VERSION 5.7 ;
  NOWIREEXTENSIONATPIN ON ;
  DIVIDERCHAR "/" ;
  BUSBITCHARS "[]" ;
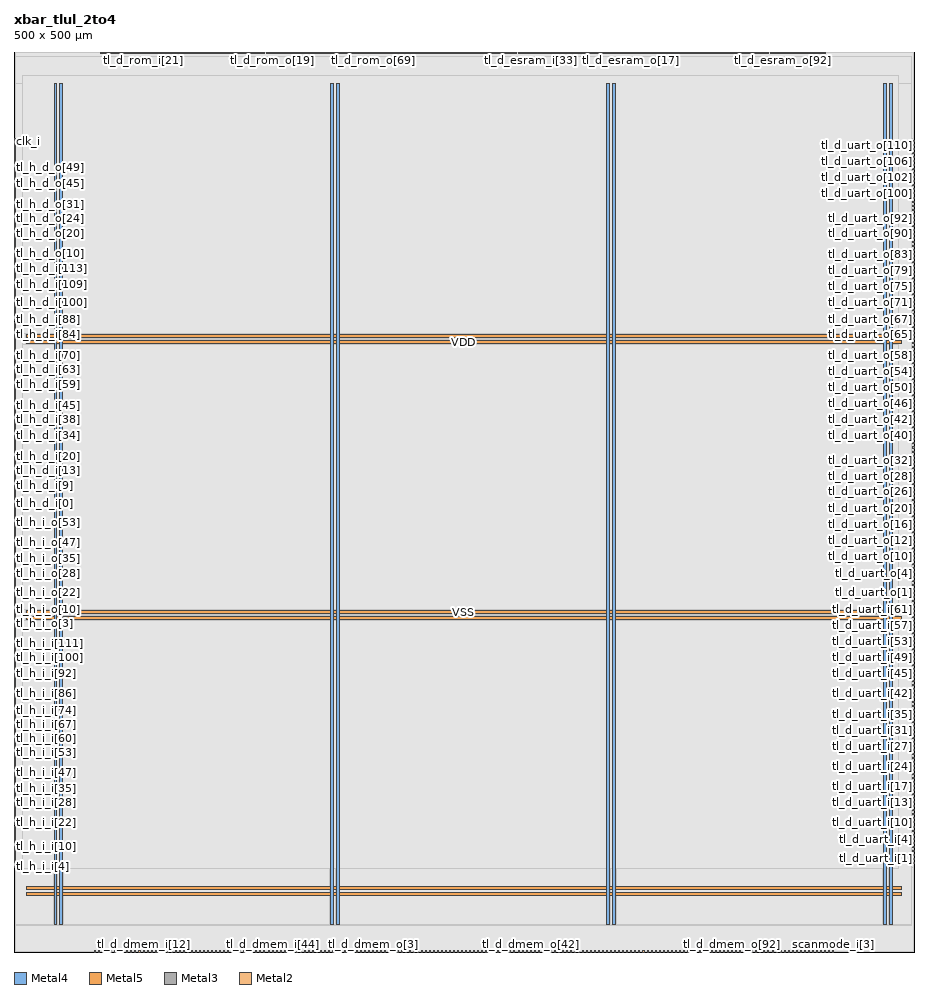
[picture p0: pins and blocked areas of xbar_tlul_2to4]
MACRO xbar_tlul_2to4
  CLASS BLOCK ;
  FOREIGN xbar_tlul_2to4 ;
  ORIGIN 0.000 0.000 ;
  SIZE 500.000 BY 500.000 ;
  PIN VDD
    DIRECTION INOUT ;
    USE POWER ;
    PORT
      LAYER Metal4 ;
        RECT 22.240 15.380 23.840 482.460 ;
    END
    PORT
      LAYER Metal4 ;
        RECT 175.840 15.380 177.440 482.460 ;
    END
    PORT
      LAYER Metal4 ;
        RECT 329.440 15.380 331.040 482.460 ;
    END
    PORT
      LAYER Metal4 ;
        RECT 483.040 15.380 484.640 482.460 ;
    END
    PORT
      LAYER Metal5 ;
        RECT 6.720 31.530 492.800 33.130 ;
    END
    PORT
      LAYER Metal5 ;
        RECT 6.720 184.710 492.800 186.310 ;
    END
    PORT
      LAYER Metal5 ;
        RECT 6.720 337.890 492.800 339.490 ;
    END
  END VDD
  PIN VSS
    DIRECTION INOUT ;
    USE GROUND ;
    PORT
      LAYER Metal4 ;
        RECT 25.540 15.380 27.140 482.460 ;
    END
    PORT
      LAYER Metal4 ;
        RECT 179.140 15.380 180.740 482.460 ;
    END
    PORT
      LAYER Metal4 ;
        RECT 332.740 15.380 334.340 482.460 ;
    END
    PORT
      LAYER Metal4 ;
        RECT 486.340 15.380 487.940 482.460 ;
    END
    PORT
      LAYER Metal5 ;
        RECT 6.720 34.830 492.800 36.430 ;
    END
    PORT
      LAYER Metal5 ;
        RECT 6.720 188.010 492.800 189.610 ;
    END
    PORT
      LAYER Metal5 ;
        RECT 6.720 341.190 492.800 342.790 ;
    END
  END VSS
  PIN clk_i
    DIRECTION INPUT ;
    USE SIGNAL ;
    ANTENNAGATEAREA 4.738000 ;
    PORT
      LAYER Metal3 ;
        RECT 0.000 450.240 0.560 450.800 ;
    END
  END clk_i
  PIN rst_ni
    DIRECTION INPUT ;
    USE SIGNAL ;
    ANTENNAGATEAREA 0.726000 ;
    PORT
      LAYER Metal3 ;
        RECT 0.000 451.360 0.560 451.920 ;
    END
  END rst_ni
  PIN scanmode_i[0]
    DIRECTION INPUT ;
    USE SIGNAL ;
    PORT
      LAYER Metal2 ;
        RECT 448.000 0.000 448.560 0.560 ;
    END
  END scanmode_i[0]
  PIN scanmode_i[1]
    DIRECTION INPUT ;
    USE SIGNAL ;
    PORT
      LAYER Metal2 ;
        RECT 450.240 0.000 450.800 0.560 ;
    END
  END scanmode_i[1]
  PIN scanmode_i[2]
    DIRECTION INPUT ;
    USE SIGNAL ;
    PORT
      LAYER Metal2 ;
        RECT 452.480 0.000 453.040 0.560 ;
    END
  END scanmode_i[2]
  PIN scanmode_i[3]
    DIRECTION INPUT ;
    USE SIGNAL ;
    PORT
      LAYER Metal2 ;
        RECT 454.720 0.000 455.280 0.560 ;
    END
  END scanmode_i[3]
  PIN tl_d_dmem_i[0]
    DIRECTION INPUT ;
    USE SIGNAL ;
    ANTENNAGATEAREA 0.396000 ;
    PORT
      LAYER Metal2 ;
        RECT 44.800 0.000 45.360 0.560 ;
    END
  END tl_d_dmem_i[0]
  PIN tl_d_dmem_i[10]
    DIRECTION INPUT ;
    USE SIGNAL ;
    ANTENNAGATEAREA 0.396000 ;
    PORT
      LAYER Metal2 ;
        RECT 67.200 0.000 67.760 0.560 ;
    END
  END tl_d_dmem_i[10]
  PIN tl_d_dmem_i[11]
    DIRECTION INPUT ;
    USE SIGNAL ;
    ANTENNAGATEAREA 0.396000 ;
    PORT
      LAYER Metal2 ;
        RECT 69.440 0.000 70.000 0.560 ;
    END
  END tl_d_dmem_i[11]
  PIN tl_d_dmem_i[12]
    DIRECTION INPUT ;
    USE SIGNAL ;
    ANTENNAGATEAREA 0.396000 ;
    PORT
      LAYER Metal2 ;
        RECT 71.680 0.000 72.240 0.560 ;
    END
  END tl_d_dmem_i[12]
  PIN tl_d_dmem_i[13]
    DIRECTION INPUT ;
    USE SIGNAL ;
    ANTENNAGATEAREA 0.396000 ;
    PORT
      LAYER Metal2 ;
        RECT 73.920 0.000 74.480 0.560 ;
    END
  END tl_d_dmem_i[13]
  PIN tl_d_dmem_i[14]
    DIRECTION INPUT ;
    USE SIGNAL ;
    ANTENNAGATEAREA 0.396000 ;
    PORT
      LAYER Metal2 ;
        RECT 76.160 0.000 76.720 0.560 ;
    END
  END tl_d_dmem_i[14]
  PIN tl_d_dmem_i[15]
    DIRECTION INPUT ;
    USE SIGNAL ;
    ANTENNAGATEAREA 0.396000 ;
    PORT
      LAYER Metal2 ;
        RECT 78.400 0.000 78.960 0.560 ;
    END
  END tl_d_dmem_i[15]
  PIN tl_d_dmem_i[16]
    DIRECTION INPUT ;
    USE SIGNAL ;
    ANTENNAGATEAREA 0.396000 ;
    PORT
      LAYER Metal2 ;
        RECT 80.640 0.000 81.200 0.560 ;
    END
  END tl_d_dmem_i[16]
  PIN tl_d_dmem_i[17]
    DIRECTION INPUT ;
    USE SIGNAL ;
    ANTENNAGATEAREA 0.396000 ;
    PORT
      LAYER Metal2 ;
        RECT 82.880 0.000 83.440 0.560 ;
    END
  END tl_d_dmem_i[17]
  PIN tl_d_dmem_i[18]
    DIRECTION INPUT ;
    USE SIGNAL ;
    ANTENNAGATEAREA 0.396000 ;
    PORT
      LAYER Metal2 ;
        RECT 85.120 0.000 85.680 0.560 ;
    END
  END tl_d_dmem_i[18]
  PIN tl_d_dmem_i[19]
    DIRECTION INPUT ;
    USE SIGNAL ;
    ANTENNAGATEAREA 0.396000 ;
    PORT
      LAYER Metal2 ;
        RECT 87.360 0.000 87.920 0.560 ;
    END
  END tl_d_dmem_i[19]
  PIN tl_d_dmem_i[1]
    DIRECTION INPUT ;
    USE SIGNAL ;
    ANTENNAGATEAREA 0.396000 ;
    PORT
      LAYER Metal2 ;
        RECT 47.040 0.000 47.600 0.560 ;
    END
  END tl_d_dmem_i[1]
  PIN tl_d_dmem_i[20]
    DIRECTION INPUT ;
    USE SIGNAL ;
    ANTENNAGATEAREA 0.396000 ;
    PORT
      LAYER Metal2 ;
        RECT 89.600 0.000 90.160 0.560 ;
    END
  END tl_d_dmem_i[20]
  PIN tl_d_dmem_i[21]
    DIRECTION INPUT ;
    USE SIGNAL ;
    ANTENNAGATEAREA 0.396000 ;
    PORT
      LAYER Metal2 ;
        RECT 91.840 0.000 92.400 0.560 ;
    END
  END tl_d_dmem_i[21]
  PIN tl_d_dmem_i[22]
    DIRECTION INPUT ;
    USE SIGNAL ;
    ANTENNAGATEAREA 0.396000 ;
    PORT
      LAYER Metal2 ;
        RECT 94.080 0.000 94.640 0.560 ;
    END
  END tl_d_dmem_i[22]
  PIN tl_d_dmem_i[23]
    DIRECTION INPUT ;
    USE SIGNAL ;
    ANTENNAGATEAREA 0.396000 ;
    PORT
      LAYER Metal2 ;
        RECT 96.320 0.000 96.880 0.560 ;
    END
  END tl_d_dmem_i[23]
  PIN tl_d_dmem_i[24]
    DIRECTION INPUT ;
    USE SIGNAL ;
    ANTENNAGATEAREA 0.396000 ;
    PORT
      LAYER Metal2 ;
        RECT 98.560 0.000 99.120 0.560 ;
    END
  END tl_d_dmem_i[24]
  PIN tl_d_dmem_i[25]
    DIRECTION INPUT ;
    USE SIGNAL ;
    ANTENNAGATEAREA 0.396000 ;
    PORT
      LAYER Metal2 ;
        RECT 100.800 0.000 101.360 0.560 ;
    END
  END tl_d_dmem_i[25]
  PIN tl_d_dmem_i[26]
    DIRECTION INPUT ;
    USE SIGNAL ;
    ANTENNAGATEAREA 0.396000 ;
    PORT
      LAYER Metal2 ;
        RECT 103.040 0.000 103.600 0.560 ;
    END
  END tl_d_dmem_i[26]
  PIN tl_d_dmem_i[27]
    DIRECTION INPUT ;
    USE SIGNAL ;
    ANTENNAGATEAREA 0.396000 ;
    PORT
      LAYER Metal2 ;
        RECT 105.280 0.000 105.840 0.560 ;
    END
  END tl_d_dmem_i[27]
  PIN tl_d_dmem_i[28]
    DIRECTION INPUT ;
    USE SIGNAL ;
    ANTENNAGATEAREA 0.396000 ;
    PORT
      LAYER Metal2 ;
        RECT 107.520 0.000 108.080 0.560 ;
    END
  END tl_d_dmem_i[28]
  PIN tl_d_dmem_i[29]
    DIRECTION INPUT ;
    USE SIGNAL ;
    ANTENNAGATEAREA 0.396000 ;
    PORT
      LAYER Metal2 ;
        RECT 109.760 0.000 110.320 0.560 ;
    END
  END tl_d_dmem_i[29]
  PIN tl_d_dmem_i[2]
    DIRECTION INPUT ;
    USE SIGNAL ;
    ANTENNAGATEAREA 0.396000 ;
    PORT
      LAYER Metal2 ;
        RECT 49.280 0.000 49.840 0.560 ;
    END
  END tl_d_dmem_i[2]
  PIN tl_d_dmem_i[30]
    DIRECTION INPUT ;
    USE SIGNAL ;
    ANTENNAGATEAREA 0.396000 ;
    PORT
      LAYER Metal2 ;
        RECT 112.000 0.000 112.560 0.560 ;
    END
  END tl_d_dmem_i[30]
  PIN tl_d_dmem_i[31]
    DIRECTION INPUT ;
    USE SIGNAL ;
    ANTENNAGATEAREA 0.396000 ;
    PORT
      LAYER Metal2 ;
        RECT 114.240 0.000 114.800 0.560 ;
    END
  END tl_d_dmem_i[31]
  PIN tl_d_dmem_i[32]
    DIRECTION INPUT ;
    USE SIGNAL ;
    ANTENNAGATEAREA 0.396000 ;
    PORT
      LAYER Metal2 ;
        RECT 116.480 0.000 117.040 0.560 ;
    END
  END tl_d_dmem_i[32]
  PIN tl_d_dmem_i[33]
    DIRECTION INPUT ;
    USE SIGNAL ;
    ANTENNAGATEAREA 0.396000 ;
    PORT
      LAYER Metal2 ;
        RECT 118.720 0.000 119.280 0.560 ;
    END
  END tl_d_dmem_i[33]
  PIN tl_d_dmem_i[34]
    DIRECTION INPUT ;
    USE SIGNAL ;
    ANTENNAGATEAREA 0.396000 ;
    PORT
      LAYER Metal2 ;
        RECT 120.960 0.000 121.520 0.560 ;
    END
  END tl_d_dmem_i[34]
  PIN tl_d_dmem_i[35]
    DIRECTION INPUT ;
    USE SIGNAL ;
    ANTENNAGATEAREA 0.396000 ;
    PORT
      LAYER Metal2 ;
        RECT 123.200 0.000 123.760 0.560 ;
    END
  END tl_d_dmem_i[35]
  PIN tl_d_dmem_i[36]
    DIRECTION INPUT ;
    USE SIGNAL ;
    ANTENNAGATEAREA 0.396000 ;
    PORT
      LAYER Metal2 ;
        RECT 125.440 0.000 126.000 0.560 ;
    END
  END tl_d_dmem_i[36]
  PIN tl_d_dmem_i[37]
    DIRECTION INPUT ;
    USE SIGNAL ;
    ANTENNAGATEAREA 0.396000 ;
    PORT
      LAYER Metal2 ;
        RECT 127.680 0.000 128.240 0.560 ;
    END
  END tl_d_dmem_i[37]
  PIN tl_d_dmem_i[38]
    DIRECTION INPUT ;
    USE SIGNAL ;
    ANTENNAGATEAREA 0.396000 ;
    PORT
      LAYER Metal2 ;
        RECT 129.920 0.000 130.480 0.560 ;
    END
  END tl_d_dmem_i[38]
  PIN tl_d_dmem_i[39]
    DIRECTION INPUT ;
    USE SIGNAL ;
    ANTENNAGATEAREA 0.396000 ;
    PORT
      LAYER Metal2 ;
        RECT 132.160 0.000 132.720 0.560 ;
    END
  END tl_d_dmem_i[39]
  PIN tl_d_dmem_i[3]
    DIRECTION INPUT ;
    USE SIGNAL ;
    ANTENNAGATEAREA 0.396000 ;
    PORT
      LAYER Metal2 ;
        RECT 51.520 0.000 52.080 0.560 ;
    END
  END tl_d_dmem_i[3]
  PIN tl_d_dmem_i[40]
    DIRECTION INPUT ;
    USE SIGNAL ;
    ANTENNAGATEAREA 0.396000 ;
    PORT
      LAYER Metal2 ;
        RECT 134.400 0.000 134.960 0.560 ;
    END
  END tl_d_dmem_i[40]
  PIN tl_d_dmem_i[41]
    DIRECTION INPUT ;
    USE SIGNAL ;
    ANTENNAGATEAREA 0.396000 ;
    PORT
      LAYER Metal2 ;
        RECT 136.640 0.000 137.200 0.560 ;
    END
  END tl_d_dmem_i[41]
  PIN tl_d_dmem_i[42]
    DIRECTION INPUT ;
    USE SIGNAL ;
    ANTENNAGATEAREA 0.396000 ;
    PORT
      LAYER Metal2 ;
        RECT 138.880 0.000 139.440 0.560 ;
    END
  END tl_d_dmem_i[42]
  PIN tl_d_dmem_i[43]
    DIRECTION INPUT ;
    USE SIGNAL ;
    ANTENNAGATEAREA 0.396000 ;
    PORT
      LAYER Metal2 ;
        RECT 141.120 0.000 141.680 0.560 ;
    END
  END tl_d_dmem_i[43]
  PIN tl_d_dmem_i[44]
    DIRECTION INPUT ;
    USE SIGNAL ;
    ANTENNAGATEAREA 0.396000 ;
    PORT
      LAYER Metal2 ;
        RECT 143.360 0.000 143.920 0.560 ;
    END
  END tl_d_dmem_i[44]
  PIN tl_d_dmem_i[45]
    DIRECTION INPUT ;
    USE SIGNAL ;
    ANTENNAGATEAREA 0.396000 ;
    PORT
      LAYER Metal2 ;
        RECT 145.600 0.000 146.160 0.560 ;
    END
  END tl_d_dmem_i[45]
  PIN tl_d_dmem_i[46]
    DIRECTION INPUT ;
    USE SIGNAL ;
    ANTENNAGATEAREA 0.396000 ;
    PORT
      LAYER Metal2 ;
        RECT 147.840 0.000 148.400 0.560 ;
    END
  END tl_d_dmem_i[46]
  PIN tl_d_dmem_i[47]
    DIRECTION INPUT ;
    USE SIGNAL ;
    ANTENNAGATEAREA 0.396000 ;
    PORT
      LAYER Metal2 ;
        RECT 150.080 0.000 150.640 0.560 ;
    END
  END tl_d_dmem_i[47]
  PIN tl_d_dmem_i[48]
    DIRECTION INPUT ;
    USE SIGNAL ;
    ANTENNAGATEAREA 0.396000 ;
    PORT
      LAYER Metal2 ;
        RECT 152.320 0.000 152.880 0.560 ;
    END
  END tl_d_dmem_i[48]
  PIN tl_d_dmem_i[49]
    DIRECTION INPUT ;
    USE SIGNAL ;
    ANTENNAGATEAREA 0.396000 ;
    PORT
      LAYER Metal2 ;
        RECT 154.560 0.000 155.120 0.560 ;
    END
  END tl_d_dmem_i[49]
  PIN tl_d_dmem_i[4]
    DIRECTION INPUT ;
    USE SIGNAL ;
    ANTENNAGATEAREA 0.396000 ;
    PORT
      LAYER Metal2 ;
        RECT 53.760 0.000 54.320 0.560 ;
    END
  END tl_d_dmem_i[4]
  PIN tl_d_dmem_i[50]
    DIRECTION INPUT ;
    USE SIGNAL ;
    ANTENNAGATEAREA 0.396000 ;
    PORT
      LAYER Metal2 ;
        RECT 156.800 0.000 157.360 0.560 ;
    END
  END tl_d_dmem_i[50]
  PIN tl_d_dmem_i[51]
    DIRECTION INPUT ;
    USE SIGNAL ;
    ANTENNAGATEAREA 0.396000 ;
    PORT
      LAYER Metal2 ;
        RECT 159.040 0.000 159.600 0.560 ;
    END
  END tl_d_dmem_i[51]
  PIN tl_d_dmem_i[52]
    DIRECTION INPUT ;
    USE SIGNAL ;
    ANTENNAGATEAREA 0.396000 ;
    PORT
      LAYER Metal2 ;
        RECT 161.280 0.000 161.840 0.560 ;
    END
  END tl_d_dmem_i[52]
  PIN tl_d_dmem_i[53]
    DIRECTION INPUT ;
    USE SIGNAL ;
    ANTENNAGATEAREA 0.396000 ;
    PORT
      LAYER Metal2 ;
        RECT 163.520 0.000 164.080 0.560 ;
    END
  END tl_d_dmem_i[53]
  PIN tl_d_dmem_i[54]
    DIRECTION INPUT ;
    USE SIGNAL ;
    ANTENNAGATEAREA 0.396000 ;
    PORT
      LAYER Metal2 ;
        RECT 165.760 0.000 166.320 0.560 ;
    END
  END tl_d_dmem_i[54]
  PIN tl_d_dmem_i[55]
    DIRECTION INPUT ;
    USE SIGNAL ;
    ANTENNAGATEAREA 0.396000 ;
    PORT
      LAYER Metal2 ;
        RECT 168.000 0.000 168.560 0.560 ;
    END
  END tl_d_dmem_i[55]
  PIN tl_d_dmem_i[56]
    DIRECTION INPUT ;
    USE SIGNAL ;
    ANTENNAGATEAREA 0.396000 ;
    PORT
      LAYER Metal2 ;
        RECT 170.240 0.000 170.800 0.560 ;
    END
  END tl_d_dmem_i[56]
  PIN tl_d_dmem_i[57]
    DIRECTION INPUT ;
    USE SIGNAL ;
    ANTENNAGATEAREA 0.396000 ;
    PORT
      LAYER Metal2 ;
        RECT 172.480 0.000 173.040 0.560 ;
    END
  END tl_d_dmem_i[57]
  PIN tl_d_dmem_i[58]
    DIRECTION INPUT ;
    USE SIGNAL ;
    ANTENNAGATEAREA 0.396000 ;
    PORT
      LAYER Metal2 ;
        RECT 174.720 0.000 175.280 0.560 ;
    END
  END tl_d_dmem_i[58]
  PIN tl_d_dmem_i[59]
    DIRECTION INPUT ;
    USE SIGNAL ;
    ANTENNAGATEAREA 0.396000 ;
    PORT
      LAYER Metal2 ;
        RECT 176.960 0.000 177.520 0.560 ;
    END
  END tl_d_dmem_i[59]
  PIN tl_d_dmem_i[5]
    DIRECTION INPUT ;
    USE SIGNAL ;
    ANTENNAGATEAREA 0.396000 ;
    PORT
      LAYER Metal2 ;
        RECT 56.000 0.000 56.560 0.560 ;
    END
  END tl_d_dmem_i[5]
  PIN tl_d_dmem_i[60]
    DIRECTION INPUT ;
    USE SIGNAL ;
    ANTENNAGATEAREA 0.396000 ;
    PORT
      LAYER Metal2 ;
        RECT 179.200 0.000 179.760 0.560 ;
    END
  END tl_d_dmem_i[60]
  PIN tl_d_dmem_i[61]
    DIRECTION INPUT ;
    USE SIGNAL ;
    ANTENNAGATEAREA 0.396000 ;
    PORT
      LAYER Metal2 ;
        RECT 181.440 0.000 182.000 0.560 ;
    END
  END tl_d_dmem_i[61]
  PIN tl_d_dmem_i[62]
    DIRECTION INPUT ;
    USE SIGNAL ;
    ANTENNAGATEAREA 0.396000 ;
    PORT
      LAYER Metal2 ;
        RECT 183.680 0.000 184.240 0.560 ;
    END
  END tl_d_dmem_i[62]
  PIN tl_d_dmem_i[63]
    DIRECTION INPUT ;
    USE SIGNAL ;
    ANTENNAGATEAREA 0.396000 ;
    PORT
      LAYER Metal2 ;
        RECT 185.920 0.000 186.480 0.560 ;
    END
  END tl_d_dmem_i[63]
  PIN tl_d_dmem_i[64]
    DIRECTION INPUT ;
    USE SIGNAL ;
    ANTENNAGATEAREA 0.396000 ;
    PORT
      LAYER Metal2 ;
        RECT 188.160 0.000 188.720 0.560 ;
    END
  END tl_d_dmem_i[64]
  PIN tl_d_dmem_i[65]
    DIRECTION INPUT ;
    USE SIGNAL ;
    ANTENNAGATEAREA 0.396000 ;
    PORT
      LAYER Metal2 ;
        RECT 190.400 0.000 190.960 0.560 ;
    END
  END tl_d_dmem_i[65]
  PIN tl_d_dmem_i[6]
    DIRECTION INPUT ;
    USE SIGNAL ;
    ANTENNAGATEAREA 0.396000 ;
    PORT
      LAYER Metal2 ;
        RECT 58.240 0.000 58.800 0.560 ;
    END
  END tl_d_dmem_i[6]
  PIN tl_d_dmem_i[7]
    DIRECTION INPUT ;
    USE SIGNAL ;
    ANTENNAGATEAREA 0.396000 ;
    PORT
      LAYER Metal2 ;
        RECT 60.480 0.000 61.040 0.560 ;
    END
  END tl_d_dmem_i[7]
  PIN tl_d_dmem_i[8]
    DIRECTION INPUT ;
    USE SIGNAL ;
    ANTENNAGATEAREA 0.396000 ;
    PORT
      LAYER Metal2 ;
        RECT 62.720 0.000 63.280 0.560 ;
    END
  END tl_d_dmem_i[8]
  PIN tl_d_dmem_i[9]
    DIRECTION INPUT ;
    USE SIGNAL ;
    ANTENNAGATEAREA 0.396000 ;
    PORT
      LAYER Metal2 ;
        RECT 64.960 0.000 65.520 0.560 ;
    END
  END tl_d_dmem_i[9]
  PIN tl_d_dmem_o[0]
    DIRECTION OUTPUT ;
    USE SIGNAL ;
    ANTENNADIFFAREA 0.897600 ;
    PORT
      LAYER Metal2 ;
        RECT 192.640 0.000 193.200 0.560 ;
    END
  END tl_d_dmem_o[0]
  PIN tl_d_dmem_o[100]
    DIRECTION OUTPUT ;
    USE SIGNAL ;
    ANTENNADIFFAREA 0.897600 ;
    PORT
      LAYER Metal2 ;
        RECT 416.640 0.000 417.200 0.560 ;
    END
  END tl_d_dmem_o[100]
  PIN tl_d_dmem_o[101]
    DIRECTION OUTPUT ;
    USE SIGNAL ;
    ANTENNADIFFAREA 0.897600 ;
    PORT
      LAYER Metal2 ;
        RECT 418.880 0.000 419.440 0.560 ;
    END
  END tl_d_dmem_o[101]
  PIN tl_d_dmem_o[102]
    DIRECTION OUTPUT ;
    USE SIGNAL ;
    ANTENNADIFFAREA 0.897600 ;
    PORT
      LAYER Metal2 ;
        RECT 421.120 0.000 421.680 0.560 ;
    END
  END tl_d_dmem_o[102]
  PIN tl_d_dmem_o[103]
    DIRECTION OUTPUT ;
    USE SIGNAL ;
    ANTENNADIFFAREA 0.897600 ;
    PORT
      LAYER Metal2 ;
        RECT 423.360 0.000 423.920 0.560 ;
    END
  END tl_d_dmem_o[103]
  PIN tl_d_dmem_o[104]
    DIRECTION OUTPUT ;
    USE SIGNAL ;
    ANTENNADIFFAREA 0.897600 ;
    PORT
      LAYER Metal2 ;
        RECT 425.600 0.000 426.160 0.560 ;
    END
  END tl_d_dmem_o[104]
  PIN tl_d_dmem_o[105]
    DIRECTION OUTPUT ;
    USE SIGNAL ;
    ANTENNADIFFAREA 0.897600 ;
    PORT
      LAYER Metal2 ;
        RECT 427.840 0.000 428.400 0.560 ;
    END
  END tl_d_dmem_o[105]
  PIN tl_d_dmem_o[106]
    DIRECTION OUTPUT ;
    USE SIGNAL ;
    ANTENNADIFFAREA 0.897600 ;
    PORT
      LAYER Metal2 ;
        RECT 430.080 0.000 430.640 0.560 ;
    END
  END tl_d_dmem_o[106]
  PIN tl_d_dmem_o[107]
    DIRECTION OUTPUT ;
    USE SIGNAL ;
    ANTENNADIFFAREA 0.897600 ;
    PORT
      LAYER Metal2 ;
        RECT 432.320 0.000 432.880 0.560 ;
    END
  END tl_d_dmem_o[107]
  PIN tl_d_dmem_o[108]
    DIRECTION OUTPUT ;
    USE SIGNAL ;
    ANTENNADIFFAREA 0.897600 ;
    PORT
      LAYER Metal2 ;
        RECT 434.560 0.000 435.120 0.560 ;
    END
  END tl_d_dmem_o[108]
  PIN tl_d_dmem_o[109]
    DIRECTION OUTPUT ;
    USE SIGNAL ;
    ANTENNADIFFAREA 0.897600 ;
    PORT
      LAYER Metal2 ;
        RECT 436.800 0.000 437.360 0.560 ;
    END
  END tl_d_dmem_o[109]
  PIN tl_d_dmem_o[10]
    DIRECTION OUTPUT ;
    USE SIGNAL ;
    ANTENNADIFFAREA 0.897600 ;
    PORT
      LAYER Metal2 ;
        RECT 215.040 0.000 215.600 0.560 ;
    END
  END tl_d_dmem_o[10]
  PIN tl_d_dmem_o[110]
    DIRECTION OUTPUT ;
    USE SIGNAL ;
    ANTENNADIFFAREA 0.897600 ;
    PORT
      LAYER Metal2 ;
        RECT 439.040 0.000 439.600 0.560 ;
    END
  END tl_d_dmem_o[110]
  PIN tl_d_dmem_o[111]
    DIRECTION OUTPUT ;
    USE SIGNAL ;
    ANTENNADIFFAREA 0.897600 ;
    PORT
      LAYER Metal2 ;
        RECT 441.280 0.000 441.840 0.560 ;
    END
  END tl_d_dmem_o[111]
  PIN tl_d_dmem_o[112]
    DIRECTION OUTPUT ;
    USE SIGNAL ;
    ANTENNADIFFAREA 0.897600 ;
    PORT
      LAYER Metal2 ;
        RECT 443.520 0.000 444.080 0.560 ;
    END
  END tl_d_dmem_o[112]
  PIN tl_d_dmem_o[113]
    DIRECTION OUTPUT ;
    USE SIGNAL ;
    ANTENNADIFFAREA 0.897600 ;
    PORT
      LAYER Metal2 ;
        RECT 445.760 0.000 446.320 0.560 ;
    END
  END tl_d_dmem_o[113]
  PIN tl_d_dmem_o[11]
    DIRECTION OUTPUT ;
    USE SIGNAL ;
    ANTENNADIFFAREA 0.897600 ;
    PORT
      LAYER Metal2 ;
        RECT 217.280 0.000 217.840 0.560 ;
    END
  END tl_d_dmem_o[11]
  PIN tl_d_dmem_o[12]
    DIRECTION OUTPUT ;
    USE SIGNAL ;
    ANTENNADIFFAREA 0.897600 ;
    PORT
      LAYER Metal2 ;
        RECT 219.520 0.000 220.080 0.560 ;
    END
  END tl_d_dmem_o[12]
  PIN tl_d_dmem_o[13]
    DIRECTION OUTPUT ;
    USE SIGNAL ;
    ANTENNADIFFAREA 0.897600 ;
    PORT
      LAYER Metal2 ;
        RECT 221.760 0.000 222.320 0.560 ;
    END
  END tl_d_dmem_o[13]
  PIN tl_d_dmem_o[14]
    DIRECTION OUTPUT ;
    USE SIGNAL ;
    ANTENNADIFFAREA 0.897600 ;
    PORT
      LAYER Metal2 ;
        RECT 224.000 0.000 224.560 0.560 ;
    END
  END tl_d_dmem_o[14]
  PIN tl_d_dmem_o[15]
    DIRECTION OUTPUT ;
    USE SIGNAL ;
    ANTENNADIFFAREA 0.897600 ;
    PORT
      LAYER Metal2 ;
        RECT 226.240 0.000 226.800 0.560 ;
    END
  END tl_d_dmem_o[15]
  PIN tl_d_dmem_o[16]
    DIRECTION OUTPUT ;
    USE SIGNAL ;
    ANTENNADIFFAREA 0.897600 ;
    PORT
      LAYER Metal2 ;
        RECT 228.480 0.000 229.040 0.560 ;
    END
  END tl_d_dmem_o[16]
  PIN tl_d_dmem_o[17]
    DIRECTION OUTPUT ;
    USE SIGNAL ;
    ANTENNADIFFAREA 0.897600 ;
    PORT
      LAYER Metal2 ;
        RECT 230.720 0.000 231.280 0.560 ;
    END
  END tl_d_dmem_o[17]
  PIN tl_d_dmem_o[18]
    DIRECTION OUTPUT ;
    USE SIGNAL ;
    ANTENNADIFFAREA 0.897600 ;
    PORT
      LAYER Metal2 ;
        RECT 232.960 0.000 233.520 0.560 ;
    END
  END tl_d_dmem_o[18]
  PIN tl_d_dmem_o[19]
    DIRECTION OUTPUT ;
    USE SIGNAL ;
    ANTENNADIFFAREA 0.897600 ;
    PORT
      LAYER Metal2 ;
        RECT 235.200 0.000 235.760 0.560 ;
    END
  END tl_d_dmem_o[19]
  PIN tl_d_dmem_o[1]
    DIRECTION OUTPUT ;
    USE SIGNAL ;
    ANTENNADIFFAREA 0.897600 ;
    PORT
      LAYER Metal2 ;
        RECT 194.880 0.000 195.440 0.560 ;
    END
  END tl_d_dmem_o[1]
  PIN tl_d_dmem_o[20]
    DIRECTION OUTPUT ;
    USE SIGNAL ;
    ANTENNADIFFAREA 0.897600 ;
    PORT
      LAYER Metal2 ;
        RECT 237.440 0.000 238.000 0.560 ;
    END
  END tl_d_dmem_o[20]
  PIN tl_d_dmem_o[21]
    DIRECTION OUTPUT ;
    USE SIGNAL ;
    ANTENNADIFFAREA 0.897600 ;
    PORT
      LAYER Metal2 ;
        RECT 239.680 0.000 240.240 0.560 ;
    END
  END tl_d_dmem_o[21]
  PIN tl_d_dmem_o[22]
    DIRECTION OUTPUT ;
    USE SIGNAL ;
    ANTENNADIFFAREA 0.897600 ;
    PORT
      LAYER Metal2 ;
        RECT 241.920 0.000 242.480 0.560 ;
    END
  END tl_d_dmem_o[22]
  PIN tl_d_dmem_o[23]
    DIRECTION OUTPUT ;
    USE SIGNAL ;
    ANTENNADIFFAREA 0.897600 ;
    PORT
      LAYER Metal2 ;
        RECT 244.160 0.000 244.720 0.560 ;
    END
  END tl_d_dmem_o[23]
  PIN tl_d_dmem_o[24]
    DIRECTION OUTPUT ;
    USE SIGNAL ;
    ANTENNADIFFAREA 0.897600 ;
    PORT
      LAYER Metal2 ;
        RECT 246.400 0.000 246.960 0.560 ;
    END
  END tl_d_dmem_o[24]
  PIN tl_d_dmem_o[25]
    DIRECTION OUTPUT ;
    USE SIGNAL ;
    ANTENNADIFFAREA 0.897600 ;
    PORT
      LAYER Metal2 ;
        RECT 248.640 0.000 249.200 0.560 ;
    END
  END tl_d_dmem_o[25]
  PIN tl_d_dmem_o[26]
    DIRECTION OUTPUT ;
    USE SIGNAL ;
    ANTENNADIFFAREA 0.897600 ;
    PORT
      LAYER Metal2 ;
        RECT 250.880 0.000 251.440 0.560 ;
    END
  END tl_d_dmem_o[26]
  PIN tl_d_dmem_o[27]
    DIRECTION OUTPUT ;
    USE SIGNAL ;
    ANTENNADIFFAREA 0.897600 ;
    PORT
      LAYER Metal2 ;
        RECT 253.120 0.000 253.680 0.560 ;
    END
  END tl_d_dmem_o[27]
  PIN tl_d_dmem_o[28]
    DIRECTION OUTPUT ;
    USE SIGNAL ;
    ANTENNADIFFAREA 0.897600 ;
    PORT
      LAYER Metal2 ;
        RECT 255.360 0.000 255.920 0.560 ;
    END
  END tl_d_dmem_o[28]
  PIN tl_d_dmem_o[29]
    DIRECTION OUTPUT ;
    USE SIGNAL ;
    ANTENNADIFFAREA 0.897600 ;
    PORT
      LAYER Metal2 ;
        RECT 257.600 0.000 258.160 0.560 ;
    END
  END tl_d_dmem_o[29]
  PIN tl_d_dmem_o[2]
    DIRECTION OUTPUT ;
    USE SIGNAL ;
    ANTENNADIFFAREA 0.897600 ;
    PORT
      LAYER Metal2 ;
        RECT 197.120 0.000 197.680 0.560 ;
    END
  END tl_d_dmem_o[2]
  PIN tl_d_dmem_o[30]
    DIRECTION OUTPUT ;
    USE SIGNAL ;
    ANTENNADIFFAREA 0.897600 ;
    PORT
      LAYER Metal2 ;
        RECT 259.840 0.000 260.400 0.560 ;
    END
  END tl_d_dmem_o[30]
  PIN tl_d_dmem_o[31]
    DIRECTION OUTPUT ;
    USE SIGNAL ;
    ANTENNADIFFAREA 0.897600 ;
    PORT
      LAYER Metal2 ;
        RECT 262.080 0.000 262.640 0.560 ;
    END
  END tl_d_dmem_o[31]
  PIN tl_d_dmem_o[32]
    DIRECTION OUTPUT ;
    USE SIGNAL ;
    ANTENNADIFFAREA 0.897600 ;
    PORT
      LAYER Metal2 ;
        RECT 264.320 0.000 264.880 0.560 ;
    END
  END tl_d_dmem_o[32]
  PIN tl_d_dmem_o[33]
    DIRECTION OUTPUT ;
    USE SIGNAL ;
    ANTENNADIFFAREA 0.897600 ;
    PORT
      LAYER Metal2 ;
        RECT 266.560 0.000 267.120 0.560 ;
    END
  END tl_d_dmem_o[33]
  PIN tl_d_dmem_o[34]
    DIRECTION OUTPUT ;
    USE SIGNAL ;
    ANTENNADIFFAREA 0.897600 ;
    PORT
      LAYER Metal2 ;
        RECT 268.800 0.000 269.360 0.560 ;
    END
  END tl_d_dmem_o[34]
  PIN tl_d_dmem_o[35]
    DIRECTION OUTPUT ;
    USE SIGNAL ;
    ANTENNADIFFAREA 0.897600 ;
    PORT
      LAYER Metal2 ;
        RECT 271.040 0.000 271.600 0.560 ;
    END
  END tl_d_dmem_o[35]
  PIN tl_d_dmem_o[36]
    DIRECTION OUTPUT ;
    USE SIGNAL ;
    ANTENNADIFFAREA 0.897600 ;
    PORT
      LAYER Metal2 ;
        RECT 273.280 0.000 273.840 0.560 ;
    END
  END tl_d_dmem_o[36]
  PIN tl_d_dmem_o[37]
    DIRECTION OUTPUT ;
    USE SIGNAL ;
    ANTENNADIFFAREA 0.897600 ;
    PORT
      LAYER Metal2 ;
        RECT 275.520 0.000 276.080 0.560 ;
    END
  END tl_d_dmem_o[37]
  PIN tl_d_dmem_o[38]
    DIRECTION OUTPUT ;
    USE SIGNAL ;
    ANTENNADIFFAREA 0.897600 ;
    PORT
      LAYER Metal2 ;
        RECT 277.760 0.000 278.320 0.560 ;
    END
  END tl_d_dmem_o[38]
  PIN tl_d_dmem_o[39]
    DIRECTION OUTPUT ;
    USE SIGNAL ;
    ANTENNADIFFAREA 0.897600 ;
    PORT
      LAYER Metal2 ;
        RECT 280.000 0.000 280.560 0.560 ;
    END
  END tl_d_dmem_o[39]
  PIN tl_d_dmem_o[3]
    DIRECTION OUTPUT ;
    USE SIGNAL ;
    ANTENNADIFFAREA 0.897600 ;
    PORT
      LAYER Metal2 ;
        RECT 199.360 0.000 199.920 0.560 ;
    END
  END tl_d_dmem_o[3]
  PIN tl_d_dmem_o[40]
    DIRECTION OUTPUT ;
    USE SIGNAL ;
    ANTENNADIFFAREA 0.897600 ;
    PORT
      LAYER Metal2 ;
        RECT 282.240 0.000 282.800 0.560 ;
    END
  END tl_d_dmem_o[40]
  PIN tl_d_dmem_o[41]
    DIRECTION OUTPUT ;
    USE SIGNAL ;
    ANTENNADIFFAREA 0.897600 ;
    PORT
      LAYER Metal2 ;
        RECT 284.480 0.000 285.040 0.560 ;
    END
  END tl_d_dmem_o[41]
  PIN tl_d_dmem_o[42]
    DIRECTION OUTPUT ;
    USE SIGNAL ;
    ANTENNADIFFAREA 0.897600 ;
    PORT
      LAYER Metal2 ;
        RECT 286.720 0.000 287.280 0.560 ;
    END
  END tl_d_dmem_o[42]
  PIN tl_d_dmem_o[43]
    DIRECTION OUTPUT ;
    USE SIGNAL ;
    ANTENNADIFFAREA 0.897600 ;
    PORT
      LAYER Metal2 ;
        RECT 288.960 0.000 289.520 0.560 ;
    END
  END tl_d_dmem_o[43]
  PIN tl_d_dmem_o[44]
    DIRECTION OUTPUT ;
    USE SIGNAL ;
    ANTENNADIFFAREA 0.897600 ;
    PORT
      LAYER Metal2 ;
        RECT 291.200 0.000 291.760 0.560 ;
    END
  END tl_d_dmem_o[44]
  PIN tl_d_dmem_o[45]
    DIRECTION OUTPUT ;
    USE SIGNAL ;
    ANTENNADIFFAREA 0.897600 ;
    PORT
      LAYER Metal2 ;
        RECT 293.440 0.000 294.000 0.560 ;
    END
  END tl_d_dmem_o[45]
  PIN tl_d_dmem_o[46]
    DIRECTION OUTPUT ;
    USE SIGNAL ;
    ANTENNADIFFAREA 0.897600 ;
    PORT
      LAYER Metal2 ;
        RECT 295.680 0.000 296.240 0.560 ;
    END
  END tl_d_dmem_o[46]
  PIN tl_d_dmem_o[47]
    DIRECTION OUTPUT ;
    USE SIGNAL ;
    ANTENNADIFFAREA 0.897600 ;
    PORT
      LAYER Metal2 ;
        RECT 297.920 0.000 298.480 0.560 ;
    END
  END tl_d_dmem_o[47]
  PIN tl_d_dmem_o[48]
    DIRECTION OUTPUT ;
    USE SIGNAL ;
    ANTENNADIFFAREA 0.897600 ;
    PORT
      LAYER Metal2 ;
        RECT 300.160 0.000 300.720 0.560 ;
    END
  END tl_d_dmem_o[48]
  PIN tl_d_dmem_o[49]
    DIRECTION OUTPUT ;
    USE SIGNAL ;
    ANTENNADIFFAREA 0.897600 ;
    PORT
      LAYER Metal2 ;
        RECT 302.400 0.000 302.960 0.560 ;
    END
  END tl_d_dmem_o[49]
  PIN tl_d_dmem_o[4]
    DIRECTION OUTPUT ;
    USE SIGNAL ;
    ANTENNADIFFAREA 0.897600 ;
    PORT
      LAYER Metal2 ;
        RECT 201.600 0.000 202.160 0.560 ;
    END
  END tl_d_dmem_o[4]
  PIN tl_d_dmem_o[50]
    DIRECTION OUTPUT ;
    USE SIGNAL ;
    ANTENNADIFFAREA 0.897600 ;
    PORT
      LAYER Metal2 ;
        RECT 304.640 0.000 305.200 0.560 ;
    END
  END tl_d_dmem_o[50]
  PIN tl_d_dmem_o[51]
    DIRECTION OUTPUT ;
    USE SIGNAL ;
    ANTENNADIFFAREA 0.897600 ;
    PORT
      LAYER Metal2 ;
        RECT 306.880 0.000 307.440 0.560 ;
    END
  END tl_d_dmem_o[51]
  PIN tl_d_dmem_o[52]
    DIRECTION OUTPUT ;
    USE SIGNAL ;
    ANTENNADIFFAREA 0.897600 ;
    PORT
      LAYER Metal2 ;
        RECT 309.120 0.000 309.680 0.560 ;
    END
  END tl_d_dmem_o[52]
  PIN tl_d_dmem_o[53]
    DIRECTION OUTPUT ;
    USE SIGNAL ;
    ANTENNADIFFAREA 0.897600 ;
    PORT
      LAYER Metal2 ;
        RECT 311.360 0.000 311.920 0.560 ;
    END
  END tl_d_dmem_o[53]
  PIN tl_d_dmem_o[54]
    DIRECTION OUTPUT ;
    USE SIGNAL ;
    ANTENNADIFFAREA 0.897600 ;
    PORT
      LAYER Metal2 ;
        RECT 313.600 0.000 314.160 0.560 ;
    END
  END tl_d_dmem_o[54]
  PIN tl_d_dmem_o[55]
    DIRECTION OUTPUT ;
    USE SIGNAL ;
    ANTENNADIFFAREA 0.897600 ;
    PORT
      LAYER Metal2 ;
        RECT 315.840 0.000 316.400 0.560 ;
    END
  END tl_d_dmem_o[55]
  PIN tl_d_dmem_o[56]
    DIRECTION OUTPUT ;
    USE SIGNAL ;
    ANTENNADIFFAREA 0.897600 ;
    PORT
      LAYER Metal2 ;
        RECT 318.080 0.000 318.640 0.560 ;
    END
  END tl_d_dmem_o[56]
  PIN tl_d_dmem_o[57]
    DIRECTION OUTPUT ;
    USE SIGNAL ;
    ANTENNADIFFAREA 0.897600 ;
    PORT
      LAYER Metal2 ;
        RECT 320.320 0.000 320.880 0.560 ;
    END
  END tl_d_dmem_o[57]
  PIN tl_d_dmem_o[58]
    DIRECTION OUTPUT ;
    USE SIGNAL ;
    ANTENNADIFFAREA 0.897600 ;
    PORT
      LAYER Metal2 ;
        RECT 322.560 0.000 323.120 0.560 ;
    END
  END tl_d_dmem_o[58]
  PIN tl_d_dmem_o[59]
    DIRECTION OUTPUT ;
    USE SIGNAL ;
    ANTENNADIFFAREA 0.897600 ;
    PORT
      LAYER Metal2 ;
        RECT 324.800 0.000 325.360 0.560 ;
    END
  END tl_d_dmem_o[59]
  PIN tl_d_dmem_o[5]
    DIRECTION OUTPUT ;
    USE SIGNAL ;
    ANTENNADIFFAREA 0.897600 ;
    PORT
      LAYER Metal2 ;
        RECT 203.840 0.000 204.400 0.560 ;
    END
  END tl_d_dmem_o[5]
  PIN tl_d_dmem_o[60]
    DIRECTION OUTPUT ;
    USE SIGNAL ;
    ANTENNADIFFAREA 0.897600 ;
    PORT
      LAYER Metal2 ;
        RECT 327.040 0.000 327.600 0.560 ;
    END
  END tl_d_dmem_o[60]
  PIN tl_d_dmem_o[61]
    DIRECTION OUTPUT ;
    USE SIGNAL ;
    ANTENNADIFFAREA 0.897600 ;
    PORT
      LAYER Metal2 ;
        RECT 329.280 0.000 329.840 0.560 ;
    END
  END tl_d_dmem_o[61]
  PIN tl_d_dmem_o[62]
    DIRECTION OUTPUT ;
    USE SIGNAL ;
    ANTENNADIFFAREA 0.897600 ;
    PORT
      LAYER Metal2 ;
        RECT 331.520 0.000 332.080 0.560 ;
    END
  END tl_d_dmem_o[62]
  PIN tl_d_dmem_o[63]
    DIRECTION OUTPUT ;
    USE SIGNAL ;
    ANTENNADIFFAREA 0.897600 ;
    PORT
      LAYER Metal2 ;
        RECT 333.760 0.000 334.320 0.560 ;
    END
  END tl_d_dmem_o[63]
  PIN tl_d_dmem_o[64]
    DIRECTION OUTPUT ;
    USE SIGNAL ;
    ANTENNADIFFAREA 0.897600 ;
    PORT
      LAYER Metal2 ;
        RECT 336.000 0.000 336.560 0.560 ;
    END
  END tl_d_dmem_o[64]
  PIN tl_d_dmem_o[65]
    DIRECTION OUTPUT ;
    USE SIGNAL ;
    ANTENNADIFFAREA 0.897600 ;
    PORT
      LAYER Metal2 ;
        RECT 338.240 0.000 338.800 0.560 ;
    END
  END tl_d_dmem_o[65]
  PIN tl_d_dmem_o[66]
    DIRECTION OUTPUT ;
    USE SIGNAL ;
    ANTENNADIFFAREA 0.897600 ;
    PORT
      LAYER Metal2 ;
        RECT 340.480 0.000 341.040 0.560 ;
    END
  END tl_d_dmem_o[66]
  PIN tl_d_dmem_o[67]
    DIRECTION OUTPUT ;
    USE SIGNAL ;
    ANTENNADIFFAREA 0.897600 ;
    PORT
      LAYER Metal2 ;
        RECT 342.720 0.000 343.280 0.560 ;
    END
  END tl_d_dmem_o[67]
  PIN tl_d_dmem_o[68]
    DIRECTION OUTPUT ;
    USE SIGNAL ;
    ANTENNADIFFAREA 0.897600 ;
    PORT
      LAYER Metal2 ;
        RECT 344.960 0.000 345.520 0.560 ;
    END
  END tl_d_dmem_o[68]
  PIN tl_d_dmem_o[69]
    DIRECTION OUTPUT ;
    USE SIGNAL ;
    ANTENNADIFFAREA 0.897600 ;
    PORT
      LAYER Metal2 ;
        RECT 347.200 0.000 347.760 0.560 ;
    END
  END tl_d_dmem_o[69]
  PIN tl_d_dmem_o[6]
    DIRECTION OUTPUT ;
    USE SIGNAL ;
    ANTENNADIFFAREA 0.897600 ;
    PORT
      LAYER Metal2 ;
        RECT 206.080 0.000 206.640 0.560 ;
    END
  END tl_d_dmem_o[6]
  PIN tl_d_dmem_o[70]
    DIRECTION OUTPUT ;
    USE SIGNAL ;
    ANTENNADIFFAREA 0.897600 ;
    PORT
      LAYER Metal2 ;
        RECT 349.440 0.000 350.000 0.560 ;
    END
  END tl_d_dmem_o[70]
  PIN tl_d_dmem_o[71]
    DIRECTION OUTPUT ;
    USE SIGNAL ;
    ANTENNADIFFAREA 0.897600 ;
    PORT
      LAYER Metal2 ;
        RECT 351.680 0.000 352.240 0.560 ;
    END
  END tl_d_dmem_o[71]
  PIN tl_d_dmem_o[72]
    DIRECTION OUTPUT ;
    USE SIGNAL ;
    ANTENNADIFFAREA 0.897600 ;
    PORT
      LAYER Metal2 ;
        RECT 353.920 0.000 354.480 0.560 ;
    END
  END tl_d_dmem_o[72]
  PIN tl_d_dmem_o[73]
    DIRECTION OUTPUT ;
    USE SIGNAL ;
    ANTENNADIFFAREA 0.897600 ;
    PORT
      LAYER Metal2 ;
        RECT 356.160 0.000 356.720 0.560 ;
    END
  END tl_d_dmem_o[73]
  PIN tl_d_dmem_o[74]
    DIRECTION OUTPUT ;
    USE SIGNAL ;
    ANTENNADIFFAREA 0.897600 ;
    PORT
      LAYER Metal2 ;
        RECT 358.400 0.000 358.960 0.560 ;
    END
  END tl_d_dmem_o[74]
  PIN tl_d_dmem_o[75]
    DIRECTION OUTPUT ;
    USE SIGNAL ;
    ANTENNADIFFAREA 0.897600 ;
    PORT
      LAYER Metal2 ;
        RECT 360.640 0.000 361.200 0.560 ;
    END
  END tl_d_dmem_o[75]
  PIN tl_d_dmem_o[76]
    DIRECTION OUTPUT ;
    USE SIGNAL ;
    ANTENNADIFFAREA 0.897600 ;
    PORT
      LAYER Metal2 ;
        RECT 362.880 0.000 363.440 0.560 ;
    END
  END tl_d_dmem_o[76]
  PIN tl_d_dmem_o[77]
    DIRECTION OUTPUT ;
    USE SIGNAL ;
    ANTENNADIFFAREA 0.897600 ;
    PORT
      LAYER Metal2 ;
        RECT 365.120 0.000 365.680 0.560 ;
    END
  END tl_d_dmem_o[77]
  PIN tl_d_dmem_o[78]
    DIRECTION OUTPUT ;
    USE SIGNAL ;
    ANTENNADIFFAREA 0.897600 ;
    PORT
      LAYER Metal2 ;
        RECT 367.360 0.000 367.920 0.560 ;
    END
  END tl_d_dmem_o[78]
  PIN tl_d_dmem_o[79]
    DIRECTION OUTPUT ;
    USE SIGNAL ;
    ANTENNADIFFAREA 0.897600 ;
    PORT
      LAYER Metal2 ;
        RECT 369.600 0.000 370.160 0.560 ;
    END
  END tl_d_dmem_o[79]
  PIN tl_d_dmem_o[7]
    DIRECTION OUTPUT ;
    USE SIGNAL ;
    ANTENNADIFFAREA 0.897600 ;
    PORT
      LAYER Metal2 ;
        RECT 208.320 0.000 208.880 0.560 ;
    END
  END tl_d_dmem_o[7]
  PIN tl_d_dmem_o[80]
    DIRECTION OUTPUT ;
    USE SIGNAL ;
    ANTENNADIFFAREA 0.897600 ;
    PORT
      LAYER Metal2 ;
        RECT 371.840 0.000 372.400 0.560 ;
    END
  END tl_d_dmem_o[80]
  PIN tl_d_dmem_o[81]
    DIRECTION OUTPUT ;
    USE SIGNAL ;
    ANTENNADIFFAREA 0.897600 ;
    PORT
      LAYER Metal2 ;
        RECT 374.080 0.000 374.640 0.560 ;
    END
  END tl_d_dmem_o[81]
  PIN tl_d_dmem_o[82]
    DIRECTION OUTPUT ;
    USE SIGNAL ;
    ANTENNADIFFAREA 0.897600 ;
    PORT
      LAYER Metal2 ;
        RECT 376.320 0.000 376.880 0.560 ;
    END
  END tl_d_dmem_o[82]
  PIN tl_d_dmem_o[83]
    DIRECTION OUTPUT ;
    USE SIGNAL ;
    ANTENNADIFFAREA 0.897600 ;
    PORT
      LAYER Metal2 ;
        RECT 378.560 0.000 379.120 0.560 ;
    END
  END tl_d_dmem_o[83]
  PIN tl_d_dmem_o[84]
    DIRECTION OUTPUT ;
    USE SIGNAL ;
    ANTENNADIFFAREA 0.897600 ;
    PORT
      LAYER Metal2 ;
        RECT 380.800 0.000 381.360 0.560 ;
    END
  END tl_d_dmem_o[84]
  PIN tl_d_dmem_o[85]
    DIRECTION OUTPUT ;
    USE SIGNAL ;
    ANTENNADIFFAREA 0.897600 ;
    PORT
      LAYER Metal2 ;
        RECT 383.040 0.000 383.600 0.560 ;
    END
  END tl_d_dmem_o[85]
  PIN tl_d_dmem_o[86]
    DIRECTION OUTPUT ;
    USE SIGNAL ;
    ANTENNADIFFAREA 0.897600 ;
    PORT
      LAYER Metal2 ;
        RECT 385.280 0.000 385.840 0.560 ;
    END
  END tl_d_dmem_o[86]
  PIN tl_d_dmem_o[87]
    DIRECTION OUTPUT ;
    USE SIGNAL ;
    ANTENNADIFFAREA 0.897600 ;
    PORT
      LAYER Metal2 ;
        RECT 387.520 0.000 388.080 0.560 ;
    END
  END tl_d_dmem_o[87]
  PIN tl_d_dmem_o[88]
    DIRECTION OUTPUT ;
    USE SIGNAL ;
    ANTENNADIFFAREA 0.897600 ;
    PORT
      LAYER Metal2 ;
        RECT 389.760 0.000 390.320 0.560 ;
    END
  END tl_d_dmem_o[88]
  PIN tl_d_dmem_o[89]
    DIRECTION OUTPUT ;
    USE SIGNAL ;
    ANTENNADIFFAREA 0.897600 ;
    PORT
      LAYER Metal2 ;
        RECT 392.000 0.000 392.560 0.560 ;
    END
  END tl_d_dmem_o[89]
  PIN tl_d_dmem_o[8]
    DIRECTION OUTPUT ;
    USE SIGNAL ;
    ANTENNADIFFAREA 0.897600 ;
    PORT
      LAYER Metal2 ;
        RECT 210.560 0.000 211.120 0.560 ;
    END
  END tl_d_dmem_o[8]
  PIN tl_d_dmem_o[90]
    DIRECTION OUTPUT ;
    USE SIGNAL ;
    ANTENNADIFFAREA 0.897600 ;
    PORT
      LAYER Metal2 ;
        RECT 394.240 0.000 394.800 0.560 ;
    END
  END tl_d_dmem_o[90]
  PIN tl_d_dmem_o[91]
    DIRECTION OUTPUT ;
    USE SIGNAL ;
    ANTENNADIFFAREA 0.897600 ;
    PORT
      LAYER Metal2 ;
        RECT 396.480 0.000 397.040 0.560 ;
    END
  END tl_d_dmem_o[91]
  PIN tl_d_dmem_o[92]
    DIRECTION OUTPUT ;
    USE SIGNAL ;
    ANTENNADIFFAREA 0.897600 ;
    PORT
      LAYER Metal2 ;
        RECT 398.720 0.000 399.280 0.560 ;
    END
  END tl_d_dmem_o[92]
  PIN tl_d_dmem_o[93]
    DIRECTION OUTPUT ;
    USE SIGNAL ;
    ANTENNADIFFAREA 0.897600 ;
    PORT
      LAYER Metal2 ;
        RECT 400.960 0.000 401.520 0.560 ;
    END
  END tl_d_dmem_o[93]
  PIN tl_d_dmem_o[94]
    DIRECTION OUTPUT ;
    USE SIGNAL ;
    ANTENNADIFFAREA 0.897600 ;
    PORT
      LAYER Metal2 ;
        RECT 403.200 0.000 403.760 0.560 ;
    END
  END tl_d_dmem_o[94]
  PIN tl_d_dmem_o[95]
    DIRECTION OUTPUT ;
    USE SIGNAL ;
    ANTENNADIFFAREA 0.897600 ;
    PORT
      LAYER Metal2 ;
        RECT 405.440 0.000 406.000 0.560 ;
    END
  END tl_d_dmem_o[95]
  PIN tl_d_dmem_o[96]
    DIRECTION OUTPUT ;
    USE SIGNAL ;
    ANTENNADIFFAREA 0.897600 ;
    PORT
      LAYER Metal2 ;
        RECT 407.680 0.000 408.240 0.560 ;
    END
  END tl_d_dmem_o[96]
  PIN tl_d_dmem_o[97]
    DIRECTION OUTPUT ;
    USE SIGNAL ;
    ANTENNADIFFAREA 0.897600 ;
    PORT
      LAYER Metal2 ;
        RECT 409.920 0.000 410.480 0.560 ;
    END
  END tl_d_dmem_o[97]
  PIN tl_d_dmem_o[98]
    DIRECTION OUTPUT ;
    USE SIGNAL ;
    ANTENNADIFFAREA 0.897600 ;
    PORT
      LAYER Metal2 ;
        RECT 412.160 0.000 412.720 0.560 ;
    END
  END tl_d_dmem_o[98]
  PIN tl_d_dmem_o[99]
    DIRECTION OUTPUT ;
    USE SIGNAL ;
    ANTENNADIFFAREA 0.897600 ;
    PORT
      LAYER Metal2 ;
        RECT 414.400 0.000 414.960 0.560 ;
    END
  END tl_d_dmem_o[99]
  PIN tl_d_dmem_o[9]
    DIRECTION OUTPUT ;
    USE SIGNAL ;
    ANTENNADIFFAREA 0.897600 ;
    PORT
      LAYER Metal2 ;
        RECT 212.800 0.000 213.360 0.560 ;
    END
  END tl_d_dmem_o[9]
  PIN tl_d_esram_i[0]
    DIRECTION INPUT ;
    USE SIGNAL ;
    ANTENNAGATEAREA 0.396000 ;
    PORT
      LAYER Metal2 ;
        RECT 249.760 499.440 250.320 500.000 ;
    END
  END tl_d_esram_i[0]
  PIN tl_d_esram_i[10]
    DIRECTION INPUT ;
    USE SIGNAL ;
    ANTENNAGATEAREA 0.396000 ;
    PORT
      LAYER Metal2 ;
        RECT 260.960 499.440 261.520 500.000 ;
    END
  END tl_d_esram_i[10]
  PIN tl_d_esram_i[11]
    DIRECTION INPUT ;
    USE SIGNAL ;
    ANTENNAGATEAREA 0.396000 ;
    PORT
      LAYER Metal2 ;
        RECT 262.080 499.440 262.640 500.000 ;
    END
  END tl_d_esram_i[11]
  PIN tl_d_esram_i[12]
    DIRECTION INPUT ;
    USE SIGNAL ;
    ANTENNAGATEAREA 0.396000 ;
    PORT
      LAYER Metal2 ;
        RECT 263.200 499.440 263.760 500.000 ;
    END
  END tl_d_esram_i[12]
  PIN tl_d_esram_i[13]
    DIRECTION INPUT ;
    USE SIGNAL ;
    ANTENNAGATEAREA 0.396000 ;
    PORT
      LAYER Metal2 ;
        RECT 264.320 499.440 264.880 500.000 ;
    END
  END tl_d_esram_i[13]
  PIN tl_d_esram_i[14]
    DIRECTION INPUT ;
    USE SIGNAL ;
    ANTENNAGATEAREA 0.396000 ;
    PORT
      LAYER Metal2 ;
        RECT 265.440 499.440 266.000 500.000 ;
    END
  END tl_d_esram_i[14]
  PIN tl_d_esram_i[15]
    DIRECTION INPUT ;
    USE SIGNAL ;
    ANTENNAGATEAREA 0.396000 ;
    PORT
      LAYER Metal2 ;
        RECT 266.560 499.440 267.120 500.000 ;
    END
  END tl_d_esram_i[15]
  PIN tl_d_esram_i[16]
    DIRECTION INPUT ;
    USE SIGNAL ;
    ANTENNAGATEAREA 0.396000 ;
    PORT
      LAYER Metal2 ;
        RECT 267.680 499.440 268.240 500.000 ;
    END
  END tl_d_esram_i[16]
  PIN tl_d_esram_i[17]
    DIRECTION INPUT ;
    USE SIGNAL ;
    ANTENNAGATEAREA 0.396000 ;
    PORT
      LAYER Metal2 ;
        RECT 268.800 499.440 269.360 500.000 ;
    END
  END tl_d_esram_i[17]
  PIN tl_d_esram_i[18]
    DIRECTION INPUT ;
    USE SIGNAL ;
    ANTENNAGATEAREA 0.396000 ;
    PORT
      LAYER Metal2 ;
        RECT 269.920 499.440 270.480 500.000 ;
    END
  END tl_d_esram_i[18]
  PIN tl_d_esram_i[19]
    DIRECTION INPUT ;
    USE SIGNAL ;
    ANTENNAGATEAREA 0.396000 ;
    PORT
      LAYER Metal2 ;
        RECT 271.040 499.440 271.600 500.000 ;
    END
  END tl_d_esram_i[19]
  PIN tl_d_esram_i[1]
    DIRECTION INPUT ;
    USE SIGNAL ;
    ANTENNAGATEAREA 0.396000 ;
    PORT
      LAYER Metal2 ;
        RECT 250.880 499.440 251.440 500.000 ;
    END
  END tl_d_esram_i[1]
  PIN tl_d_esram_i[20]
    DIRECTION INPUT ;
    USE SIGNAL ;
    ANTENNAGATEAREA 0.396000 ;
    PORT
      LAYER Metal2 ;
        RECT 272.160 499.440 272.720 500.000 ;
    END
  END tl_d_esram_i[20]
  PIN tl_d_esram_i[21]
    DIRECTION INPUT ;
    USE SIGNAL ;
    ANTENNAGATEAREA 0.396000 ;
    PORT
      LAYER Metal2 ;
        RECT 273.280 499.440 273.840 500.000 ;
    END
  END tl_d_esram_i[21]
  PIN tl_d_esram_i[22]
    DIRECTION INPUT ;
    USE SIGNAL ;
    ANTENNAGATEAREA 0.396000 ;
    PORT
      LAYER Metal2 ;
        RECT 274.400 499.440 274.960 500.000 ;
    END
  END tl_d_esram_i[22]
  PIN tl_d_esram_i[23]
    DIRECTION INPUT ;
    USE SIGNAL ;
    ANTENNAGATEAREA 0.396000 ;
    PORT
      LAYER Metal2 ;
        RECT 275.520 499.440 276.080 500.000 ;
    END
  END tl_d_esram_i[23]
  PIN tl_d_esram_i[24]
    DIRECTION INPUT ;
    USE SIGNAL ;
    ANTENNAGATEAREA 0.396000 ;
    PORT
      LAYER Metal2 ;
        RECT 276.640 499.440 277.200 500.000 ;
    END
  END tl_d_esram_i[24]
  PIN tl_d_esram_i[25]
    DIRECTION INPUT ;
    USE SIGNAL ;
    ANTENNAGATEAREA 0.396000 ;
    PORT
      LAYER Metal2 ;
        RECT 277.760 499.440 278.320 500.000 ;
    END
  END tl_d_esram_i[25]
  PIN tl_d_esram_i[26]
    DIRECTION INPUT ;
    USE SIGNAL ;
    ANTENNAGATEAREA 0.396000 ;
    PORT
      LAYER Metal2 ;
        RECT 278.880 499.440 279.440 500.000 ;
    END
  END tl_d_esram_i[26]
  PIN tl_d_esram_i[27]
    DIRECTION INPUT ;
    USE SIGNAL ;
    ANTENNAGATEAREA 0.396000 ;
    PORT
      LAYER Metal2 ;
        RECT 280.000 499.440 280.560 500.000 ;
    END
  END tl_d_esram_i[27]
  PIN tl_d_esram_i[28]
    DIRECTION INPUT ;
    USE SIGNAL ;
    ANTENNAGATEAREA 0.396000 ;
    PORT
      LAYER Metal2 ;
        RECT 281.120 499.440 281.680 500.000 ;
    END
  END tl_d_esram_i[28]
  PIN tl_d_esram_i[29]
    DIRECTION INPUT ;
    USE SIGNAL ;
    ANTENNAGATEAREA 0.396000 ;
    PORT
      LAYER Metal2 ;
        RECT 282.240 499.440 282.800 500.000 ;
    END
  END tl_d_esram_i[29]
  PIN tl_d_esram_i[2]
    DIRECTION INPUT ;
    USE SIGNAL ;
    ANTENNAGATEAREA 0.396000 ;
    PORT
      LAYER Metal2 ;
        RECT 252.000 499.440 252.560 500.000 ;
    END
  END tl_d_esram_i[2]
  PIN tl_d_esram_i[30]
    DIRECTION INPUT ;
    USE SIGNAL ;
    ANTENNAGATEAREA 0.396000 ;
    PORT
      LAYER Metal2 ;
        RECT 283.360 499.440 283.920 500.000 ;
    END
  END tl_d_esram_i[30]
  PIN tl_d_esram_i[31]
    DIRECTION INPUT ;
    USE SIGNAL ;
    ANTENNAGATEAREA 0.396000 ;
    PORT
      LAYER Metal2 ;
        RECT 284.480 499.440 285.040 500.000 ;
    END
  END tl_d_esram_i[31]
  PIN tl_d_esram_i[32]
    DIRECTION INPUT ;
    USE SIGNAL ;
    ANTENNAGATEAREA 0.396000 ;
    PORT
      LAYER Metal2 ;
        RECT 285.600 499.440 286.160 500.000 ;
    END
  END tl_d_esram_i[32]
  PIN tl_d_esram_i[33]
    DIRECTION INPUT ;
    USE SIGNAL ;
    ANTENNAGATEAREA 0.396000 ;
    PORT
      LAYER Metal2 ;
        RECT 286.720 499.440 287.280 500.000 ;
    END
  END tl_d_esram_i[33]
  PIN tl_d_esram_i[34]
    DIRECTION INPUT ;
    USE SIGNAL ;
    ANTENNAGATEAREA 0.396000 ;
    PORT
      LAYER Metal2 ;
        RECT 287.840 499.440 288.400 500.000 ;
    END
  END tl_d_esram_i[34]
  PIN tl_d_esram_i[35]
    DIRECTION INPUT ;
    USE SIGNAL ;
    ANTENNAGATEAREA 0.396000 ;
    PORT
      LAYER Metal2 ;
        RECT 288.960 499.440 289.520 500.000 ;
    END
  END tl_d_esram_i[35]
  PIN tl_d_esram_i[36]
    DIRECTION INPUT ;
    USE SIGNAL ;
    ANTENNAGATEAREA 0.396000 ;
    PORT
      LAYER Metal2 ;
        RECT 290.080 499.440 290.640 500.000 ;
    END
  END tl_d_esram_i[36]
  PIN tl_d_esram_i[37]
    DIRECTION INPUT ;
    USE SIGNAL ;
    ANTENNAGATEAREA 0.396000 ;
    PORT
      LAYER Metal2 ;
        RECT 291.200 499.440 291.760 500.000 ;
    END
  END tl_d_esram_i[37]
  PIN tl_d_esram_i[38]
    DIRECTION INPUT ;
    USE SIGNAL ;
    ANTENNAGATEAREA 0.396000 ;
    PORT
      LAYER Metal2 ;
        RECT 292.320 499.440 292.880 500.000 ;
    END
  END tl_d_esram_i[38]
  PIN tl_d_esram_i[39]
    DIRECTION INPUT ;
    USE SIGNAL ;
    ANTENNAGATEAREA 0.396000 ;
    PORT
      LAYER Metal2 ;
        RECT 293.440 499.440 294.000 500.000 ;
    END
  END tl_d_esram_i[39]
  PIN tl_d_esram_i[3]
    DIRECTION INPUT ;
    USE SIGNAL ;
    ANTENNAGATEAREA 0.396000 ;
    PORT
      LAYER Metal2 ;
        RECT 253.120 499.440 253.680 500.000 ;
    END
  END tl_d_esram_i[3]
  PIN tl_d_esram_i[40]
    DIRECTION INPUT ;
    USE SIGNAL ;
    ANTENNAGATEAREA 0.396000 ;
    PORT
      LAYER Metal2 ;
        RECT 294.560 499.440 295.120 500.000 ;
    END
  END tl_d_esram_i[40]
  PIN tl_d_esram_i[41]
    DIRECTION INPUT ;
    USE SIGNAL ;
    ANTENNAGATEAREA 0.396000 ;
    PORT
      LAYER Metal2 ;
        RECT 295.680 499.440 296.240 500.000 ;
    END
  END tl_d_esram_i[41]
  PIN tl_d_esram_i[42]
    DIRECTION INPUT ;
    USE SIGNAL ;
    ANTENNAGATEAREA 0.396000 ;
    PORT
      LAYER Metal2 ;
        RECT 296.800 499.440 297.360 500.000 ;
    END
  END tl_d_esram_i[42]
  PIN tl_d_esram_i[43]
    DIRECTION INPUT ;
    USE SIGNAL ;
    ANTENNAGATEAREA 0.396000 ;
    PORT
      LAYER Metal2 ;
        RECT 297.920 499.440 298.480 500.000 ;
    END
  END tl_d_esram_i[43]
  PIN tl_d_esram_i[44]
    DIRECTION INPUT ;
    USE SIGNAL ;
    ANTENNAGATEAREA 0.396000 ;
    PORT
      LAYER Metal2 ;
        RECT 299.040 499.440 299.600 500.000 ;
    END
  END tl_d_esram_i[44]
  PIN tl_d_esram_i[45]
    DIRECTION INPUT ;
    USE SIGNAL ;
    ANTENNAGATEAREA 0.396000 ;
    PORT
      LAYER Metal2 ;
        RECT 300.160 499.440 300.720 500.000 ;
    END
  END tl_d_esram_i[45]
  PIN tl_d_esram_i[46]
    DIRECTION INPUT ;
    USE SIGNAL ;
    ANTENNAGATEAREA 0.396000 ;
    PORT
      LAYER Metal2 ;
        RECT 301.280 499.440 301.840 500.000 ;
    END
  END tl_d_esram_i[46]
  PIN tl_d_esram_i[47]
    DIRECTION INPUT ;
    USE SIGNAL ;
    ANTENNAGATEAREA 0.396000 ;
    PORT
      LAYER Metal2 ;
        RECT 302.400 499.440 302.960 500.000 ;
    END
  END tl_d_esram_i[47]
  PIN tl_d_esram_i[48]
    DIRECTION INPUT ;
    USE SIGNAL ;
    ANTENNAGATEAREA 0.396000 ;
    PORT
      LAYER Metal2 ;
        RECT 303.520 499.440 304.080 500.000 ;
    END
  END tl_d_esram_i[48]
  PIN tl_d_esram_i[49]
    DIRECTION INPUT ;
    USE SIGNAL ;
    ANTENNAGATEAREA 0.396000 ;
    PORT
      LAYER Metal2 ;
        RECT 304.640 499.440 305.200 500.000 ;
    END
  END tl_d_esram_i[49]
  PIN tl_d_esram_i[4]
    DIRECTION INPUT ;
    USE SIGNAL ;
    ANTENNAGATEAREA 0.396000 ;
    PORT
      LAYER Metal2 ;
        RECT 254.240 499.440 254.800 500.000 ;
    END
  END tl_d_esram_i[4]
  PIN tl_d_esram_i[50]
    DIRECTION INPUT ;
    USE SIGNAL ;
    ANTENNAGATEAREA 0.396000 ;
    PORT
      LAYER Metal2 ;
        RECT 305.760 499.440 306.320 500.000 ;
    END
  END tl_d_esram_i[50]
  PIN tl_d_esram_i[51]
    DIRECTION INPUT ;
    USE SIGNAL ;
    ANTENNAGATEAREA 0.396000 ;
    PORT
      LAYER Metal2 ;
        RECT 306.880 499.440 307.440 500.000 ;
    END
  END tl_d_esram_i[51]
  PIN tl_d_esram_i[52]
    DIRECTION INPUT ;
    USE SIGNAL ;
    ANTENNAGATEAREA 0.396000 ;
    PORT
      LAYER Metal2 ;
        RECT 308.000 499.440 308.560 500.000 ;
    END
  END tl_d_esram_i[52]
  PIN tl_d_esram_i[53]
    DIRECTION INPUT ;
    USE SIGNAL ;
    ANTENNAGATEAREA 0.396000 ;
    PORT
      LAYER Metal2 ;
        RECT 309.120 499.440 309.680 500.000 ;
    END
  END tl_d_esram_i[53]
  PIN tl_d_esram_i[54]
    DIRECTION INPUT ;
    USE SIGNAL ;
    ANTENNAGATEAREA 0.396000 ;
    PORT
      LAYER Metal2 ;
        RECT 310.240 499.440 310.800 500.000 ;
    END
  END tl_d_esram_i[54]
  PIN tl_d_esram_i[55]
    DIRECTION INPUT ;
    USE SIGNAL ;
    ANTENNAGATEAREA 0.396000 ;
    PORT
      LAYER Metal2 ;
        RECT 311.360 499.440 311.920 500.000 ;
    END
  END tl_d_esram_i[55]
  PIN tl_d_esram_i[56]
    DIRECTION INPUT ;
    USE SIGNAL ;
    ANTENNAGATEAREA 0.396000 ;
    PORT
      LAYER Metal2 ;
        RECT 312.480 499.440 313.040 500.000 ;
    END
  END tl_d_esram_i[56]
  PIN tl_d_esram_i[57]
    DIRECTION INPUT ;
    USE SIGNAL ;
    ANTENNAGATEAREA 0.396000 ;
    PORT
      LAYER Metal2 ;
        RECT 313.600 499.440 314.160 500.000 ;
    END
  END tl_d_esram_i[57]
  PIN tl_d_esram_i[58]
    DIRECTION INPUT ;
    USE SIGNAL ;
    ANTENNAGATEAREA 0.396000 ;
    PORT
      LAYER Metal2 ;
        RECT 314.720 499.440 315.280 500.000 ;
    END
  END tl_d_esram_i[58]
  PIN tl_d_esram_i[59]
    DIRECTION INPUT ;
    USE SIGNAL ;
    ANTENNAGATEAREA 0.396000 ;
    PORT
      LAYER Metal2 ;
        RECT 315.840 499.440 316.400 500.000 ;
    END
  END tl_d_esram_i[59]
  PIN tl_d_esram_i[5]
    DIRECTION INPUT ;
    USE SIGNAL ;
    ANTENNAGATEAREA 0.396000 ;
    PORT
      LAYER Metal2 ;
        RECT 255.360 499.440 255.920 500.000 ;
    END
  END tl_d_esram_i[5]
  PIN tl_d_esram_i[60]
    DIRECTION INPUT ;
    USE SIGNAL ;
    ANTENNAGATEAREA 0.396000 ;
    PORT
      LAYER Metal2 ;
        RECT 316.960 499.440 317.520 500.000 ;
    END
  END tl_d_esram_i[60]
  PIN tl_d_esram_i[61]
    DIRECTION INPUT ;
    USE SIGNAL ;
    ANTENNAGATEAREA 0.396000 ;
    PORT
      LAYER Metal2 ;
        RECT 318.080 499.440 318.640 500.000 ;
    END
  END tl_d_esram_i[61]
  PIN tl_d_esram_i[62]
    DIRECTION INPUT ;
    USE SIGNAL ;
    ANTENNAGATEAREA 0.396000 ;
    PORT
      LAYER Metal2 ;
        RECT 319.200 499.440 319.760 500.000 ;
    END
  END tl_d_esram_i[62]
  PIN tl_d_esram_i[63]
    DIRECTION INPUT ;
    USE SIGNAL ;
    ANTENNAGATEAREA 0.396000 ;
    PORT
      LAYER Metal2 ;
        RECT 320.320 499.440 320.880 500.000 ;
    END
  END tl_d_esram_i[63]
  PIN tl_d_esram_i[64]
    DIRECTION INPUT ;
    USE SIGNAL ;
    ANTENNAGATEAREA 0.396000 ;
    PORT
      LAYER Metal2 ;
        RECT 321.440 499.440 322.000 500.000 ;
    END
  END tl_d_esram_i[64]
  PIN tl_d_esram_i[65]
    DIRECTION INPUT ;
    USE SIGNAL ;
    ANTENNAGATEAREA 0.396000 ;
    PORT
      LAYER Metal2 ;
        RECT 322.560 499.440 323.120 500.000 ;
    END
  END tl_d_esram_i[65]
  PIN tl_d_esram_i[6]
    DIRECTION INPUT ;
    USE SIGNAL ;
    ANTENNAGATEAREA 0.396000 ;
    PORT
      LAYER Metal2 ;
        RECT 256.480 499.440 257.040 500.000 ;
    END
  END tl_d_esram_i[6]
  PIN tl_d_esram_i[7]
    DIRECTION INPUT ;
    USE SIGNAL ;
    ANTENNAGATEAREA 0.396000 ;
    PORT
      LAYER Metal2 ;
        RECT 257.600 499.440 258.160 500.000 ;
    END
  END tl_d_esram_i[7]
  PIN tl_d_esram_i[8]
    DIRECTION INPUT ;
    USE SIGNAL ;
    ANTENNAGATEAREA 0.396000 ;
    PORT
      LAYER Metal2 ;
        RECT 258.720 499.440 259.280 500.000 ;
    END
  END tl_d_esram_i[8]
  PIN tl_d_esram_i[9]
    DIRECTION INPUT ;
    USE SIGNAL ;
    ANTENNAGATEAREA 0.396000 ;
    PORT
      LAYER Metal2 ;
        RECT 259.840 499.440 260.400 500.000 ;
    END
  END tl_d_esram_i[9]
  PIN tl_d_esram_o[0]
    DIRECTION OUTPUT ;
    USE SIGNAL ;
    ANTENNADIFFAREA 0.897600 ;
    PORT
      LAYER Metal2 ;
        RECT 323.680 499.440 324.240 500.000 ;
    END
  END tl_d_esram_o[0]
  PIN tl_d_esram_o[100]
    DIRECTION OUTPUT ;
    USE SIGNAL ;
    ANTENNADIFFAREA 0.897600 ;
    PORT
      LAYER Metal2 ;
        RECT 435.680 499.440 436.240 500.000 ;
    END
  END tl_d_esram_o[100]
  PIN tl_d_esram_o[101]
    DIRECTION OUTPUT ;
    USE SIGNAL ;
    ANTENNADIFFAREA 0.897600 ;
    PORT
      LAYER Metal2 ;
        RECT 436.800 499.440 437.360 500.000 ;
    END
  END tl_d_esram_o[101]
  PIN tl_d_esram_o[102]
    DIRECTION OUTPUT ;
    USE SIGNAL ;
    ANTENNADIFFAREA 0.897600 ;
    PORT
      LAYER Metal2 ;
        RECT 437.920 499.440 438.480 500.000 ;
    END
  END tl_d_esram_o[102]
  PIN tl_d_esram_o[103]
    DIRECTION OUTPUT ;
    USE SIGNAL ;
    ANTENNADIFFAREA 0.897600 ;
    PORT
      LAYER Metal2 ;
        RECT 439.040 499.440 439.600 500.000 ;
    END
  END tl_d_esram_o[103]
  PIN tl_d_esram_o[104]
    DIRECTION OUTPUT ;
    USE SIGNAL ;
    ANTENNADIFFAREA 0.897600 ;
    PORT
      LAYER Metal2 ;
        RECT 440.160 499.440 440.720 500.000 ;
    END
  END tl_d_esram_o[104]
  PIN tl_d_esram_o[105]
    DIRECTION OUTPUT ;
    USE SIGNAL ;
    ANTENNADIFFAREA 0.897600 ;
    PORT
      LAYER Metal2 ;
        RECT 441.280 499.440 441.840 500.000 ;
    END
  END tl_d_esram_o[105]
  PIN tl_d_esram_o[106]
    DIRECTION OUTPUT ;
    USE SIGNAL ;
    ANTENNADIFFAREA 0.897600 ;
    PORT
      LAYER Metal2 ;
        RECT 442.400 499.440 442.960 500.000 ;
    END
  END tl_d_esram_o[106]
  PIN tl_d_esram_o[107]
    DIRECTION OUTPUT ;
    USE SIGNAL ;
    ANTENNADIFFAREA 0.897600 ;
    PORT
      LAYER Metal2 ;
        RECT 443.520 499.440 444.080 500.000 ;
    END
  END tl_d_esram_o[107]
  PIN tl_d_esram_o[108]
    DIRECTION OUTPUT ;
    USE SIGNAL ;
    ANTENNADIFFAREA 0.897600 ;
    PORT
      LAYER Metal2 ;
        RECT 444.640 499.440 445.200 500.000 ;
    END
  END tl_d_esram_o[108]
  PIN tl_d_esram_o[109]
    DIRECTION OUTPUT ;
    USE SIGNAL ;
    ANTENNADIFFAREA 0.897600 ;
    PORT
      LAYER Metal2 ;
        RECT 445.760 499.440 446.320 500.000 ;
    END
  END tl_d_esram_o[109]
  PIN tl_d_esram_o[10]
    DIRECTION OUTPUT ;
    USE SIGNAL ;
    ANTENNADIFFAREA 0.897600 ;
    PORT
      LAYER Metal2 ;
        RECT 334.880 499.440 335.440 500.000 ;
    END
  END tl_d_esram_o[10]
  PIN tl_d_esram_o[110]
    DIRECTION OUTPUT ;
    USE SIGNAL ;
    ANTENNADIFFAREA 0.897600 ;
    PORT
      LAYER Metal2 ;
        RECT 446.880 499.440 447.440 500.000 ;
    END
  END tl_d_esram_o[110]
  PIN tl_d_esram_o[111]
    DIRECTION OUTPUT ;
    USE SIGNAL ;
    ANTENNADIFFAREA 0.897600 ;
    PORT
      LAYER Metal2 ;
        RECT 448.000 499.440 448.560 500.000 ;
    END
  END tl_d_esram_o[111]
  PIN tl_d_esram_o[112]
    DIRECTION OUTPUT ;
    USE SIGNAL ;
    ANTENNADIFFAREA 0.897600 ;
    PORT
      LAYER Metal2 ;
        RECT 449.120 499.440 449.680 500.000 ;
    END
  END tl_d_esram_o[112]
  PIN tl_d_esram_o[113]
    DIRECTION OUTPUT ;
    USE SIGNAL ;
    ANTENNADIFFAREA 0.897600 ;
    PORT
      LAYER Metal2 ;
        RECT 450.240 499.440 450.800 500.000 ;
    END
  END tl_d_esram_o[113]
  PIN tl_d_esram_o[11]
    DIRECTION OUTPUT ;
    USE SIGNAL ;
    ANTENNADIFFAREA 0.897600 ;
    PORT
      LAYER Metal2 ;
        RECT 336.000 499.440 336.560 500.000 ;
    END
  END tl_d_esram_o[11]
  PIN tl_d_esram_o[12]
    DIRECTION OUTPUT ;
    USE SIGNAL ;
    ANTENNADIFFAREA 0.897600 ;
    PORT
      LAYER Metal2 ;
        RECT 337.120 499.440 337.680 500.000 ;
    END
  END tl_d_esram_o[12]
  PIN tl_d_esram_o[13]
    DIRECTION OUTPUT ;
    USE SIGNAL ;
    ANTENNADIFFAREA 0.897600 ;
    PORT
      LAYER Metal2 ;
        RECT 338.240 499.440 338.800 500.000 ;
    END
  END tl_d_esram_o[13]
  PIN tl_d_esram_o[14]
    DIRECTION OUTPUT ;
    USE SIGNAL ;
    ANTENNADIFFAREA 0.897600 ;
    PORT
      LAYER Metal2 ;
        RECT 339.360 499.440 339.920 500.000 ;
    END
  END tl_d_esram_o[14]
  PIN tl_d_esram_o[15]
    DIRECTION OUTPUT ;
    USE SIGNAL ;
    ANTENNADIFFAREA 0.897600 ;
    PORT
      LAYER Metal2 ;
        RECT 340.480 499.440 341.040 500.000 ;
    END
  END tl_d_esram_o[15]
  PIN tl_d_esram_o[16]
    DIRECTION OUTPUT ;
    USE SIGNAL ;
    ANTENNADIFFAREA 0.897600 ;
    PORT
      LAYER Metal2 ;
        RECT 341.600 499.440 342.160 500.000 ;
    END
  END tl_d_esram_o[16]
  PIN tl_d_esram_o[17]
    DIRECTION OUTPUT ;
    USE SIGNAL ;
    ANTENNADIFFAREA 0.897600 ;
    PORT
      LAYER Metal2 ;
        RECT 342.720 499.440 343.280 500.000 ;
    END
  END tl_d_esram_o[17]
  PIN tl_d_esram_o[18]
    DIRECTION OUTPUT ;
    USE SIGNAL ;
    ANTENNADIFFAREA 0.897600 ;
    PORT
      LAYER Metal2 ;
        RECT 343.840 499.440 344.400 500.000 ;
    END
  END tl_d_esram_o[18]
  PIN tl_d_esram_o[19]
    DIRECTION OUTPUT ;
    USE SIGNAL ;
    ANTENNADIFFAREA 0.897600 ;
    PORT
      LAYER Metal2 ;
        RECT 344.960 499.440 345.520 500.000 ;
    END
  END tl_d_esram_o[19]
  PIN tl_d_esram_o[1]
    DIRECTION OUTPUT ;
    USE SIGNAL ;
    ANTENNADIFFAREA 0.897600 ;
    PORT
      LAYER Metal2 ;
        RECT 324.800 499.440 325.360 500.000 ;
    END
  END tl_d_esram_o[1]
  PIN tl_d_esram_o[20]
    DIRECTION OUTPUT ;
    USE SIGNAL ;
    ANTENNADIFFAREA 0.897600 ;
    PORT
      LAYER Metal2 ;
        RECT 346.080 499.440 346.640 500.000 ;
    END
  END tl_d_esram_o[20]
  PIN tl_d_esram_o[21]
    DIRECTION OUTPUT ;
    USE SIGNAL ;
    ANTENNADIFFAREA 0.897600 ;
    PORT
      LAYER Metal2 ;
        RECT 347.200 499.440 347.760 500.000 ;
    END
  END tl_d_esram_o[21]
  PIN tl_d_esram_o[22]
    DIRECTION OUTPUT ;
    USE SIGNAL ;
    ANTENNADIFFAREA 0.897600 ;
    PORT
      LAYER Metal2 ;
        RECT 348.320 499.440 348.880 500.000 ;
    END
  END tl_d_esram_o[22]
  PIN tl_d_esram_o[23]
    DIRECTION OUTPUT ;
    USE SIGNAL ;
    ANTENNADIFFAREA 0.897600 ;
    PORT
      LAYER Metal2 ;
        RECT 349.440 499.440 350.000 500.000 ;
    END
  END tl_d_esram_o[23]
  PIN tl_d_esram_o[24]
    DIRECTION OUTPUT ;
    USE SIGNAL ;
    ANTENNADIFFAREA 0.897600 ;
    PORT
      LAYER Metal2 ;
        RECT 350.560 499.440 351.120 500.000 ;
    END
  END tl_d_esram_o[24]
  PIN tl_d_esram_o[25]
    DIRECTION OUTPUT ;
    USE SIGNAL ;
    ANTENNADIFFAREA 0.897600 ;
    PORT
      LAYER Metal2 ;
        RECT 351.680 499.440 352.240 500.000 ;
    END
  END tl_d_esram_o[25]
  PIN tl_d_esram_o[26]
    DIRECTION OUTPUT ;
    USE SIGNAL ;
    ANTENNADIFFAREA 0.897600 ;
    PORT
      LAYER Metal2 ;
        RECT 352.800 499.440 353.360 500.000 ;
    END
  END tl_d_esram_o[26]
  PIN tl_d_esram_o[27]
    DIRECTION OUTPUT ;
    USE SIGNAL ;
    ANTENNADIFFAREA 0.897600 ;
    PORT
      LAYER Metal2 ;
        RECT 353.920 499.440 354.480 500.000 ;
    END
  END tl_d_esram_o[27]
  PIN tl_d_esram_o[28]
    DIRECTION OUTPUT ;
    USE SIGNAL ;
    ANTENNADIFFAREA 0.897600 ;
    PORT
      LAYER Metal2 ;
        RECT 355.040 499.440 355.600 500.000 ;
    END
  END tl_d_esram_o[28]
  PIN tl_d_esram_o[29]
    DIRECTION OUTPUT ;
    USE SIGNAL ;
    ANTENNADIFFAREA 0.897600 ;
    PORT
      LAYER Metal2 ;
        RECT 356.160 499.440 356.720 500.000 ;
    END
  END tl_d_esram_o[29]
  PIN tl_d_esram_o[2]
    DIRECTION OUTPUT ;
    USE SIGNAL ;
    ANTENNADIFFAREA 0.897600 ;
    PORT
      LAYER Metal2 ;
        RECT 325.920 499.440 326.480 500.000 ;
    END
  END tl_d_esram_o[2]
  PIN tl_d_esram_o[30]
    DIRECTION OUTPUT ;
    USE SIGNAL ;
    ANTENNADIFFAREA 0.897600 ;
    PORT
      LAYER Metal2 ;
        RECT 357.280 499.440 357.840 500.000 ;
    END
  END tl_d_esram_o[30]
  PIN tl_d_esram_o[31]
    DIRECTION OUTPUT ;
    USE SIGNAL ;
    ANTENNADIFFAREA 0.897600 ;
    PORT
      LAYER Metal2 ;
        RECT 358.400 499.440 358.960 500.000 ;
    END
  END tl_d_esram_o[31]
  PIN tl_d_esram_o[32]
    DIRECTION OUTPUT ;
    USE SIGNAL ;
    ANTENNADIFFAREA 0.897600 ;
    PORT
      LAYER Metal2 ;
        RECT 359.520 499.440 360.080 500.000 ;
    END
  END tl_d_esram_o[32]
  PIN tl_d_esram_o[33]
    DIRECTION OUTPUT ;
    USE SIGNAL ;
    ANTENNADIFFAREA 0.897600 ;
    PORT
      LAYER Metal2 ;
        RECT 360.640 499.440 361.200 500.000 ;
    END
  END tl_d_esram_o[33]
  PIN tl_d_esram_o[34]
    DIRECTION OUTPUT ;
    USE SIGNAL ;
    ANTENNADIFFAREA 0.897600 ;
    PORT
      LAYER Metal2 ;
        RECT 361.760 499.440 362.320 500.000 ;
    END
  END tl_d_esram_o[34]
  PIN tl_d_esram_o[35]
    DIRECTION OUTPUT ;
    USE SIGNAL ;
    ANTENNADIFFAREA 0.897600 ;
    PORT
      LAYER Metal2 ;
        RECT 362.880 499.440 363.440 500.000 ;
    END
  END tl_d_esram_o[35]
  PIN tl_d_esram_o[36]
    DIRECTION OUTPUT ;
    USE SIGNAL ;
    ANTENNADIFFAREA 0.897600 ;
    PORT
      LAYER Metal2 ;
        RECT 364.000 499.440 364.560 500.000 ;
    END
  END tl_d_esram_o[36]
  PIN tl_d_esram_o[37]
    DIRECTION OUTPUT ;
    USE SIGNAL ;
    ANTENNADIFFAREA 0.897600 ;
    PORT
      LAYER Metal2 ;
        RECT 365.120 499.440 365.680 500.000 ;
    END
  END tl_d_esram_o[37]
  PIN tl_d_esram_o[38]
    DIRECTION OUTPUT ;
    USE SIGNAL ;
    ANTENNADIFFAREA 0.897600 ;
    PORT
      LAYER Metal2 ;
        RECT 366.240 499.440 366.800 500.000 ;
    END
  END tl_d_esram_o[38]
  PIN tl_d_esram_o[39]
    DIRECTION OUTPUT ;
    USE SIGNAL ;
    ANTENNADIFFAREA 0.897600 ;
    PORT
      LAYER Metal2 ;
        RECT 367.360 499.440 367.920 500.000 ;
    END
  END tl_d_esram_o[39]
  PIN tl_d_esram_o[3]
    DIRECTION OUTPUT ;
    USE SIGNAL ;
    ANTENNADIFFAREA 0.897600 ;
    PORT
      LAYER Metal2 ;
        RECT 327.040 499.440 327.600 500.000 ;
    END
  END tl_d_esram_o[3]
  PIN tl_d_esram_o[40]
    DIRECTION OUTPUT ;
    USE SIGNAL ;
    ANTENNADIFFAREA 0.897600 ;
    PORT
      LAYER Metal2 ;
        RECT 368.480 499.440 369.040 500.000 ;
    END
  END tl_d_esram_o[40]
  PIN tl_d_esram_o[41]
    DIRECTION OUTPUT ;
    USE SIGNAL ;
    ANTENNADIFFAREA 0.897600 ;
    PORT
      LAYER Metal2 ;
        RECT 369.600 499.440 370.160 500.000 ;
    END
  END tl_d_esram_o[41]
  PIN tl_d_esram_o[42]
    DIRECTION OUTPUT ;
    USE SIGNAL ;
    ANTENNADIFFAREA 0.897600 ;
    PORT
      LAYER Metal2 ;
        RECT 370.720 499.440 371.280 500.000 ;
    END
  END tl_d_esram_o[42]
  PIN tl_d_esram_o[43]
    DIRECTION OUTPUT ;
    USE SIGNAL ;
    ANTENNADIFFAREA 0.897600 ;
    PORT
      LAYER Metal2 ;
        RECT 371.840 499.440 372.400 500.000 ;
    END
  END tl_d_esram_o[43]
  PIN tl_d_esram_o[44]
    DIRECTION OUTPUT ;
    USE SIGNAL ;
    ANTENNADIFFAREA 0.897600 ;
    PORT
      LAYER Metal2 ;
        RECT 372.960 499.440 373.520 500.000 ;
    END
  END tl_d_esram_o[44]
  PIN tl_d_esram_o[45]
    DIRECTION OUTPUT ;
    USE SIGNAL ;
    ANTENNADIFFAREA 0.897600 ;
    PORT
      LAYER Metal2 ;
        RECT 374.080 499.440 374.640 500.000 ;
    END
  END tl_d_esram_o[45]
  PIN tl_d_esram_o[46]
    DIRECTION OUTPUT ;
    USE SIGNAL ;
    ANTENNADIFFAREA 0.897600 ;
    PORT
      LAYER Metal2 ;
        RECT 375.200 499.440 375.760 500.000 ;
    END
  END tl_d_esram_o[46]
  PIN tl_d_esram_o[47]
    DIRECTION OUTPUT ;
    USE SIGNAL ;
    ANTENNADIFFAREA 0.897600 ;
    PORT
      LAYER Metal2 ;
        RECT 376.320 499.440 376.880 500.000 ;
    END
  END tl_d_esram_o[47]
  PIN tl_d_esram_o[48]
    DIRECTION OUTPUT ;
    USE SIGNAL ;
    ANTENNADIFFAREA 0.897600 ;
    PORT
      LAYER Metal2 ;
        RECT 377.440 499.440 378.000 500.000 ;
    END
  END tl_d_esram_o[48]
  PIN tl_d_esram_o[49]
    DIRECTION OUTPUT ;
    USE SIGNAL ;
    ANTENNADIFFAREA 0.897600 ;
    PORT
      LAYER Metal2 ;
        RECT 378.560 499.440 379.120 500.000 ;
    END
  END tl_d_esram_o[49]
  PIN tl_d_esram_o[4]
    DIRECTION OUTPUT ;
    USE SIGNAL ;
    ANTENNADIFFAREA 0.897600 ;
    PORT
      LAYER Metal2 ;
        RECT 328.160 499.440 328.720 500.000 ;
    END
  END tl_d_esram_o[4]
  PIN tl_d_esram_o[50]
    DIRECTION OUTPUT ;
    USE SIGNAL ;
    ANTENNADIFFAREA 0.897600 ;
    PORT
      LAYER Metal2 ;
        RECT 379.680 499.440 380.240 500.000 ;
    END
  END tl_d_esram_o[50]
  PIN tl_d_esram_o[51]
    DIRECTION OUTPUT ;
    USE SIGNAL ;
    ANTENNADIFFAREA 0.897600 ;
    PORT
      LAYER Metal2 ;
        RECT 380.800 499.440 381.360 500.000 ;
    END
  END tl_d_esram_o[51]
  PIN tl_d_esram_o[52]
    DIRECTION OUTPUT ;
    USE SIGNAL ;
    ANTENNADIFFAREA 0.897600 ;
    PORT
      LAYER Metal2 ;
        RECT 381.920 499.440 382.480 500.000 ;
    END
  END tl_d_esram_o[52]
  PIN tl_d_esram_o[53]
    DIRECTION OUTPUT ;
    USE SIGNAL ;
    ANTENNADIFFAREA 0.897600 ;
    PORT
      LAYER Metal2 ;
        RECT 383.040 499.440 383.600 500.000 ;
    END
  END tl_d_esram_o[53]
  PIN tl_d_esram_o[54]
    DIRECTION OUTPUT ;
    USE SIGNAL ;
    ANTENNADIFFAREA 0.897600 ;
    PORT
      LAYER Metal2 ;
        RECT 384.160 499.440 384.720 500.000 ;
    END
  END tl_d_esram_o[54]
  PIN tl_d_esram_o[55]
    DIRECTION OUTPUT ;
    USE SIGNAL ;
    ANTENNADIFFAREA 0.897600 ;
    PORT
      LAYER Metal2 ;
        RECT 385.280 499.440 385.840 500.000 ;
    END
  END tl_d_esram_o[55]
  PIN tl_d_esram_o[56]
    DIRECTION OUTPUT ;
    USE SIGNAL ;
    ANTENNADIFFAREA 0.897600 ;
    PORT
      LAYER Metal2 ;
        RECT 386.400 499.440 386.960 500.000 ;
    END
  END tl_d_esram_o[56]
  PIN tl_d_esram_o[57]
    DIRECTION OUTPUT ;
    USE SIGNAL ;
    ANTENNADIFFAREA 0.897600 ;
    PORT
      LAYER Metal2 ;
        RECT 387.520 499.440 388.080 500.000 ;
    END
  END tl_d_esram_o[57]
  PIN tl_d_esram_o[58]
    DIRECTION OUTPUT ;
    USE SIGNAL ;
    ANTENNADIFFAREA 0.897600 ;
    PORT
      LAYER Metal2 ;
        RECT 388.640 499.440 389.200 500.000 ;
    END
  END tl_d_esram_o[58]
  PIN tl_d_esram_o[59]
    DIRECTION OUTPUT ;
    USE SIGNAL ;
    ANTENNADIFFAREA 0.897600 ;
    PORT
      LAYER Metal2 ;
        RECT 389.760 499.440 390.320 500.000 ;
    END
  END tl_d_esram_o[59]
  PIN tl_d_esram_o[5]
    DIRECTION OUTPUT ;
    USE SIGNAL ;
    ANTENNADIFFAREA 0.897600 ;
    PORT
      LAYER Metal2 ;
        RECT 329.280 499.440 329.840 500.000 ;
    END
  END tl_d_esram_o[5]
  PIN tl_d_esram_o[60]
    DIRECTION OUTPUT ;
    USE SIGNAL ;
    ANTENNADIFFAREA 0.897600 ;
    PORT
      LAYER Metal2 ;
        RECT 390.880 499.440 391.440 500.000 ;
    END
  END tl_d_esram_o[60]
  PIN tl_d_esram_o[61]
    DIRECTION OUTPUT ;
    USE SIGNAL ;
    ANTENNADIFFAREA 0.897600 ;
    PORT
      LAYER Metal2 ;
        RECT 392.000 499.440 392.560 500.000 ;
    END
  END tl_d_esram_o[61]
  PIN tl_d_esram_o[62]
    DIRECTION OUTPUT ;
    USE SIGNAL ;
    ANTENNADIFFAREA 0.897600 ;
    PORT
      LAYER Metal2 ;
        RECT 393.120 499.440 393.680 500.000 ;
    END
  END tl_d_esram_o[62]
  PIN tl_d_esram_o[63]
    DIRECTION OUTPUT ;
    USE SIGNAL ;
    ANTENNADIFFAREA 0.897600 ;
    PORT
      LAYER Metal2 ;
        RECT 394.240 499.440 394.800 500.000 ;
    END
  END tl_d_esram_o[63]
  PIN tl_d_esram_o[64]
    DIRECTION OUTPUT ;
    USE SIGNAL ;
    ANTENNADIFFAREA 0.897600 ;
    PORT
      LAYER Metal2 ;
        RECT 395.360 499.440 395.920 500.000 ;
    END
  END tl_d_esram_o[64]
  PIN tl_d_esram_o[65]
    DIRECTION OUTPUT ;
    USE SIGNAL ;
    ANTENNADIFFAREA 0.897600 ;
    PORT
      LAYER Metal2 ;
        RECT 396.480 499.440 397.040 500.000 ;
    END
  END tl_d_esram_o[65]
  PIN tl_d_esram_o[66]
    DIRECTION OUTPUT ;
    USE SIGNAL ;
    ANTENNADIFFAREA 0.897600 ;
    PORT
      LAYER Metal2 ;
        RECT 397.600 499.440 398.160 500.000 ;
    END
  END tl_d_esram_o[66]
  PIN tl_d_esram_o[67]
    DIRECTION OUTPUT ;
    USE SIGNAL ;
    ANTENNADIFFAREA 0.897600 ;
    PORT
      LAYER Metal2 ;
        RECT 398.720 499.440 399.280 500.000 ;
    END
  END tl_d_esram_o[67]
  PIN tl_d_esram_o[68]
    DIRECTION OUTPUT ;
    USE SIGNAL ;
    ANTENNADIFFAREA 0.897600 ;
    PORT
      LAYER Metal2 ;
        RECT 399.840 499.440 400.400 500.000 ;
    END
  END tl_d_esram_o[68]
  PIN tl_d_esram_o[69]
    DIRECTION OUTPUT ;
    USE SIGNAL ;
    ANTENNADIFFAREA 0.897600 ;
    PORT
      LAYER Metal2 ;
        RECT 400.960 499.440 401.520 500.000 ;
    END
  END tl_d_esram_o[69]
  PIN tl_d_esram_o[6]
    DIRECTION OUTPUT ;
    USE SIGNAL ;
    ANTENNADIFFAREA 0.897600 ;
    PORT
      LAYER Metal2 ;
        RECT 330.400 499.440 330.960 500.000 ;
    END
  END tl_d_esram_o[6]
  PIN tl_d_esram_o[70]
    DIRECTION OUTPUT ;
    USE SIGNAL ;
    ANTENNADIFFAREA 0.897600 ;
    PORT
      LAYER Metal2 ;
        RECT 402.080 499.440 402.640 500.000 ;
    END
  END tl_d_esram_o[70]
  PIN tl_d_esram_o[71]
    DIRECTION OUTPUT ;
    USE SIGNAL ;
    ANTENNADIFFAREA 0.897600 ;
    PORT
      LAYER Metal2 ;
        RECT 403.200 499.440 403.760 500.000 ;
    END
  END tl_d_esram_o[71]
  PIN tl_d_esram_o[72]
    DIRECTION OUTPUT ;
    USE SIGNAL ;
    ANTENNADIFFAREA 0.897600 ;
    PORT
      LAYER Metal2 ;
        RECT 404.320 499.440 404.880 500.000 ;
    END
  END tl_d_esram_o[72]
  PIN tl_d_esram_o[73]
    DIRECTION OUTPUT ;
    USE SIGNAL ;
    ANTENNADIFFAREA 0.897600 ;
    PORT
      LAYER Metal2 ;
        RECT 405.440 499.440 406.000 500.000 ;
    END
  END tl_d_esram_o[73]
  PIN tl_d_esram_o[74]
    DIRECTION OUTPUT ;
    USE SIGNAL ;
    ANTENNADIFFAREA 0.897600 ;
    PORT
      LAYER Metal2 ;
        RECT 406.560 499.440 407.120 500.000 ;
    END
  END tl_d_esram_o[74]
  PIN tl_d_esram_o[75]
    DIRECTION OUTPUT ;
    USE SIGNAL ;
    ANTENNADIFFAREA 0.897600 ;
    PORT
      LAYER Metal2 ;
        RECT 407.680 499.440 408.240 500.000 ;
    END
  END tl_d_esram_o[75]
  PIN tl_d_esram_o[76]
    DIRECTION OUTPUT ;
    USE SIGNAL ;
    ANTENNADIFFAREA 0.897600 ;
    PORT
      LAYER Metal2 ;
        RECT 408.800 499.440 409.360 500.000 ;
    END
  END tl_d_esram_o[76]
  PIN tl_d_esram_o[77]
    DIRECTION OUTPUT ;
    USE SIGNAL ;
    ANTENNADIFFAREA 0.897600 ;
    PORT
      LAYER Metal2 ;
        RECT 409.920 499.440 410.480 500.000 ;
    END
  END tl_d_esram_o[77]
  PIN tl_d_esram_o[78]
    DIRECTION OUTPUT ;
    USE SIGNAL ;
    ANTENNADIFFAREA 0.897600 ;
    PORT
      LAYER Metal2 ;
        RECT 411.040 499.440 411.600 500.000 ;
    END
  END tl_d_esram_o[78]
  PIN tl_d_esram_o[79]
    DIRECTION OUTPUT ;
    USE SIGNAL ;
    ANTENNADIFFAREA 0.897600 ;
    PORT
      LAYER Metal2 ;
        RECT 412.160 499.440 412.720 500.000 ;
    END
  END tl_d_esram_o[79]
  PIN tl_d_esram_o[7]
    DIRECTION OUTPUT ;
    USE SIGNAL ;
    ANTENNADIFFAREA 0.897600 ;
    PORT
      LAYER Metal2 ;
        RECT 331.520 499.440 332.080 500.000 ;
    END
  END tl_d_esram_o[7]
  PIN tl_d_esram_o[80]
    DIRECTION OUTPUT ;
    USE SIGNAL ;
    ANTENNADIFFAREA 0.897600 ;
    PORT
      LAYER Metal2 ;
        RECT 413.280 499.440 413.840 500.000 ;
    END
  END tl_d_esram_o[80]
  PIN tl_d_esram_o[81]
    DIRECTION OUTPUT ;
    USE SIGNAL ;
    ANTENNADIFFAREA 0.897600 ;
    PORT
      LAYER Metal2 ;
        RECT 414.400 499.440 414.960 500.000 ;
    END
  END tl_d_esram_o[81]
  PIN tl_d_esram_o[82]
    DIRECTION OUTPUT ;
    USE SIGNAL ;
    ANTENNADIFFAREA 0.360800 ;
    PORT
      LAYER Metal2 ;
        RECT 415.520 499.440 416.080 500.000 ;
    END
  END tl_d_esram_o[82]
  PIN tl_d_esram_o[83]
    DIRECTION OUTPUT ;
    USE SIGNAL ;
    ANTENNADIFFAREA 0.360800 ;
    PORT
      LAYER Metal2 ;
        RECT 416.640 499.440 417.200 500.000 ;
    END
  END tl_d_esram_o[83]
  PIN tl_d_esram_o[84]
    DIRECTION OUTPUT ;
    USE SIGNAL ;
    ANTENNADIFFAREA 0.360800 ;
    PORT
      LAYER Metal2 ;
        RECT 417.760 499.440 418.320 500.000 ;
    END
  END tl_d_esram_o[84]
  PIN tl_d_esram_o[85]
    DIRECTION OUTPUT ;
    USE SIGNAL ;
    ANTENNADIFFAREA 0.360800 ;
    PORT
      LAYER Metal2 ;
        RECT 418.880 499.440 419.440 500.000 ;
    END
  END tl_d_esram_o[85]
  PIN tl_d_esram_o[86]
    DIRECTION OUTPUT ;
    USE SIGNAL ;
    ANTENNADIFFAREA 0.360800 ;
    PORT
      LAYER Metal2 ;
        RECT 420.000 499.440 420.560 500.000 ;
    END
  END tl_d_esram_o[86]
  PIN tl_d_esram_o[87]
    DIRECTION OUTPUT ;
    USE SIGNAL ;
    ANTENNADIFFAREA 0.360800 ;
    PORT
      LAYER Metal2 ;
        RECT 421.120 499.440 421.680 500.000 ;
    END
  END tl_d_esram_o[87]
  PIN tl_d_esram_o[88]
    DIRECTION OUTPUT ;
    USE SIGNAL ;
    ANTENNADIFFAREA 0.360800 ;
    PORT
      LAYER Metal2 ;
        RECT 422.240 499.440 422.800 500.000 ;
    END
  END tl_d_esram_o[88]
  PIN tl_d_esram_o[89]
    DIRECTION OUTPUT ;
    USE SIGNAL ;
    ANTENNADIFFAREA 0.360800 ;
    PORT
      LAYER Metal2 ;
        RECT 423.360 499.440 423.920 500.000 ;
    END
  END tl_d_esram_o[89]
  PIN tl_d_esram_o[8]
    DIRECTION OUTPUT ;
    USE SIGNAL ;
    ANTENNADIFFAREA 0.897600 ;
    PORT
      LAYER Metal2 ;
        RECT 332.640 499.440 333.200 500.000 ;
    END
  END tl_d_esram_o[8]
  PIN tl_d_esram_o[90]
    DIRECTION OUTPUT ;
    USE SIGNAL ;
    ANTENNADIFFAREA 0.360800 ;
    PORT
      LAYER Metal2 ;
        RECT 424.480 499.440 425.040 500.000 ;
    END
  END tl_d_esram_o[90]
  PIN tl_d_esram_o[91]
    DIRECTION OUTPUT ;
    USE SIGNAL ;
    ANTENNADIFFAREA 0.360800 ;
    PORT
      LAYER Metal2 ;
        RECT 425.600 499.440 426.160 500.000 ;
    END
  END tl_d_esram_o[91]
  PIN tl_d_esram_o[92]
    DIRECTION OUTPUT ;
    USE SIGNAL ;
    ANTENNADIFFAREA 0.360800 ;
    PORT
      LAYER Metal2 ;
        RECT 426.720 499.440 427.280 500.000 ;
    END
  END tl_d_esram_o[92]
  PIN tl_d_esram_o[93]
    DIRECTION OUTPUT ;
    USE SIGNAL ;
    ANTENNADIFFAREA 0.360800 ;
    PORT
      LAYER Metal2 ;
        RECT 427.840 499.440 428.400 500.000 ;
    END
  END tl_d_esram_o[93]
  PIN tl_d_esram_o[94]
    DIRECTION OUTPUT ;
    USE SIGNAL ;
    ANTENNADIFFAREA 0.360800 ;
    PORT
      LAYER Metal2 ;
        RECT 428.960 499.440 429.520 500.000 ;
    END
  END tl_d_esram_o[94]
  PIN tl_d_esram_o[95]
    DIRECTION OUTPUT ;
    USE SIGNAL ;
    ANTENNADIFFAREA 0.360800 ;
    PORT
      LAYER Metal2 ;
        RECT 430.080 499.440 430.640 500.000 ;
    END
  END tl_d_esram_o[95]
  PIN tl_d_esram_o[96]
    DIRECTION OUTPUT ;
    USE SIGNAL ;
    ANTENNADIFFAREA 0.360800 ;
    PORT
      LAYER Metal2 ;
        RECT 431.200 499.440 431.760 500.000 ;
    END
  END tl_d_esram_o[96]
  PIN tl_d_esram_o[97]
    DIRECTION OUTPUT ;
    USE SIGNAL ;
    ANTENNADIFFAREA 0.897600 ;
    PORT
      LAYER Metal2 ;
        RECT 432.320 499.440 432.880 500.000 ;
    END
  END tl_d_esram_o[97]
  PIN tl_d_esram_o[98]
    DIRECTION OUTPUT ;
    USE SIGNAL ;
    ANTENNADIFFAREA 0.897600 ;
    PORT
      LAYER Metal2 ;
        RECT 433.440 499.440 434.000 500.000 ;
    END
  END tl_d_esram_o[98]
  PIN tl_d_esram_o[99]
    DIRECTION OUTPUT ;
    USE SIGNAL ;
    ANTENNADIFFAREA 0.897600 ;
    PORT
      LAYER Metal2 ;
        RECT 434.560 499.440 435.120 500.000 ;
    END
  END tl_d_esram_o[99]
  PIN tl_d_esram_o[9]
    DIRECTION OUTPUT ;
    USE SIGNAL ;
    ANTENNADIFFAREA 0.897600 ;
    PORT
      LAYER Metal2 ;
        RECT 333.760 499.440 334.320 500.000 ;
    END
  END tl_d_esram_o[9]
  PIN tl_d_rom_i[0]
    DIRECTION INPUT ;
    USE SIGNAL ;
    ANTENNAGATEAREA 0.396000 ;
    PORT
      LAYER Metal2 ;
        RECT 48.160 499.440 48.720 500.000 ;
    END
  END tl_d_rom_i[0]
  PIN tl_d_rom_i[10]
    DIRECTION INPUT ;
    USE SIGNAL ;
    ANTENNAGATEAREA 0.396000 ;
    PORT
      LAYER Metal2 ;
        RECT 59.360 499.440 59.920 500.000 ;
    END
  END tl_d_rom_i[10]
  PIN tl_d_rom_i[11]
    DIRECTION INPUT ;
    USE SIGNAL ;
    ANTENNAGATEAREA 0.396000 ;
    PORT
      LAYER Metal2 ;
        RECT 60.480 499.440 61.040 500.000 ;
    END
  END tl_d_rom_i[11]
  PIN tl_d_rom_i[12]
    DIRECTION INPUT ;
    USE SIGNAL ;
    ANTENNAGATEAREA 0.396000 ;
    PORT
      LAYER Metal2 ;
        RECT 61.600 499.440 62.160 500.000 ;
    END
  END tl_d_rom_i[12]
  PIN tl_d_rom_i[13]
    DIRECTION INPUT ;
    USE SIGNAL ;
    ANTENNAGATEAREA 0.396000 ;
    PORT
      LAYER Metal2 ;
        RECT 62.720 499.440 63.280 500.000 ;
    END
  END tl_d_rom_i[13]
  PIN tl_d_rom_i[14]
    DIRECTION INPUT ;
    USE SIGNAL ;
    ANTENNAGATEAREA 0.396000 ;
    PORT
      LAYER Metal2 ;
        RECT 63.840 499.440 64.400 500.000 ;
    END
  END tl_d_rom_i[14]
  PIN tl_d_rom_i[15]
    DIRECTION INPUT ;
    USE SIGNAL ;
    ANTENNAGATEAREA 0.396000 ;
    PORT
      LAYER Metal2 ;
        RECT 64.960 499.440 65.520 500.000 ;
    END
  END tl_d_rom_i[15]
  PIN tl_d_rom_i[16]
    DIRECTION INPUT ;
    USE SIGNAL ;
    ANTENNAGATEAREA 0.396000 ;
    PORT
      LAYER Metal2 ;
        RECT 66.080 499.440 66.640 500.000 ;
    END
  END tl_d_rom_i[16]
  PIN tl_d_rom_i[17]
    DIRECTION INPUT ;
    USE SIGNAL ;
    ANTENNAGATEAREA 0.396000 ;
    PORT
      LAYER Metal2 ;
        RECT 67.200 499.440 67.760 500.000 ;
    END
  END tl_d_rom_i[17]
  PIN tl_d_rom_i[18]
    DIRECTION INPUT ;
    USE SIGNAL ;
    ANTENNAGATEAREA 0.396000 ;
    PORT
      LAYER Metal2 ;
        RECT 68.320 499.440 68.880 500.000 ;
    END
  END tl_d_rom_i[18]
  PIN tl_d_rom_i[19]
    DIRECTION INPUT ;
    USE SIGNAL ;
    ANTENNAGATEAREA 0.396000 ;
    PORT
      LAYER Metal2 ;
        RECT 69.440 499.440 70.000 500.000 ;
    END
  END tl_d_rom_i[19]
  PIN tl_d_rom_i[1]
    DIRECTION INPUT ;
    USE SIGNAL ;
    ANTENNAGATEAREA 0.396000 ;
    PORT
      LAYER Metal2 ;
        RECT 49.280 499.440 49.840 500.000 ;
    END
  END tl_d_rom_i[1]
  PIN tl_d_rom_i[20]
    DIRECTION INPUT ;
    USE SIGNAL ;
    ANTENNAGATEAREA 0.396000 ;
    PORT
      LAYER Metal2 ;
        RECT 70.560 499.440 71.120 500.000 ;
    END
  END tl_d_rom_i[20]
  PIN tl_d_rom_i[21]
    DIRECTION INPUT ;
    USE SIGNAL ;
    ANTENNAGATEAREA 0.396000 ;
    PORT
      LAYER Metal2 ;
        RECT 71.680 499.440 72.240 500.000 ;
    END
  END tl_d_rom_i[21]
  PIN tl_d_rom_i[22]
    DIRECTION INPUT ;
    USE SIGNAL ;
    ANTENNAGATEAREA 0.396000 ;
    PORT
      LAYER Metal2 ;
        RECT 72.800 499.440 73.360 500.000 ;
    END
  END tl_d_rom_i[22]
  PIN tl_d_rom_i[23]
    DIRECTION INPUT ;
    USE SIGNAL ;
    ANTENNAGATEAREA 0.396000 ;
    PORT
      LAYER Metal2 ;
        RECT 73.920 499.440 74.480 500.000 ;
    END
  END tl_d_rom_i[23]
  PIN tl_d_rom_i[24]
    DIRECTION INPUT ;
    USE SIGNAL ;
    ANTENNAGATEAREA 0.396000 ;
    PORT
      LAYER Metal2 ;
        RECT 75.040 499.440 75.600 500.000 ;
    END
  END tl_d_rom_i[24]
  PIN tl_d_rom_i[25]
    DIRECTION INPUT ;
    USE SIGNAL ;
    ANTENNAGATEAREA 0.396000 ;
    PORT
      LAYER Metal2 ;
        RECT 76.160 499.440 76.720 500.000 ;
    END
  END tl_d_rom_i[25]
  PIN tl_d_rom_i[26]
    DIRECTION INPUT ;
    USE SIGNAL ;
    ANTENNAGATEAREA 0.396000 ;
    PORT
      LAYER Metal2 ;
        RECT 77.280 499.440 77.840 500.000 ;
    END
  END tl_d_rom_i[26]
  PIN tl_d_rom_i[27]
    DIRECTION INPUT ;
    USE SIGNAL ;
    ANTENNAGATEAREA 0.396000 ;
    PORT
      LAYER Metal2 ;
        RECT 78.400 499.440 78.960 500.000 ;
    END
  END tl_d_rom_i[27]
  PIN tl_d_rom_i[28]
    DIRECTION INPUT ;
    USE SIGNAL ;
    ANTENNAGATEAREA 0.396000 ;
    PORT
      LAYER Metal2 ;
        RECT 79.520 499.440 80.080 500.000 ;
    END
  END tl_d_rom_i[28]
  PIN tl_d_rom_i[29]
    DIRECTION INPUT ;
    USE SIGNAL ;
    ANTENNAGATEAREA 0.396000 ;
    PORT
      LAYER Metal2 ;
        RECT 80.640 499.440 81.200 500.000 ;
    END
  END tl_d_rom_i[29]
  PIN tl_d_rom_i[2]
    DIRECTION INPUT ;
    USE SIGNAL ;
    ANTENNAGATEAREA 0.396000 ;
    PORT
      LAYER Metal2 ;
        RECT 50.400 499.440 50.960 500.000 ;
    END
  END tl_d_rom_i[2]
  PIN tl_d_rom_i[30]
    DIRECTION INPUT ;
    USE SIGNAL ;
    ANTENNAGATEAREA 0.396000 ;
    PORT
      LAYER Metal2 ;
        RECT 81.760 499.440 82.320 500.000 ;
    END
  END tl_d_rom_i[30]
  PIN tl_d_rom_i[31]
    DIRECTION INPUT ;
    USE SIGNAL ;
    ANTENNAGATEAREA 0.396000 ;
    PORT
      LAYER Metal2 ;
        RECT 82.880 499.440 83.440 500.000 ;
    END
  END tl_d_rom_i[31]
  PIN tl_d_rom_i[32]
    DIRECTION INPUT ;
    USE SIGNAL ;
    ANTENNAGATEAREA 0.396000 ;
    PORT
      LAYER Metal2 ;
        RECT 84.000 499.440 84.560 500.000 ;
    END
  END tl_d_rom_i[32]
  PIN tl_d_rom_i[33]
    DIRECTION INPUT ;
    USE SIGNAL ;
    ANTENNAGATEAREA 0.396000 ;
    PORT
      LAYER Metal2 ;
        RECT 85.120 499.440 85.680 500.000 ;
    END
  END tl_d_rom_i[33]
  PIN tl_d_rom_i[34]
    DIRECTION INPUT ;
    USE SIGNAL ;
    ANTENNAGATEAREA 0.396000 ;
    PORT
      LAYER Metal2 ;
        RECT 86.240 499.440 86.800 500.000 ;
    END
  END tl_d_rom_i[34]
  PIN tl_d_rom_i[35]
    DIRECTION INPUT ;
    USE SIGNAL ;
    ANTENNAGATEAREA 0.396000 ;
    PORT
      LAYER Metal2 ;
        RECT 87.360 499.440 87.920 500.000 ;
    END
  END tl_d_rom_i[35]
  PIN tl_d_rom_i[36]
    DIRECTION INPUT ;
    USE SIGNAL ;
    ANTENNAGATEAREA 0.396000 ;
    PORT
      LAYER Metal2 ;
        RECT 88.480 499.440 89.040 500.000 ;
    END
  END tl_d_rom_i[36]
  PIN tl_d_rom_i[37]
    DIRECTION INPUT ;
    USE SIGNAL ;
    ANTENNAGATEAREA 0.396000 ;
    PORT
      LAYER Metal2 ;
        RECT 89.600 499.440 90.160 500.000 ;
    END
  END tl_d_rom_i[37]
  PIN tl_d_rom_i[38]
    DIRECTION INPUT ;
    USE SIGNAL ;
    ANTENNAGATEAREA 0.396000 ;
    PORT
      LAYER Metal2 ;
        RECT 90.720 499.440 91.280 500.000 ;
    END
  END tl_d_rom_i[38]
  PIN tl_d_rom_i[39]
    DIRECTION INPUT ;
    USE SIGNAL ;
    ANTENNAGATEAREA 0.396000 ;
    PORT
      LAYER Metal2 ;
        RECT 91.840 499.440 92.400 500.000 ;
    END
  END tl_d_rom_i[39]
  PIN tl_d_rom_i[3]
    DIRECTION INPUT ;
    USE SIGNAL ;
    ANTENNAGATEAREA 0.396000 ;
    PORT
      LAYER Metal2 ;
        RECT 51.520 499.440 52.080 500.000 ;
    END
  END tl_d_rom_i[3]
  PIN tl_d_rom_i[40]
    DIRECTION INPUT ;
    USE SIGNAL ;
    ANTENNAGATEAREA 0.396000 ;
    PORT
      LAYER Metal2 ;
        RECT 92.960 499.440 93.520 500.000 ;
    END
  END tl_d_rom_i[40]
  PIN tl_d_rom_i[41]
    DIRECTION INPUT ;
    USE SIGNAL ;
    ANTENNAGATEAREA 0.396000 ;
    PORT
      LAYER Metal2 ;
        RECT 94.080 499.440 94.640 500.000 ;
    END
  END tl_d_rom_i[41]
  PIN tl_d_rom_i[42]
    DIRECTION INPUT ;
    USE SIGNAL ;
    ANTENNAGATEAREA 0.396000 ;
    PORT
      LAYER Metal2 ;
        RECT 95.200 499.440 95.760 500.000 ;
    END
  END tl_d_rom_i[42]
  PIN tl_d_rom_i[43]
    DIRECTION INPUT ;
    USE SIGNAL ;
    ANTENNAGATEAREA 0.396000 ;
    PORT
      LAYER Metal2 ;
        RECT 96.320 499.440 96.880 500.000 ;
    END
  END tl_d_rom_i[43]
  PIN tl_d_rom_i[44]
    DIRECTION INPUT ;
    USE SIGNAL ;
    ANTENNAGATEAREA 0.396000 ;
    PORT
      LAYER Metal2 ;
        RECT 97.440 499.440 98.000 500.000 ;
    END
  END tl_d_rom_i[44]
  PIN tl_d_rom_i[45]
    DIRECTION INPUT ;
    USE SIGNAL ;
    ANTENNAGATEAREA 0.396000 ;
    PORT
      LAYER Metal2 ;
        RECT 98.560 499.440 99.120 500.000 ;
    END
  END tl_d_rom_i[45]
  PIN tl_d_rom_i[46]
    DIRECTION INPUT ;
    USE SIGNAL ;
    ANTENNAGATEAREA 0.396000 ;
    PORT
      LAYER Metal2 ;
        RECT 99.680 499.440 100.240 500.000 ;
    END
  END tl_d_rom_i[46]
  PIN tl_d_rom_i[47]
    DIRECTION INPUT ;
    USE SIGNAL ;
    ANTENNAGATEAREA 0.396000 ;
    PORT
      LAYER Metal2 ;
        RECT 100.800 499.440 101.360 500.000 ;
    END
  END tl_d_rom_i[47]
  PIN tl_d_rom_i[48]
    DIRECTION INPUT ;
    USE SIGNAL ;
    ANTENNAGATEAREA 0.396000 ;
    PORT
      LAYER Metal2 ;
        RECT 101.920 499.440 102.480 500.000 ;
    END
  END tl_d_rom_i[48]
  PIN tl_d_rom_i[49]
    DIRECTION INPUT ;
    USE SIGNAL ;
    ANTENNAGATEAREA 0.396000 ;
    PORT
      LAYER Metal2 ;
        RECT 103.040 499.440 103.600 500.000 ;
    END
  END tl_d_rom_i[49]
  PIN tl_d_rom_i[4]
    DIRECTION INPUT ;
    USE SIGNAL ;
    ANTENNAGATEAREA 0.396000 ;
    PORT
      LAYER Metal2 ;
        RECT 52.640 499.440 53.200 500.000 ;
    END
  END tl_d_rom_i[4]
  PIN tl_d_rom_i[50]
    DIRECTION INPUT ;
    USE SIGNAL ;
    ANTENNAGATEAREA 0.396000 ;
    PORT
      LAYER Metal2 ;
        RECT 104.160 499.440 104.720 500.000 ;
    END
  END tl_d_rom_i[50]
  PIN tl_d_rom_i[51]
    DIRECTION INPUT ;
    USE SIGNAL ;
    ANTENNAGATEAREA 0.396000 ;
    PORT
      LAYER Metal2 ;
        RECT 105.280 499.440 105.840 500.000 ;
    END
  END tl_d_rom_i[51]
  PIN tl_d_rom_i[52]
    DIRECTION INPUT ;
    USE SIGNAL ;
    ANTENNAGATEAREA 0.396000 ;
    PORT
      LAYER Metal2 ;
        RECT 106.400 499.440 106.960 500.000 ;
    END
  END tl_d_rom_i[52]
  PIN tl_d_rom_i[53]
    DIRECTION INPUT ;
    USE SIGNAL ;
    ANTENNAGATEAREA 0.396000 ;
    PORT
      LAYER Metal2 ;
        RECT 107.520 499.440 108.080 500.000 ;
    END
  END tl_d_rom_i[53]
  PIN tl_d_rom_i[54]
    DIRECTION INPUT ;
    USE SIGNAL ;
    ANTENNAGATEAREA 0.396000 ;
    PORT
      LAYER Metal2 ;
        RECT 108.640 499.440 109.200 500.000 ;
    END
  END tl_d_rom_i[54]
  PIN tl_d_rom_i[55]
    DIRECTION INPUT ;
    USE SIGNAL ;
    ANTENNAGATEAREA 0.396000 ;
    PORT
      LAYER Metal2 ;
        RECT 109.760 499.440 110.320 500.000 ;
    END
  END tl_d_rom_i[55]
  PIN tl_d_rom_i[56]
    DIRECTION INPUT ;
    USE SIGNAL ;
    ANTENNAGATEAREA 0.396000 ;
    PORT
      LAYER Metal2 ;
        RECT 110.880 499.440 111.440 500.000 ;
    END
  END tl_d_rom_i[56]
  PIN tl_d_rom_i[57]
    DIRECTION INPUT ;
    USE SIGNAL ;
    ANTENNAGATEAREA 0.396000 ;
    PORT
      LAYER Metal2 ;
        RECT 112.000 499.440 112.560 500.000 ;
    END
  END tl_d_rom_i[57]
  PIN tl_d_rom_i[58]
    DIRECTION INPUT ;
    USE SIGNAL ;
    ANTENNAGATEAREA 0.396000 ;
    PORT
      LAYER Metal2 ;
        RECT 113.120 499.440 113.680 500.000 ;
    END
  END tl_d_rom_i[58]
  PIN tl_d_rom_i[59]
    DIRECTION INPUT ;
    USE SIGNAL ;
    ANTENNAGATEAREA 0.396000 ;
    PORT
      LAYER Metal2 ;
        RECT 114.240 499.440 114.800 500.000 ;
    END
  END tl_d_rom_i[59]
  PIN tl_d_rom_i[5]
    DIRECTION INPUT ;
    USE SIGNAL ;
    ANTENNAGATEAREA 0.396000 ;
    PORT
      LAYER Metal2 ;
        RECT 53.760 499.440 54.320 500.000 ;
    END
  END tl_d_rom_i[5]
  PIN tl_d_rom_i[60]
    DIRECTION INPUT ;
    USE SIGNAL ;
    ANTENNAGATEAREA 0.396000 ;
    PORT
      LAYER Metal2 ;
        RECT 115.360 499.440 115.920 500.000 ;
    END
  END tl_d_rom_i[60]
  PIN tl_d_rom_i[61]
    DIRECTION INPUT ;
    USE SIGNAL ;
    ANTENNAGATEAREA 0.396000 ;
    PORT
      LAYER Metal2 ;
        RECT 116.480 499.440 117.040 500.000 ;
    END
  END tl_d_rom_i[61]
  PIN tl_d_rom_i[62]
    DIRECTION INPUT ;
    USE SIGNAL ;
    ANTENNAGATEAREA 0.396000 ;
    PORT
      LAYER Metal2 ;
        RECT 117.600 499.440 118.160 500.000 ;
    END
  END tl_d_rom_i[62]
  PIN tl_d_rom_i[63]
    DIRECTION INPUT ;
    USE SIGNAL ;
    ANTENNAGATEAREA 0.396000 ;
    PORT
      LAYER Metal2 ;
        RECT 118.720 499.440 119.280 500.000 ;
    END
  END tl_d_rom_i[63]
  PIN tl_d_rom_i[64]
    DIRECTION INPUT ;
    USE SIGNAL ;
    ANTENNAGATEAREA 0.396000 ;
    PORT
      LAYER Metal2 ;
        RECT 119.840 499.440 120.400 500.000 ;
    END
  END tl_d_rom_i[64]
  PIN tl_d_rom_i[65]
    DIRECTION INPUT ;
    USE SIGNAL ;
    ANTENNAGATEAREA 0.396000 ;
    PORT
      LAYER Metal2 ;
        RECT 120.960 499.440 121.520 500.000 ;
    END
  END tl_d_rom_i[65]
  PIN tl_d_rom_i[6]
    DIRECTION INPUT ;
    USE SIGNAL ;
    ANTENNAGATEAREA 0.396000 ;
    PORT
      LAYER Metal2 ;
        RECT 54.880 499.440 55.440 500.000 ;
    END
  END tl_d_rom_i[6]
  PIN tl_d_rom_i[7]
    DIRECTION INPUT ;
    USE SIGNAL ;
    ANTENNAGATEAREA 0.396000 ;
    PORT
      LAYER Metal2 ;
        RECT 56.000 499.440 56.560 500.000 ;
    END
  END tl_d_rom_i[7]
  PIN tl_d_rom_i[8]
    DIRECTION INPUT ;
    USE SIGNAL ;
    ANTENNAGATEAREA 0.396000 ;
    PORT
      LAYER Metal2 ;
        RECT 57.120 499.440 57.680 500.000 ;
    END
  END tl_d_rom_i[8]
  PIN tl_d_rom_i[9]
    DIRECTION INPUT ;
    USE SIGNAL ;
    ANTENNAGATEAREA 0.396000 ;
    PORT
      LAYER Metal2 ;
        RECT 58.240 499.440 58.800 500.000 ;
    END
  END tl_d_rom_i[9]
  PIN tl_d_rom_o[0]
    DIRECTION OUTPUT ;
    USE SIGNAL ;
    ANTENNADIFFAREA 0.897600 ;
    PORT
      LAYER Metal2 ;
        RECT 122.080 499.440 122.640 500.000 ;
    END
  END tl_d_rom_o[0]
  PIN tl_d_rom_o[100]
    DIRECTION OUTPUT ;
    USE SIGNAL ;
    ANTENNADIFFAREA 0.897600 ;
    PORT
      LAYER Metal2 ;
        RECT 234.080 499.440 234.640 500.000 ;
    END
  END tl_d_rom_o[100]
  PIN tl_d_rom_o[101]
    DIRECTION OUTPUT ;
    USE SIGNAL ;
    ANTENNADIFFAREA 0.897600 ;
    PORT
      LAYER Metal2 ;
        RECT 235.200 499.440 235.760 500.000 ;
    END
  END tl_d_rom_o[101]
  PIN tl_d_rom_o[102]
    DIRECTION OUTPUT ;
    USE SIGNAL ;
    ANTENNADIFFAREA 0.897600 ;
    PORT
      LAYER Metal2 ;
        RECT 236.320 499.440 236.880 500.000 ;
    END
  END tl_d_rom_o[102]
  PIN tl_d_rom_o[103]
    DIRECTION OUTPUT ;
    USE SIGNAL ;
    ANTENNADIFFAREA 0.897600 ;
    PORT
      LAYER Metal2 ;
        RECT 237.440 499.440 238.000 500.000 ;
    END
  END tl_d_rom_o[103]
  PIN tl_d_rom_o[104]
    DIRECTION OUTPUT ;
    USE SIGNAL ;
    ANTENNADIFFAREA 0.897600 ;
    PORT
      LAYER Metal2 ;
        RECT 238.560 499.440 239.120 500.000 ;
    END
  END tl_d_rom_o[104]
  PIN tl_d_rom_o[105]
    DIRECTION OUTPUT ;
    USE SIGNAL ;
    ANTENNADIFFAREA 0.897600 ;
    PORT
      LAYER Metal2 ;
        RECT 239.680 499.440 240.240 500.000 ;
    END
  END tl_d_rom_o[105]
  PIN tl_d_rom_o[106]
    DIRECTION OUTPUT ;
    USE SIGNAL ;
    ANTENNADIFFAREA 0.897600 ;
    PORT
      LAYER Metal2 ;
        RECT 240.800 499.440 241.360 500.000 ;
    END
  END tl_d_rom_o[106]
  PIN tl_d_rom_o[107]
    DIRECTION OUTPUT ;
    USE SIGNAL ;
    ANTENNADIFFAREA 0.897600 ;
    PORT
      LAYER Metal2 ;
        RECT 241.920 499.440 242.480 500.000 ;
    END
  END tl_d_rom_o[107]
  PIN tl_d_rom_o[108]
    DIRECTION OUTPUT ;
    USE SIGNAL ;
    ANTENNADIFFAREA 0.897600 ;
    PORT
      LAYER Metal2 ;
        RECT 243.040 499.440 243.600 500.000 ;
    END
  END tl_d_rom_o[108]
  PIN tl_d_rom_o[109]
    DIRECTION OUTPUT ;
    USE SIGNAL ;
    ANTENNADIFFAREA 0.897600 ;
    PORT
      LAYER Metal2 ;
        RECT 244.160 499.440 244.720 500.000 ;
    END
  END tl_d_rom_o[109]
  PIN tl_d_rom_o[10]
    DIRECTION OUTPUT ;
    USE SIGNAL ;
    ANTENNADIFFAREA 0.897600 ;
    PORT
      LAYER Metal2 ;
        RECT 133.280 499.440 133.840 500.000 ;
    END
  END tl_d_rom_o[10]
  PIN tl_d_rom_o[110]
    DIRECTION OUTPUT ;
    USE SIGNAL ;
    ANTENNADIFFAREA 0.897600 ;
    PORT
      LAYER Metal2 ;
        RECT 245.280 499.440 245.840 500.000 ;
    END
  END tl_d_rom_o[110]
  PIN tl_d_rom_o[111]
    DIRECTION OUTPUT ;
    USE SIGNAL ;
    ANTENNADIFFAREA 0.897600 ;
    PORT
      LAYER Metal2 ;
        RECT 246.400 499.440 246.960 500.000 ;
    END
  END tl_d_rom_o[111]
  PIN tl_d_rom_o[112]
    DIRECTION OUTPUT ;
    USE SIGNAL ;
    ANTENNADIFFAREA 0.897600 ;
    PORT
      LAYER Metal2 ;
        RECT 247.520 499.440 248.080 500.000 ;
    END
  END tl_d_rom_o[112]
  PIN tl_d_rom_o[113]
    DIRECTION OUTPUT ;
    USE SIGNAL ;
    ANTENNADIFFAREA 0.897600 ;
    PORT
      LAYER Metal2 ;
        RECT 248.640 499.440 249.200 500.000 ;
    END
  END tl_d_rom_o[113]
  PIN tl_d_rom_o[11]
    DIRECTION OUTPUT ;
    USE SIGNAL ;
    ANTENNADIFFAREA 0.897600 ;
    PORT
      LAYER Metal2 ;
        RECT 134.400 499.440 134.960 500.000 ;
    END
  END tl_d_rom_o[11]
  PIN tl_d_rom_o[12]
    DIRECTION OUTPUT ;
    USE SIGNAL ;
    ANTENNADIFFAREA 0.897600 ;
    PORT
      LAYER Metal2 ;
        RECT 135.520 499.440 136.080 500.000 ;
    END
  END tl_d_rom_o[12]
  PIN tl_d_rom_o[13]
    DIRECTION OUTPUT ;
    USE SIGNAL ;
    ANTENNADIFFAREA 0.897600 ;
    PORT
      LAYER Metal2 ;
        RECT 136.640 499.440 137.200 500.000 ;
    END
  END tl_d_rom_o[13]
  PIN tl_d_rom_o[14]
    DIRECTION OUTPUT ;
    USE SIGNAL ;
    ANTENNADIFFAREA 0.897600 ;
    PORT
      LAYER Metal2 ;
        RECT 137.760 499.440 138.320 500.000 ;
    END
  END tl_d_rom_o[14]
  PIN tl_d_rom_o[15]
    DIRECTION OUTPUT ;
    USE SIGNAL ;
    ANTENNADIFFAREA 0.897600 ;
    PORT
      LAYER Metal2 ;
        RECT 138.880 499.440 139.440 500.000 ;
    END
  END tl_d_rom_o[15]
  PIN tl_d_rom_o[16]
    DIRECTION OUTPUT ;
    USE SIGNAL ;
    ANTENNADIFFAREA 0.897600 ;
    PORT
      LAYER Metal2 ;
        RECT 140.000 499.440 140.560 500.000 ;
    END
  END tl_d_rom_o[16]
  PIN tl_d_rom_o[17]
    DIRECTION OUTPUT ;
    USE SIGNAL ;
    ANTENNADIFFAREA 0.897600 ;
    PORT
      LAYER Metal2 ;
        RECT 141.120 499.440 141.680 500.000 ;
    END
  END tl_d_rom_o[17]
  PIN tl_d_rom_o[18]
    DIRECTION OUTPUT ;
    USE SIGNAL ;
    ANTENNADIFFAREA 0.897600 ;
    PORT
      LAYER Metal2 ;
        RECT 142.240 499.440 142.800 500.000 ;
    END
  END tl_d_rom_o[18]
  PIN tl_d_rom_o[19]
    DIRECTION OUTPUT ;
    USE SIGNAL ;
    ANTENNADIFFAREA 0.897600 ;
    PORT
      LAYER Metal2 ;
        RECT 143.360 499.440 143.920 500.000 ;
    END
  END tl_d_rom_o[19]
  PIN tl_d_rom_o[1]
    DIRECTION OUTPUT ;
    USE SIGNAL ;
    ANTENNADIFFAREA 0.897600 ;
    PORT
      LAYER Metal2 ;
        RECT 123.200 499.440 123.760 500.000 ;
    END
  END tl_d_rom_o[1]
  PIN tl_d_rom_o[20]
    DIRECTION OUTPUT ;
    USE SIGNAL ;
    ANTENNADIFFAREA 0.897600 ;
    PORT
      LAYER Metal2 ;
        RECT 144.480 499.440 145.040 500.000 ;
    END
  END tl_d_rom_o[20]
  PIN tl_d_rom_o[21]
    DIRECTION OUTPUT ;
    USE SIGNAL ;
    ANTENNADIFFAREA 0.897600 ;
    PORT
      LAYER Metal2 ;
        RECT 145.600 499.440 146.160 500.000 ;
    END
  END tl_d_rom_o[21]
  PIN tl_d_rom_o[22]
    DIRECTION OUTPUT ;
    USE SIGNAL ;
    ANTENNADIFFAREA 0.897600 ;
    PORT
      LAYER Metal2 ;
        RECT 146.720 499.440 147.280 500.000 ;
    END
  END tl_d_rom_o[22]
  PIN tl_d_rom_o[23]
    DIRECTION OUTPUT ;
    USE SIGNAL ;
    ANTENNADIFFAREA 0.897600 ;
    PORT
      LAYER Metal2 ;
        RECT 147.840 499.440 148.400 500.000 ;
    END
  END tl_d_rom_o[23]
  PIN tl_d_rom_o[24]
    DIRECTION OUTPUT ;
    USE SIGNAL ;
    ANTENNADIFFAREA 0.897600 ;
    PORT
      LAYER Metal2 ;
        RECT 148.960 499.440 149.520 500.000 ;
    END
  END tl_d_rom_o[24]
  PIN tl_d_rom_o[25]
    DIRECTION OUTPUT ;
    USE SIGNAL ;
    ANTENNADIFFAREA 0.897600 ;
    PORT
      LAYER Metal2 ;
        RECT 150.080 499.440 150.640 500.000 ;
    END
  END tl_d_rom_o[25]
  PIN tl_d_rom_o[26]
    DIRECTION OUTPUT ;
    USE SIGNAL ;
    ANTENNADIFFAREA 0.897600 ;
    PORT
      LAYER Metal2 ;
        RECT 151.200 499.440 151.760 500.000 ;
    END
  END tl_d_rom_o[26]
  PIN tl_d_rom_o[27]
    DIRECTION OUTPUT ;
    USE SIGNAL ;
    ANTENNADIFFAREA 0.897600 ;
    PORT
      LAYER Metal2 ;
        RECT 152.320 499.440 152.880 500.000 ;
    END
  END tl_d_rom_o[27]
  PIN tl_d_rom_o[28]
    DIRECTION OUTPUT ;
    USE SIGNAL ;
    ANTENNADIFFAREA 0.897600 ;
    PORT
      LAYER Metal2 ;
        RECT 153.440 499.440 154.000 500.000 ;
    END
  END tl_d_rom_o[28]
  PIN tl_d_rom_o[29]
    DIRECTION OUTPUT ;
    USE SIGNAL ;
    ANTENNADIFFAREA 0.897600 ;
    PORT
      LAYER Metal2 ;
        RECT 154.560 499.440 155.120 500.000 ;
    END
  END tl_d_rom_o[29]
  PIN tl_d_rom_o[2]
    DIRECTION OUTPUT ;
    USE SIGNAL ;
    ANTENNADIFFAREA 0.897600 ;
    PORT
      LAYER Metal2 ;
        RECT 124.320 499.440 124.880 500.000 ;
    END
  END tl_d_rom_o[2]
  PIN tl_d_rom_o[30]
    DIRECTION OUTPUT ;
    USE SIGNAL ;
    ANTENNADIFFAREA 0.897600 ;
    PORT
      LAYER Metal2 ;
        RECT 155.680 499.440 156.240 500.000 ;
    END
  END tl_d_rom_o[30]
  PIN tl_d_rom_o[31]
    DIRECTION OUTPUT ;
    USE SIGNAL ;
    ANTENNADIFFAREA 0.897600 ;
    PORT
      LAYER Metal2 ;
        RECT 156.800 499.440 157.360 500.000 ;
    END
  END tl_d_rom_o[31]
  PIN tl_d_rom_o[32]
    DIRECTION OUTPUT ;
    USE SIGNAL ;
    ANTENNADIFFAREA 0.897600 ;
    PORT
      LAYER Metal2 ;
        RECT 157.920 499.440 158.480 500.000 ;
    END
  END tl_d_rom_o[32]
  PIN tl_d_rom_o[33]
    DIRECTION OUTPUT ;
    USE SIGNAL ;
    ANTENNADIFFAREA 0.897600 ;
    PORT
      LAYER Metal2 ;
        RECT 159.040 499.440 159.600 500.000 ;
    END
  END tl_d_rom_o[33]
  PIN tl_d_rom_o[34]
    DIRECTION OUTPUT ;
    USE SIGNAL ;
    ANTENNADIFFAREA 0.897600 ;
    PORT
      LAYER Metal2 ;
        RECT 160.160 499.440 160.720 500.000 ;
    END
  END tl_d_rom_o[34]
  PIN tl_d_rom_o[35]
    DIRECTION OUTPUT ;
    USE SIGNAL ;
    ANTENNADIFFAREA 0.897600 ;
    PORT
      LAYER Metal2 ;
        RECT 161.280 499.440 161.840 500.000 ;
    END
  END tl_d_rom_o[35]
  PIN tl_d_rom_o[36]
    DIRECTION OUTPUT ;
    USE SIGNAL ;
    ANTENNADIFFAREA 0.897600 ;
    PORT
      LAYER Metal2 ;
        RECT 162.400 499.440 162.960 500.000 ;
    END
  END tl_d_rom_o[36]
  PIN tl_d_rom_o[37]
    DIRECTION OUTPUT ;
    USE SIGNAL ;
    ANTENNADIFFAREA 0.897600 ;
    PORT
      LAYER Metal2 ;
        RECT 163.520 499.440 164.080 500.000 ;
    END
  END tl_d_rom_o[37]
  PIN tl_d_rom_o[38]
    DIRECTION OUTPUT ;
    USE SIGNAL ;
    ANTENNADIFFAREA 0.897600 ;
    PORT
      LAYER Metal2 ;
        RECT 164.640 499.440 165.200 500.000 ;
    END
  END tl_d_rom_o[38]
  PIN tl_d_rom_o[39]
    DIRECTION OUTPUT ;
    USE SIGNAL ;
    ANTENNADIFFAREA 0.897600 ;
    PORT
      LAYER Metal2 ;
        RECT 165.760 499.440 166.320 500.000 ;
    END
  END tl_d_rom_o[39]
  PIN tl_d_rom_o[3]
    DIRECTION OUTPUT ;
    USE SIGNAL ;
    ANTENNADIFFAREA 0.897600 ;
    PORT
      LAYER Metal2 ;
        RECT 125.440 499.440 126.000 500.000 ;
    END
  END tl_d_rom_o[3]
  PIN tl_d_rom_o[40]
    DIRECTION OUTPUT ;
    USE SIGNAL ;
    ANTENNADIFFAREA 0.897600 ;
    PORT
      LAYER Metal2 ;
        RECT 166.880 499.440 167.440 500.000 ;
    END
  END tl_d_rom_o[40]
  PIN tl_d_rom_o[41]
    DIRECTION OUTPUT ;
    USE SIGNAL ;
    ANTENNADIFFAREA 0.897600 ;
    PORT
      LAYER Metal2 ;
        RECT 168.000 499.440 168.560 500.000 ;
    END
  END tl_d_rom_o[41]
  PIN tl_d_rom_o[42]
    DIRECTION OUTPUT ;
    USE SIGNAL ;
    ANTENNADIFFAREA 0.897600 ;
    PORT
      LAYER Metal2 ;
        RECT 169.120 499.440 169.680 500.000 ;
    END
  END tl_d_rom_o[42]
  PIN tl_d_rom_o[43]
    DIRECTION OUTPUT ;
    USE SIGNAL ;
    ANTENNADIFFAREA 0.897600 ;
    PORT
      LAYER Metal2 ;
        RECT 170.240 499.440 170.800 500.000 ;
    END
  END tl_d_rom_o[43]
  PIN tl_d_rom_o[44]
    DIRECTION OUTPUT ;
    USE SIGNAL ;
    ANTENNADIFFAREA 0.897600 ;
    PORT
      LAYER Metal2 ;
        RECT 171.360 499.440 171.920 500.000 ;
    END
  END tl_d_rom_o[44]
  PIN tl_d_rom_o[45]
    DIRECTION OUTPUT ;
    USE SIGNAL ;
    ANTENNADIFFAREA 0.897600 ;
    PORT
      LAYER Metal2 ;
        RECT 172.480 499.440 173.040 500.000 ;
    END
  END tl_d_rom_o[45]
  PIN tl_d_rom_o[46]
    DIRECTION OUTPUT ;
    USE SIGNAL ;
    ANTENNADIFFAREA 0.897600 ;
    PORT
      LAYER Metal2 ;
        RECT 173.600 499.440 174.160 500.000 ;
    END
  END tl_d_rom_o[46]
  PIN tl_d_rom_o[47]
    DIRECTION OUTPUT ;
    USE SIGNAL ;
    ANTENNADIFFAREA 0.897600 ;
    PORT
      LAYER Metal2 ;
        RECT 174.720 499.440 175.280 500.000 ;
    END
  END tl_d_rom_o[47]
  PIN tl_d_rom_o[48]
    DIRECTION OUTPUT ;
    USE SIGNAL ;
    ANTENNADIFFAREA 0.897600 ;
    PORT
      LAYER Metal2 ;
        RECT 175.840 499.440 176.400 500.000 ;
    END
  END tl_d_rom_o[48]
  PIN tl_d_rom_o[49]
    DIRECTION OUTPUT ;
    USE SIGNAL ;
    ANTENNADIFFAREA 0.897600 ;
    PORT
      LAYER Metal2 ;
        RECT 176.960 499.440 177.520 500.000 ;
    END
  END tl_d_rom_o[49]
  PIN tl_d_rom_o[4]
    DIRECTION OUTPUT ;
    USE SIGNAL ;
    ANTENNADIFFAREA 0.897600 ;
    PORT
      LAYER Metal2 ;
        RECT 126.560 499.440 127.120 500.000 ;
    END
  END tl_d_rom_o[4]
  PIN tl_d_rom_o[50]
    DIRECTION OUTPUT ;
    USE SIGNAL ;
    ANTENNADIFFAREA 0.897600 ;
    PORT
      LAYER Metal2 ;
        RECT 178.080 499.440 178.640 500.000 ;
    END
  END tl_d_rom_o[50]
  PIN tl_d_rom_o[51]
    DIRECTION OUTPUT ;
    USE SIGNAL ;
    ANTENNADIFFAREA 0.897600 ;
    PORT
      LAYER Metal2 ;
        RECT 179.200 499.440 179.760 500.000 ;
    END
  END tl_d_rom_o[51]
  PIN tl_d_rom_o[52]
    DIRECTION OUTPUT ;
    USE SIGNAL ;
    ANTENNADIFFAREA 0.897600 ;
    PORT
      LAYER Metal2 ;
        RECT 180.320 499.440 180.880 500.000 ;
    END
  END tl_d_rom_o[52]
  PIN tl_d_rom_o[53]
    DIRECTION OUTPUT ;
    USE SIGNAL ;
    ANTENNADIFFAREA 0.897600 ;
    PORT
      LAYER Metal2 ;
        RECT 181.440 499.440 182.000 500.000 ;
    END
  END tl_d_rom_o[53]
  PIN tl_d_rom_o[54]
    DIRECTION OUTPUT ;
    USE SIGNAL ;
    ANTENNADIFFAREA 0.897600 ;
    PORT
      LAYER Metal2 ;
        RECT 182.560 499.440 183.120 500.000 ;
    END
  END tl_d_rom_o[54]
  PIN tl_d_rom_o[55]
    DIRECTION OUTPUT ;
    USE SIGNAL ;
    ANTENNADIFFAREA 0.897600 ;
    PORT
      LAYER Metal2 ;
        RECT 183.680 499.440 184.240 500.000 ;
    END
  END tl_d_rom_o[55]
  PIN tl_d_rom_o[56]
    DIRECTION OUTPUT ;
    USE SIGNAL ;
    ANTENNADIFFAREA 0.897600 ;
    PORT
      LAYER Metal2 ;
        RECT 184.800 499.440 185.360 500.000 ;
    END
  END tl_d_rom_o[56]
  PIN tl_d_rom_o[57]
    DIRECTION OUTPUT ;
    USE SIGNAL ;
    ANTENNADIFFAREA 0.897600 ;
    PORT
      LAYER Metal2 ;
        RECT 185.920 499.440 186.480 500.000 ;
    END
  END tl_d_rom_o[57]
  PIN tl_d_rom_o[58]
    DIRECTION OUTPUT ;
    USE SIGNAL ;
    ANTENNADIFFAREA 0.897600 ;
    PORT
      LAYER Metal2 ;
        RECT 187.040 499.440 187.600 500.000 ;
    END
  END tl_d_rom_o[58]
  PIN tl_d_rom_o[59]
    DIRECTION OUTPUT ;
    USE SIGNAL ;
    ANTENNADIFFAREA 0.897600 ;
    PORT
      LAYER Metal2 ;
        RECT 188.160 499.440 188.720 500.000 ;
    END
  END tl_d_rom_o[59]
  PIN tl_d_rom_o[5]
    DIRECTION OUTPUT ;
    USE SIGNAL ;
    ANTENNADIFFAREA 0.897600 ;
    PORT
      LAYER Metal2 ;
        RECT 127.680 499.440 128.240 500.000 ;
    END
  END tl_d_rom_o[5]
  PIN tl_d_rom_o[60]
    DIRECTION OUTPUT ;
    USE SIGNAL ;
    ANTENNADIFFAREA 0.897600 ;
    PORT
      LAYER Metal2 ;
        RECT 189.280 499.440 189.840 500.000 ;
    END
  END tl_d_rom_o[60]
  PIN tl_d_rom_o[61]
    DIRECTION OUTPUT ;
    USE SIGNAL ;
    ANTENNADIFFAREA 0.897600 ;
    PORT
      LAYER Metal2 ;
        RECT 190.400 499.440 190.960 500.000 ;
    END
  END tl_d_rom_o[61]
  PIN tl_d_rom_o[62]
    DIRECTION OUTPUT ;
    USE SIGNAL ;
    ANTENNADIFFAREA 0.897600 ;
    PORT
      LAYER Metal2 ;
        RECT 191.520 499.440 192.080 500.000 ;
    END
  END tl_d_rom_o[62]
  PIN tl_d_rom_o[63]
    DIRECTION OUTPUT ;
    USE SIGNAL ;
    ANTENNADIFFAREA 0.897600 ;
    PORT
      LAYER Metal2 ;
        RECT 192.640 499.440 193.200 500.000 ;
    END
  END tl_d_rom_o[63]
  PIN tl_d_rom_o[64]
    DIRECTION OUTPUT ;
    USE SIGNAL ;
    ANTENNADIFFAREA 0.897600 ;
    PORT
      LAYER Metal2 ;
        RECT 193.760 499.440 194.320 500.000 ;
    END
  END tl_d_rom_o[64]
  PIN tl_d_rom_o[65]
    DIRECTION OUTPUT ;
    USE SIGNAL ;
    ANTENNADIFFAREA 0.897600 ;
    PORT
      LAYER Metal2 ;
        RECT 194.880 499.440 195.440 500.000 ;
    END
  END tl_d_rom_o[65]
  PIN tl_d_rom_o[66]
    DIRECTION OUTPUT ;
    USE SIGNAL ;
    ANTENNADIFFAREA 0.897600 ;
    PORT
      LAYER Metal2 ;
        RECT 196.000 499.440 196.560 500.000 ;
    END
  END tl_d_rom_o[66]
  PIN tl_d_rom_o[67]
    DIRECTION OUTPUT ;
    USE SIGNAL ;
    ANTENNADIFFAREA 0.897600 ;
    PORT
      LAYER Metal2 ;
        RECT 197.120 499.440 197.680 500.000 ;
    END
  END tl_d_rom_o[67]
  PIN tl_d_rom_o[68]
    DIRECTION OUTPUT ;
    USE SIGNAL ;
    ANTENNADIFFAREA 0.897600 ;
    PORT
      LAYER Metal2 ;
        RECT 198.240 499.440 198.800 500.000 ;
    END
  END tl_d_rom_o[68]
  PIN tl_d_rom_o[69]
    DIRECTION OUTPUT ;
    USE SIGNAL ;
    ANTENNADIFFAREA 0.897600 ;
    PORT
      LAYER Metal2 ;
        RECT 199.360 499.440 199.920 500.000 ;
    END
  END tl_d_rom_o[69]
  PIN tl_d_rom_o[6]
    DIRECTION OUTPUT ;
    USE SIGNAL ;
    ANTENNADIFFAREA 0.897600 ;
    PORT
      LAYER Metal2 ;
        RECT 128.800 499.440 129.360 500.000 ;
    END
  END tl_d_rom_o[6]
  PIN tl_d_rom_o[70]
    DIRECTION OUTPUT ;
    USE SIGNAL ;
    ANTENNADIFFAREA 0.897600 ;
    PORT
      LAYER Metal2 ;
        RECT 200.480 499.440 201.040 500.000 ;
    END
  END tl_d_rom_o[70]
  PIN tl_d_rom_o[71]
    DIRECTION OUTPUT ;
    USE SIGNAL ;
    ANTENNADIFFAREA 0.897600 ;
    PORT
      LAYER Metal2 ;
        RECT 201.600 499.440 202.160 500.000 ;
    END
  END tl_d_rom_o[71]
  PIN tl_d_rom_o[72]
    DIRECTION OUTPUT ;
    USE SIGNAL ;
    ANTENNADIFFAREA 0.897600 ;
    PORT
      LAYER Metal2 ;
        RECT 202.720 499.440 203.280 500.000 ;
    END
  END tl_d_rom_o[72]
  PIN tl_d_rom_o[73]
    DIRECTION OUTPUT ;
    USE SIGNAL ;
    ANTENNADIFFAREA 0.897600 ;
    PORT
      LAYER Metal2 ;
        RECT 203.840 499.440 204.400 500.000 ;
    END
  END tl_d_rom_o[73]
  PIN tl_d_rom_o[74]
    DIRECTION OUTPUT ;
    USE SIGNAL ;
    ANTENNADIFFAREA 0.897600 ;
    PORT
      LAYER Metal2 ;
        RECT 204.960 499.440 205.520 500.000 ;
    END
  END tl_d_rom_o[74]
  PIN tl_d_rom_o[75]
    DIRECTION OUTPUT ;
    USE SIGNAL ;
    ANTENNADIFFAREA 0.897600 ;
    PORT
      LAYER Metal2 ;
        RECT 206.080 499.440 206.640 500.000 ;
    END
  END tl_d_rom_o[75]
  PIN tl_d_rom_o[76]
    DIRECTION OUTPUT ;
    USE SIGNAL ;
    ANTENNADIFFAREA 0.897600 ;
    PORT
      LAYER Metal2 ;
        RECT 207.200 499.440 207.760 500.000 ;
    END
  END tl_d_rom_o[76]
  PIN tl_d_rom_o[77]
    DIRECTION OUTPUT ;
    USE SIGNAL ;
    ANTENNADIFFAREA 0.897600 ;
    PORT
      LAYER Metal2 ;
        RECT 208.320 499.440 208.880 500.000 ;
    END
  END tl_d_rom_o[77]
  PIN tl_d_rom_o[78]
    DIRECTION OUTPUT ;
    USE SIGNAL ;
    ANTENNADIFFAREA 0.897600 ;
    PORT
      LAYER Metal2 ;
        RECT 209.440 499.440 210.000 500.000 ;
    END
  END tl_d_rom_o[78]
  PIN tl_d_rom_o[79]
    DIRECTION OUTPUT ;
    USE SIGNAL ;
    ANTENNADIFFAREA 0.897600 ;
    PORT
      LAYER Metal2 ;
        RECT 210.560 499.440 211.120 500.000 ;
    END
  END tl_d_rom_o[79]
  PIN tl_d_rom_o[7]
    DIRECTION OUTPUT ;
    USE SIGNAL ;
    ANTENNADIFFAREA 0.897600 ;
    PORT
      LAYER Metal2 ;
        RECT 129.920 499.440 130.480 500.000 ;
    END
  END tl_d_rom_o[7]
  PIN tl_d_rom_o[80]
    DIRECTION OUTPUT ;
    USE SIGNAL ;
    ANTENNADIFFAREA 0.897600 ;
    PORT
      LAYER Metal2 ;
        RECT 211.680 499.440 212.240 500.000 ;
    END
  END tl_d_rom_o[80]
  PIN tl_d_rom_o[81]
    DIRECTION OUTPUT ;
    USE SIGNAL ;
    ANTENNADIFFAREA 0.360800 ;
    PORT
      LAYER Metal2 ;
        RECT 212.800 499.440 213.360 500.000 ;
    END
  END tl_d_rom_o[81]
  PIN tl_d_rom_o[82]
    DIRECTION OUTPUT ;
    USE SIGNAL ;
    ANTENNADIFFAREA 0.360800 ;
    PORT
      LAYER Metal2 ;
        RECT 213.920 499.440 214.480 500.000 ;
    END
  END tl_d_rom_o[82]
  PIN tl_d_rom_o[83]
    DIRECTION OUTPUT ;
    USE SIGNAL ;
    ANTENNADIFFAREA 0.360800 ;
    PORT
      LAYER Metal2 ;
        RECT 215.040 499.440 215.600 500.000 ;
    END
  END tl_d_rom_o[83]
  PIN tl_d_rom_o[84]
    DIRECTION OUTPUT ;
    USE SIGNAL ;
    ANTENNADIFFAREA 0.360800 ;
    PORT
      LAYER Metal2 ;
        RECT 216.160 499.440 216.720 500.000 ;
    END
  END tl_d_rom_o[84]
  PIN tl_d_rom_o[85]
    DIRECTION OUTPUT ;
    USE SIGNAL ;
    ANTENNADIFFAREA 0.360800 ;
    PORT
      LAYER Metal2 ;
        RECT 217.280 499.440 217.840 500.000 ;
    END
  END tl_d_rom_o[85]
  PIN tl_d_rom_o[86]
    DIRECTION OUTPUT ;
    USE SIGNAL ;
    ANTENNADIFFAREA 0.360800 ;
    PORT
      LAYER Metal2 ;
        RECT 218.400 499.440 218.960 500.000 ;
    END
  END tl_d_rom_o[86]
  PIN tl_d_rom_o[87]
    DIRECTION OUTPUT ;
    USE SIGNAL ;
    ANTENNADIFFAREA 0.360800 ;
    PORT
      LAYER Metal2 ;
        RECT 219.520 499.440 220.080 500.000 ;
    END
  END tl_d_rom_o[87]
  PIN tl_d_rom_o[88]
    DIRECTION OUTPUT ;
    USE SIGNAL ;
    ANTENNADIFFAREA 0.360800 ;
    PORT
      LAYER Metal2 ;
        RECT 220.640 499.440 221.200 500.000 ;
    END
  END tl_d_rom_o[88]
  PIN tl_d_rom_o[89]
    DIRECTION OUTPUT ;
    USE SIGNAL ;
    ANTENNADIFFAREA 0.360800 ;
    PORT
      LAYER Metal2 ;
        RECT 221.760 499.440 222.320 500.000 ;
    END
  END tl_d_rom_o[89]
  PIN tl_d_rom_o[8]
    DIRECTION OUTPUT ;
    USE SIGNAL ;
    ANTENNADIFFAREA 0.897600 ;
    PORT
      LAYER Metal2 ;
        RECT 131.040 499.440 131.600 500.000 ;
    END
  END tl_d_rom_o[8]
  PIN tl_d_rom_o[90]
    DIRECTION OUTPUT ;
    USE SIGNAL ;
    ANTENNADIFFAREA 0.360800 ;
    PORT
      LAYER Metal2 ;
        RECT 222.880 499.440 223.440 500.000 ;
    END
  END tl_d_rom_o[90]
  PIN tl_d_rom_o[91]
    DIRECTION OUTPUT ;
    USE SIGNAL ;
    ANTENNADIFFAREA 0.360800 ;
    PORT
      LAYER Metal2 ;
        RECT 224.000 499.440 224.560 500.000 ;
    END
  END tl_d_rom_o[91]
  PIN tl_d_rom_o[92]
    DIRECTION OUTPUT ;
    USE SIGNAL ;
    ANTENNADIFFAREA 0.360800 ;
    PORT
      LAYER Metal2 ;
        RECT 225.120 499.440 225.680 500.000 ;
    END
  END tl_d_rom_o[92]
  PIN tl_d_rom_o[93]
    DIRECTION OUTPUT ;
    USE SIGNAL ;
    ANTENNADIFFAREA 0.360800 ;
    PORT
      LAYER Metal2 ;
        RECT 226.240 499.440 226.800 500.000 ;
    END
  END tl_d_rom_o[93]
  PIN tl_d_rom_o[94]
    DIRECTION OUTPUT ;
    USE SIGNAL ;
    ANTENNADIFFAREA 0.360800 ;
    PORT
      LAYER Metal2 ;
        RECT 227.360 499.440 227.920 500.000 ;
    END
  END tl_d_rom_o[94]
  PIN tl_d_rom_o[95]
    DIRECTION OUTPUT ;
    USE SIGNAL ;
    ANTENNADIFFAREA 0.360800 ;
    PORT
      LAYER Metal2 ;
        RECT 228.480 499.440 229.040 500.000 ;
    END
  END tl_d_rom_o[95]
  PIN tl_d_rom_o[96]
    DIRECTION OUTPUT ;
    USE SIGNAL ;
    ANTENNADIFFAREA 0.360800 ;
    PORT
      LAYER Metal2 ;
        RECT 229.600 499.440 230.160 500.000 ;
    END
  END tl_d_rom_o[96]
  PIN tl_d_rom_o[97]
    DIRECTION OUTPUT ;
    USE SIGNAL ;
    ANTENNADIFFAREA 0.897600 ;
    PORT
      LAYER Metal2 ;
        RECT 230.720 499.440 231.280 500.000 ;
    END
  END tl_d_rom_o[97]
  PIN tl_d_rom_o[98]
    DIRECTION OUTPUT ;
    USE SIGNAL ;
    ANTENNADIFFAREA 0.897600 ;
    PORT
      LAYER Metal2 ;
        RECT 231.840 499.440 232.400 500.000 ;
    END
  END tl_d_rom_o[98]
  PIN tl_d_rom_o[99]
    DIRECTION OUTPUT ;
    USE SIGNAL ;
    ANTENNADIFFAREA 0.897600 ;
    PORT
      LAYER Metal2 ;
        RECT 232.960 499.440 233.520 500.000 ;
    END
  END tl_d_rom_o[99]
  PIN tl_d_rom_o[9]
    DIRECTION OUTPUT ;
    USE SIGNAL ;
    ANTENNADIFFAREA 0.897600 ;
    PORT
      LAYER Metal2 ;
        RECT 132.160 499.440 132.720 500.000 ;
    END
  END tl_d_rom_o[9]
  PIN tl_d_uart_i[0]
    DIRECTION INPUT ;
    USE SIGNAL ;
    ANTENNAGATEAREA 0.396000 ;
    PORT
      LAYER Metal3 ;
        RECT 499.440 49.280 500.000 49.840 ;
    END
  END tl_d_uart_i[0]
  PIN tl_d_uart_i[10]
    DIRECTION INPUT ;
    USE SIGNAL ;
    ANTENNAGATEAREA 0.396000 ;
    PORT
      LAYER Metal3 ;
        RECT 499.440 71.680 500.000 72.240 ;
    END
  END tl_d_uart_i[10]
  PIN tl_d_uart_i[11]
    DIRECTION INPUT ;
    USE SIGNAL ;
    ANTENNAGATEAREA 0.396000 ;
    PORT
      LAYER Metal3 ;
        RECT 499.440 73.920 500.000 74.480 ;
    END
  END tl_d_uart_i[11]
  PIN tl_d_uart_i[12]
    DIRECTION INPUT ;
    USE SIGNAL ;
    ANTENNAGATEAREA 0.396000 ;
    PORT
      LAYER Metal3 ;
        RECT 499.440 76.160 500.000 76.720 ;
    END
  END tl_d_uart_i[12]
  PIN tl_d_uart_i[13]
    DIRECTION INPUT ;
    USE SIGNAL ;
    ANTENNAGATEAREA 0.396000 ;
    PORT
      LAYER Metal3 ;
        RECT 499.440 78.400 500.000 78.960 ;
    END
  END tl_d_uart_i[13]
  PIN tl_d_uart_i[14]
    DIRECTION INPUT ;
    USE SIGNAL ;
    ANTENNAGATEAREA 0.396000 ;
    PORT
      LAYER Metal3 ;
        RECT 499.440 80.640 500.000 81.200 ;
    END
  END tl_d_uart_i[14]
  PIN tl_d_uart_i[15]
    DIRECTION INPUT ;
    USE SIGNAL ;
    ANTENNAGATEAREA 0.396000 ;
    PORT
      LAYER Metal3 ;
        RECT 499.440 82.880 500.000 83.440 ;
    END
  END tl_d_uart_i[15]
  PIN tl_d_uart_i[16]
    DIRECTION INPUT ;
    USE SIGNAL ;
    ANTENNAGATEAREA 0.396000 ;
    PORT
      LAYER Metal3 ;
        RECT 499.440 85.120 500.000 85.680 ;
    END
  END tl_d_uart_i[16]
  PIN tl_d_uart_i[17]
    DIRECTION INPUT ;
    USE SIGNAL ;
    ANTENNAGATEAREA 0.396000 ;
    PORT
      LAYER Metal3 ;
        RECT 499.440 87.360 500.000 87.920 ;
    END
  END tl_d_uart_i[17]
  PIN tl_d_uart_i[18]
    DIRECTION INPUT ;
    USE SIGNAL ;
    ANTENNAGATEAREA 0.396000 ;
    PORT
      LAYER Metal3 ;
        RECT 499.440 89.600 500.000 90.160 ;
    END
  END tl_d_uart_i[18]
  PIN tl_d_uart_i[19]
    DIRECTION INPUT ;
    USE SIGNAL ;
    ANTENNAGATEAREA 0.396000 ;
    PORT
      LAYER Metal3 ;
        RECT 499.440 91.840 500.000 92.400 ;
    END
  END tl_d_uart_i[19]
  PIN tl_d_uart_i[1]
    DIRECTION INPUT ;
    USE SIGNAL ;
    ANTENNAGATEAREA 0.396000 ;
    PORT
      LAYER Metal3 ;
        RECT 499.440 51.520 500.000 52.080 ;
    END
  END tl_d_uart_i[1]
  PIN tl_d_uart_i[20]
    DIRECTION INPUT ;
    USE SIGNAL ;
    ANTENNAGATEAREA 0.396000 ;
    PORT
      LAYER Metal3 ;
        RECT 499.440 94.080 500.000 94.640 ;
    END
  END tl_d_uart_i[20]
  PIN tl_d_uart_i[21]
    DIRECTION INPUT ;
    USE SIGNAL ;
    ANTENNAGATEAREA 0.396000 ;
    PORT
      LAYER Metal3 ;
        RECT 499.440 96.320 500.000 96.880 ;
    END
  END tl_d_uart_i[21]
  PIN tl_d_uart_i[22]
    DIRECTION INPUT ;
    USE SIGNAL ;
    ANTENNAGATEAREA 0.396000 ;
    PORT
      LAYER Metal3 ;
        RECT 499.440 98.560 500.000 99.120 ;
    END
  END tl_d_uart_i[22]
  PIN tl_d_uart_i[23]
    DIRECTION INPUT ;
    USE SIGNAL ;
    ANTENNAGATEAREA 0.396000 ;
    PORT
      LAYER Metal3 ;
        RECT 499.440 100.800 500.000 101.360 ;
    END
  END tl_d_uart_i[23]
  PIN tl_d_uart_i[24]
    DIRECTION INPUT ;
    USE SIGNAL ;
    ANTENNAGATEAREA 0.396000 ;
    PORT
      LAYER Metal3 ;
        RECT 499.440 103.040 500.000 103.600 ;
    END
  END tl_d_uart_i[24]
  PIN tl_d_uart_i[25]
    DIRECTION INPUT ;
    USE SIGNAL ;
    ANTENNAGATEAREA 0.396000 ;
    PORT
      LAYER Metal3 ;
        RECT 499.440 105.280 500.000 105.840 ;
    END
  END tl_d_uart_i[25]
  PIN tl_d_uart_i[26]
    DIRECTION INPUT ;
    USE SIGNAL ;
    ANTENNAGATEAREA 0.396000 ;
    PORT
      LAYER Metal3 ;
        RECT 499.440 107.520 500.000 108.080 ;
    END
  END tl_d_uart_i[26]
  PIN tl_d_uart_i[27]
    DIRECTION INPUT ;
    USE SIGNAL ;
    ANTENNAGATEAREA 0.396000 ;
    PORT
      LAYER Metal3 ;
        RECT 499.440 109.760 500.000 110.320 ;
    END
  END tl_d_uart_i[27]
  PIN tl_d_uart_i[28]
    DIRECTION INPUT ;
    USE SIGNAL ;
    ANTENNAGATEAREA 0.396000 ;
    PORT
      LAYER Metal3 ;
        RECT 499.440 112.000 500.000 112.560 ;
    END
  END tl_d_uart_i[28]
  PIN tl_d_uart_i[29]
    DIRECTION INPUT ;
    USE SIGNAL ;
    ANTENNAGATEAREA 0.396000 ;
    PORT
      LAYER Metal3 ;
        RECT 499.440 114.240 500.000 114.800 ;
    END
  END tl_d_uart_i[29]
  PIN tl_d_uart_i[2]
    DIRECTION INPUT ;
    USE SIGNAL ;
    ANTENNAGATEAREA 0.396000 ;
    PORT
      LAYER Metal3 ;
        RECT 499.440 53.760 500.000 54.320 ;
    END
  END tl_d_uart_i[2]
  PIN tl_d_uart_i[30]
    DIRECTION INPUT ;
    USE SIGNAL ;
    ANTENNAGATEAREA 0.396000 ;
    PORT
      LAYER Metal3 ;
        RECT 499.440 116.480 500.000 117.040 ;
    END
  END tl_d_uart_i[30]
  PIN tl_d_uart_i[31]
    DIRECTION INPUT ;
    USE SIGNAL ;
    ANTENNAGATEAREA 0.396000 ;
    PORT
      LAYER Metal3 ;
        RECT 499.440 118.720 500.000 119.280 ;
    END
  END tl_d_uart_i[31]
  PIN tl_d_uart_i[32]
    DIRECTION INPUT ;
    USE SIGNAL ;
    ANTENNAGATEAREA 0.396000 ;
    PORT
      LAYER Metal3 ;
        RECT 499.440 120.960 500.000 121.520 ;
    END
  END tl_d_uart_i[32]
  PIN tl_d_uart_i[33]
    DIRECTION INPUT ;
    USE SIGNAL ;
    ANTENNAGATEAREA 0.396000 ;
    PORT
      LAYER Metal3 ;
        RECT 499.440 123.200 500.000 123.760 ;
    END
  END tl_d_uart_i[33]
  PIN tl_d_uart_i[34]
    DIRECTION INPUT ;
    USE SIGNAL ;
    ANTENNAGATEAREA 0.396000 ;
    PORT
      LAYER Metal3 ;
        RECT 499.440 125.440 500.000 126.000 ;
    END
  END tl_d_uart_i[34]
  PIN tl_d_uart_i[35]
    DIRECTION INPUT ;
    USE SIGNAL ;
    ANTENNAGATEAREA 0.396000 ;
    PORT
      LAYER Metal3 ;
        RECT 499.440 127.680 500.000 128.240 ;
    END
  END tl_d_uart_i[35]
  PIN tl_d_uart_i[36]
    DIRECTION INPUT ;
    USE SIGNAL ;
    ANTENNAGATEAREA 0.396000 ;
    PORT
      LAYER Metal3 ;
        RECT 499.440 129.920 500.000 130.480 ;
    END
  END tl_d_uart_i[36]
  PIN tl_d_uart_i[37]
    DIRECTION INPUT ;
    USE SIGNAL ;
    ANTENNAGATEAREA 0.396000 ;
    PORT
      LAYER Metal3 ;
        RECT 499.440 132.160 500.000 132.720 ;
    END
  END tl_d_uart_i[37]
  PIN tl_d_uart_i[38]
    DIRECTION INPUT ;
    USE SIGNAL ;
    ANTENNAGATEAREA 0.396000 ;
    PORT
      LAYER Metal3 ;
        RECT 499.440 134.400 500.000 134.960 ;
    END
  END tl_d_uart_i[38]
  PIN tl_d_uart_i[39]
    DIRECTION INPUT ;
    USE SIGNAL ;
    ANTENNAGATEAREA 0.396000 ;
    PORT
      LAYER Metal3 ;
        RECT 499.440 136.640 500.000 137.200 ;
    END
  END tl_d_uart_i[39]
  PIN tl_d_uart_i[3]
    DIRECTION INPUT ;
    USE SIGNAL ;
    ANTENNAGATEAREA 0.396000 ;
    PORT
      LAYER Metal3 ;
        RECT 499.440 56.000 500.000 56.560 ;
    END
  END tl_d_uart_i[3]
  PIN tl_d_uart_i[40]
    DIRECTION INPUT ;
    USE SIGNAL ;
    ANTENNAGATEAREA 0.396000 ;
    PORT
      LAYER Metal3 ;
        RECT 499.440 138.880 500.000 139.440 ;
    END
  END tl_d_uart_i[40]
  PIN tl_d_uart_i[41]
    DIRECTION INPUT ;
    USE SIGNAL ;
    ANTENNAGATEAREA 0.396000 ;
    PORT
      LAYER Metal3 ;
        RECT 499.440 141.120 500.000 141.680 ;
    END
  END tl_d_uart_i[41]
  PIN tl_d_uart_i[42]
    DIRECTION INPUT ;
    USE SIGNAL ;
    ANTENNAGATEAREA 0.396000 ;
    PORT
      LAYER Metal3 ;
        RECT 499.440 143.360 500.000 143.920 ;
    END
  END tl_d_uart_i[42]
  PIN tl_d_uart_i[43]
    DIRECTION INPUT ;
    USE SIGNAL ;
    ANTENNAGATEAREA 0.396000 ;
    PORT
      LAYER Metal3 ;
        RECT 499.440 145.600 500.000 146.160 ;
    END
  END tl_d_uart_i[43]
  PIN tl_d_uart_i[44]
    DIRECTION INPUT ;
    USE SIGNAL ;
    ANTENNAGATEAREA 0.396000 ;
    PORT
      LAYER Metal3 ;
        RECT 499.440 147.840 500.000 148.400 ;
    END
  END tl_d_uart_i[44]
  PIN tl_d_uart_i[45]
    DIRECTION INPUT ;
    USE SIGNAL ;
    ANTENNAGATEAREA 0.396000 ;
    PORT
      LAYER Metal3 ;
        RECT 499.440 150.080 500.000 150.640 ;
    END
  END tl_d_uart_i[45]
  PIN tl_d_uart_i[46]
    DIRECTION INPUT ;
    USE SIGNAL ;
    ANTENNAGATEAREA 0.396000 ;
    PORT
      LAYER Metal3 ;
        RECT 499.440 152.320 500.000 152.880 ;
    END
  END tl_d_uart_i[46]
  PIN tl_d_uart_i[47]
    DIRECTION INPUT ;
    USE SIGNAL ;
    ANTENNAGATEAREA 0.396000 ;
    PORT
      LAYER Metal3 ;
        RECT 499.440 154.560 500.000 155.120 ;
    END
  END tl_d_uart_i[47]
  PIN tl_d_uart_i[48]
    DIRECTION INPUT ;
    USE SIGNAL ;
    ANTENNAGATEAREA 0.396000 ;
    PORT
      LAYER Metal3 ;
        RECT 499.440 156.800 500.000 157.360 ;
    END
  END tl_d_uart_i[48]
  PIN tl_d_uart_i[49]
    DIRECTION INPUT ;
    USE SIGNAL ;
    ANTENNAGATEAREA 0.396000 ;
    PORT
      LAYER Metal3 ;
        RECT 499.440 159.040 500.000 159.600 ;
    END
  END tl_d_uart_i[49]
  PIN tl_d_uart_i[4]
    DIRECTION INPUT ;
    USE SIGNAL ;
    ANTENNAGATEAREA 0.396000 ;
    PORT
      LAYER Metal3 ;
        RECT 499.440 58.240 500.000 58.800 ;
    END
  END tl_d_uart_i[4]
  PIN tl_d_uart_i[50]
    DIRECTION INPUT ;
    USE SIGNAL ;
    ANTENNAGATEAREA 0.396000 ;
    PORT
      LAYER Metal3 ;
        RECT 499.440 161.280 500.000 161.840 ;
    END
  END tl_d_uart_i[50]
  PIN tl_d_uart_i[51]
    DIRECTION INPUT ;
    USE SIGNAL ;
    ANTENNAGATEAREA 0.396000 ;
    PORT
      LAYER Metal3 ;
        RECT 499.440 163.520 500.000 164.080 ;
    END
  END tl_d_uart_i[51]
  PIN tl_d_uart_i[52]
    DIRECTION INPUT ;
    USE SIGNAL ;
    ANTENNAGATEAREA 0.396000 ;
    PORT
      LAYER Metal3 ;
        RECT 499.440 165.760 500.000 166.320 ;
    END
  END tl_d_uart_i[52]
  PIN tl_d_uart_i[53]
    DIRECTION INPUT ;
    USE SIGNAL ;
    ANTENNAGATEAREA 0.396000 ;
    PORT
      LAYER Metal3 ;
        RECT 499.440 168.000 500.000 168.560 ;
    END
  END tl_d_uart_i[53]
  PIN tl_d_uart_i[54]
    DIRECTION INPUT ;
    USE SIGNAL ;
    ANTENNAGATEAREA 0.396000 ;
    PORT
      LAYER Metal3 ;
        RECT 499.440 170.240 500.000 170.800 ;
    END
  END tl_d_uart_i[54]
  PIN tl_d_uart_i[55]
    DIRECTION INPUT ;
    USE SIGNAL ;
    ANTENNAGATEAREA 0.396000 ;
    PORT
      LAYER Metal3 ;
        RECT 499.440 172.480 500.000 173.040 ;
    END
  END tl_d_uart_i[55]
  PIN tl_d_uart_i[56]
    DIRECTION INPUT ;
    USE SIGNAL ;
    ANTENNAGATEAREA 0.396000 ;
    PORT
      LAYER Metal3 ;
        RECT 499.440 174.720 500.000 175.280 ;
    END
  END tl_d_uart_i[56]
  PIN tl_d_uart_i[57]
    DIRECTION INPUT ;
    USE SIGNAL ;
    ANTENNAGATEAREA 0.396000 ;
    PORT
      LAYER Metal3 ;
        RECT 499.440 176.960 500.000 177.520 ;
    END
  END tl_d_uart_i[57]
  PIN tl_d_uart_i[58]
    DIRECTION INPUT ;
    USE SIGNAL ;
    ANTENNAGATEAREA 0.396000 ;
    PORT
      LAYER Metal3 ;
        RECT 499.440 179.200 500.000 179.760 ;
    END
  END tl_d_uart_i[58]
  PIN tl_d_uart_i[59]
    DIRECTION INPUT ;
    USE SIGNAL ;
    ANTENNAGATEAREA 0.396000 ;
    PORT
      LAYER Metal3 ;
        RECT 499.440 181.440 500.000 182.000 ;
    END
  END tl_d_uart_i[59]
  PIN tl_d_uart_i[5]
    DIRECTION INPUT ;
    USE SIGNAL ;
    ANTENNAGATEAREA 0.396000 ;
    PORT
      LAYER Metal3 ;
        RECT 499.440 60.480 500.000 61.040 ;
    END
  END tl_d_uart_i[5]
  PIN tl_d_uart_i[60]
    DIRECTION INPUT ;
    USE SIGNAL ;
    ANTENNAGATEAREA 0.396000 ;
    PORT
      LAYER Metal3 ;
        RECT 499.440 183.680 500.000 184.240 ;
    END
  END tl_d_uart_i[60]
  PIN tl_d_uart_i[61]
    DIRECTION INPUT ;
    USE SIGNAL ;
    ANTENNAGATEAREA 0.396000 ;
    PORT
      LAYER Metal3 ;
        RECT 499.440 185.920 500.000 186.480 ;
    END
  END tl_d_uart_i[61]
  PIN tl_d_uart_i[62]
    DIRECTION INPUT ;
    USE SIGNAL ;
    ANTENNAGATEAREA 0.396000 ;
    PORT
      LAYER Metal3 ;
        RECT 499.440 188.160 500.000 188.720 ;
    END
  END tl_d_uart_i[62]
  PIN tl_d_uart_i[63]
    DIRECTION INPUT ;
    USE SIGNAL ;
    ANTENNAGATEAREA 0.396000 ;
    PORT
      LAYER Metal3 ;
        RECT 499.440 190.400 500.000 190.960 ;
    END
  END tl_d_uart_i[63]
  PIN tl_d_uart_i[64]
    DIRECTION INPUT ;
    USE SIGNAL ;
    ANTENNAGATEAREA 0.396000 ;
    PORT
      LAYER Metal3 ;
        RECT 499.440 192.640 500.000 193.200 ;
    END
  END tl_d_uart_i[64]
  PIN tl_d_uart_i[65]
    DIRECTION INPUT ;
    USE SIGNAL ;
    ANTENNAGATEAREA 0.396000 ;
    PORT
      LAYER Metal3 ;
        RECT 499.440 194.880 500.000 195.440 ;
    END
  END tl_d_uart_i[65]
  PIN tl_d_uart_i[6]
    DIRECTION INPUT ;
    USE SIGNAL ;
    ANTENNAGATEAREA 0.396000 ;
    PORT
      LAYER Metal3 ;
        RECT 499.440 62.720 500.000 63.280 ;
    END
  END tl_d_uart_i[6]
  PIN tl_d_uart_i[7]
    DIRECTION INPUT ;
    USE SIGNAL ;
    ANTENNAGATEAREA 0.396000 ;
    PORT
      LAYER Metal3 ;
        RECT 499.440 64.960 500.000 65.520 ;
    END
  END tl_d_uart_i[7]
  PIN tl_d_uart_i[8]
    DIRECTION INPUT ;
    USE SIGNAL ;
    ANTENNAGATEAREA 0.396000 ;
    PORT
      LAYER Metal3 ;
        RECT 499.440 67.200 500.000 67.760 ;
    END
  END tl_d_uart_i[8]
  PIN tl_d_uart_i[9]
    DIRECTION INPUT ;
    USE SIGNAL ;
    ANTENNAGATEAREA 0.396000 ;
    PORT
      LAYER Metal3 ;
        RECT 499.440 69.440 500.000 70.000 ;
    END
  END tl_d_uart_i[9]
  PIN tl_d_uart_o[0]
    DIRECTION OUTPUT ;
    USE SIGNAL ;
    ANTENNADIFFAREA 0.897600 ;
    PORT
      LAYER Metal3 ;
        RECT 499.440 197.120 500.000 197.680 ;
    END
  END tl_d_uart_o[0]
  PIN tl_d_uart_o[100]
    DIRECTION OUTPUT ;
    USE SIGNAL ;
    ANTENNADIFFAREA 0.897600 ;
    PORT
      LAYER Metal3 ;
        RECT 499.440 421.120 500.000 421.680 ;
    END
  END tl_d_uart_o[100]
  PIN tl_d_uart_o[101]
    DIRECTION OUTPUT ;
    USE SIGNAL ;
    ANTENNADIFFAREA 0.897600 ;
    PORT
      LAYER Metal3 ;
        RECT 499.440 423.360 500.000 423.920 ;
    END
  END tl_d_uart_o[101]
  PIN tl_d_uart_o[102]
    DIRECTION OUTPUT ;
    USE SIGNAL ;
    ANTENNADIFFAREA 0.897600 ;
    PORT
      LAYER Metal3 ;
        RECT 499.440 425.600 500.000 426.160 ;
    END
  END tl_d_uart_o[102]
  PIN tl_d_uart_o[103]
    DIRECTION OUTPUT ;
    USE SIGNAL ;
    ANTENNADIFFAREA 0.897600 ;
    PORT
      LAYER Metal3 ;
        RECT 499.440 427.840 500.000 428.400 ;
    END
  END tl_d_uart_o[103]
  PIN tl_d_uart_o[104]
    DIRECTION OUTPUT ;
    USE SIGNAL ;
    ANTENNADIFFAREA 0.897600 ;
    PORT
      LAYER Metal3 ;
        RECT 499.440 430.080 500.000 430.640 ;
    END
  END tl_d_uart_o[104]
  PIN tl_d_uart_o[105]
    DIRECTION OUTPUT ;
    USE SIGNAL ;
    ANTENNADIFFAREA 0.897600 ;
    PORT
      LAYER Metal3 ;
        RECT 499.440 432.320 500.000 432.880 ;
    END
  END tl_d_uart_o[105]
  PIN tl_d_uart_o[106]
    DIRECTION OUTPUT ;
    USE SIGNAL ;
    ANTENNADIFFAREA 0.897600 ;
    PORT
      LAYER Metal3 ;
        RECT 499.440 434.560 500.000 435.120 ;
    END
  END tl_d_uart_o[106]
  PIN tl_d_uart_o[107]
    DIRECTION OUTPUT ;
    USE SIGNAL ;
    ANTENNADIFFAREA 0.897600 ;
    PORT
      LAYER Metal3 ;
        RECT 499.440 436.800 500.000 437.360 ;
    END
  END tl_d_uart_o[107]
  PIN tl_d_uart_o[108]
    DIRECTION OUTPUT ;
    USE SIGNAL ;
    ANTENNADIFFAREA 0.897600 ;
    PORT
      LAYER Metal3 ;
        RECT 499.440 439.040 500.000 439.600 ;
    END
  END tl_d_uart_o[108]
  PIN tl_d_uart_o[109]
    DIRECTION OUTPUT ;
    USE SIGNAL ;
    ANTENNADIFFAREA 0.897600 ;
    PORT
      LAYER Metal3 ;
        RECT 499.440 441.280 500.000 441.840 ;
    END
  END tl_d_uart_o[109]
  PIN tl_d_uart_o[10]
    DIRECTION OUTPUT ;
    USE SIGNAL ;
    ANTENNADIFFAREA 0.897600 ;
    PORT
      LAYER Metal3 ;
        RECT 499.440 219.520 500.000 220.080 ;
    END
  END tl_d_uart_o[10]
  PIN tl_d_uart_o[110]
    DIRECTION OUTPUT ;
    USE SIGNAL ;
    ANTENNADIFFAREA 0.897600 ;
    PORT
      LAYER Metal3 ;
        RECT 499.440 443.520 500.000 444.080 ;
    END
  END tl_d_uart_o[110]
  PIN tl_d_uart_o[111]
    DIRECTION OUTPUT ;
    USE SIGNAL ;
    ANTENNADIFFAREA 0.897600 ;
    PORT
      LAYER Metal3 ;
        RECT 499.440 445.760 500.000 446.320 ;
    END
  END tl_d_uart_o[111]
  PIN tl_d_uart_o[112]
    DIRECTION OUTPUT ;
    USE SIGNAL ;
    ANTENNADIFFAREA 0.897600 ;
    PORT
      LAYER Metal3 ;
        RECT 499.440 448.000 500.000 448.560 ;
    END
  END tl_d_uart_o[112]
  PIN tl_d_uart_o[113]
    DIRECTION OUTPUT ;
    USE SIGNAL ;
    ANTENNADIFFAREA 0.897600 ;
    PORT
      LAYER Metal3 ;
        RECT 499.440 450.240 500.000 450.800 ;
    END
  END tl_d_uart_o[113]
  PIN tl_d_uart_o[11]
    DIRECTION OUTPUT ;
    USE SIGNAL ;
    ANTENNADIFFAREA 0.897600 ;
    PORT
      LAYER Metal3 ;
        RECT 499.440 221.760 500.000 222.320 ;
    END
  END tl_d_uart_o[11]
  PIN tl_d_uart_o[12]
    DIRECTION OUTPUT ;
    USE SIGNAL ;
    ANTENNADIFFAREA 0.897600 ;
    PORT
      LAYER Metal3 ;
        RECT 499.440 224.000 500.000 224.560 ;
    END
  END tl_d_uart_o[12]
  PIN tl_d_uart_o[13]
    DIRECTION OUTPUT ;
    USE SIGNAL ;
    ANTENNADIFFAREA 0.897600 ;
    PORT
      LAYER Metal3 ;
        RECT 499.440 226.240 500.000 226.800 ;
    END
  END tl_d_uart_o[13]
  PIN tl_d_uart_o[14]
    DIRECTION OUTPUT ;
    USE SIGNAL ;
    ANTENNADIFFAREA 0.897600 ;
    PORT
      LAYER Metal3 ;
        RECT 499.440 228.480 500.000 229.040 ;
    END
  END tl_d_uart_o[14]
  PIN tl_d_uart_o[15]
    DIRECTION OUTPUT ;
    USE SIGNAL ;
    ANTENNADIFFAREA 0.897600 ;
    PORT
      LAYER Metal3 ;
        RECT 499.440 230.720 500.000 231.280 ;
    END
  END tl_d_uart_o[15]
  PIN tl_d_uart_o[16]
    DIRECTION OUTPUT ;
    USE SIGNAL ;
    ANTENNADIFFAREA 0.897600 ;
    PORT
      LAYER Metal3 ;
        RECT 499.440 232.960 500.000 233.520 ;
    END
  END tl_d_uart_o[16]
  PIN tl_d_uart_o[17]
    DIRECTION OUTPUT ;
    USE SIGNAL ;
    ANTENNADIFFAREA 0.897600 ;
    PORT
      LAYER Metal3 ;
        RECT 499.440 235.200 500.000 235.760 ;
    END
  END tl_d_uart_o[17]
  PIN tl_d_uart_o[18]
    DIRECTION OUTPUT ;
    USE SIGNAL ;
    ANTENNADIFFAREA 0.897600 ;
    PORT
      LAYER Metal3 ;
        RECT 499.440 237.440 500.000 238.000 ;
    END
  END tl_d_uart_o[18]
  PIN tl_d_uart_o[19]
    DIRECTION OUTPUT ;
    USE SIGNAL ;
    ANTENNADIFFAREA 0.897600 ;
    PORT
      LAYER Metal3 ;
        RECT 499.440 239.680 500.000 240.240 ;
    END
  END tl_d_uart_o[19]
  PIN tl_d_uart_o[1]
    DIRECTION OUTPUT ;
    USE SIGNAL ;
    ANTENNADIFFAREA 0.897600 ;
    PORT
      LAYER Metal3 ;
        RECT 499.440 199.360 500.000 199.920 ;
    END
  END tl_d_uart_o[1]
  PIN tl_d_uart_o[20]
    DIRECTION OUTPUT ;
    USE SIGNAL ;
    ANTENNADIFFAREA 0.897600 ;
    PORT
      LAYER Metal3 ;
        RECT 499.440 241.920 500.000 242.480 ;
    END
  END tl_d_uart_o[20]
  PIN tl_d_uart_o[21]
    DIRECTION OUTPUT ;
    USE SIGNAL ;
    ANTENNADIFFAREA 0.897600 ;
    PORT
      LAYER Metal3 ;
        RECT 499.440 244.160 500.000 244.720 ;
    END
  END tl_d_uart_o[21]
  PIN tl_d_uart_o[22]
    DIRECTION OUTPUT ;
    USE SIGNAL ;
    ANTENNADIFFAREA 0.897600 ;
    PORT
      LAYER Metal3 ;
        RECT 499.440 246.400 500.000 246.960 ;
    END
  END tl_d_uart_o[22]
  PIN tl_d_uart_o[23]
    DIRECTION OUTPUT ;
    USE SIGNAL ;
    ANTENNADIFFAREA 0.897600 ;
    PORT
      LAYER Metal3 ;
        RECT 499.440 248.640 500.000 249.200 ;
    END
  END tl_d_uart_o[23]
  PIN tl_d_uart_o[24]
    DIRECTION OUTPUT ;
    USE SIGNAL ;
    ANTENNADIFFAREA 0.897600 ;
    PORT
      LAYER Metal3 ;
        RECT 499.440 250.880 500.000 251.440 ;
    END
  END tl_d_uart_o[24]
  PIN tl_d_uart_o[25]
    DIRECTION OUTPUT ;
    USE SIGNAL ;
    ANTENNADIFFAREA 0.897600 ;
    PORT
      LAYER Metal3 ;
        RECT 499.440 253.120 500.000 253.680 ;
    END
  END tl_d_uart_o[25]
  PIN tl_d_uart_o[26]
    DIRECTION OUTPUT ;
    USE SIGNAL ;
    ANTENNADIFFAREA 0.897600 ;
    PORT
      LAYER Metal3 ;
        RECT 499.440 255.360 500.000 255.920 ;
    END
  END tl_d_uart_o[26]
  PIN tl_d_uart_o[27]
    DIRECTION OUTPUT ;
    USE SIGNAL ;
    ANTENNADIFFAREA 0.897600 ;
    PORT
      LAYER Metal3 ;
        RECT 499.440 257.600 500.000 258.160 ;
    END
  END tl_d_uart_o[27]
  PIN tl_d_uart_o[28]
    DIRECTION OUTPUT ;
    USE SIGNAL ;
    ANTENNADIFFAREA 0.897600 ;
    PORT
      LAYER Metal3 ;
        RECT 499.440 259.840 500.000 260.400 ;
    END
  END tl_d_uart_o[28]
  PIN tl_d_uart_o[29]
    DIRECTION OUTPUT ;
    USE SIGNAL ;
    ANTENNADIFFAREA 0.897600 ;
    PORT
      LAYER Metal3 ;
        RECT 499.440 262.080 500.000 262.640 ;
    END
  END tl_d_uart_o[29]
  PIN tl_d_uart_o[2]
    DIRECTION OUTPUT ;
    USE SIGNAL ;
    ANTENNADIFFAREA 0.897600 ;
    PORT
      LAYER Metal3 ;
        RECT 499.440 201.600 500.000 202.160 ;
    END
  END tl_d_uart_o[2]
  PIN tl_d_uart_o[30]
    DIRECTION OUTPUT ;
    USE SIGNAL ;
    ANTENNADIFFAREA 0.897600 ;
    PORT
      LAYER Metal3 ;
        RECT 499.440 264.320 500.000 264.880 ;
    END
  END tl_d_uart_o[30]
  PIN tl_d_uart_o[31]
    DIRECTION OUTPUT ;
    USE SIGNAL ;
    ANTENNADIFFAREA 0.897600 ;
    PORT
      LAYER Metal3 ;
        RECT 499.440 266.560 500.000 267.120 ;
    END
  END tl_d_uart_o[31]
  PIN tl_d_uart_o[32]
    DIRECTION OUTPUT ;
    USE SIGNAL ;
    ANTENNADIFFAREA 0.897600 ;
    PORT
      LAYER Metal3 ;
        RECT 499.440 268.800 500.000 269.360 ;
    END
  END tl_d_uart_o[32]
  PIN tl_d_uart_o[33]
    DIRECTION OUTPUT ;
    USE SIGNAL ;
    ANTENNADIFFAREA 0.897600 ;
    PORT
      LAYER Metal3 ;
        RECT 499.440 271.040 500.000 271.600 ;
    END
  END tl_d_uart_o[33]
  PIN tl_d_uart_o[34]
    DIRECTION OUTPUT ;
    USE SIGNAL ;
    ANTENNADIFFAREA 0.897600 ;
    PORT
      LAYER Metal3 ;
        RECT 499.440 273.280 500.000 273.840 ;
    END
  END tl_d_uart_o[34]
  PIN tl_d_uart_o[35]
    DIRECTION OUTPUT ;
    USE SIGNAL ;
    ANTENNADIFFAREA 0.897600 ;
    PORT
      LAYER Metal3 ;
        RECT 499.440 275.520 500.000 276.080 ;
    END
  END tl_d_uart_o[35]
  PIN tl_d_uart_o[36]
    DIRECTION OUTPUT ;
    USE SIGNAL ;
    ANTENNADIFFAREA 0.897600 ;
    PORT
      LAYER Metal3 ;
        RECT 499.440 277.760 500.000 278.320 ;
    END
  END tl_d_uart_o[36]
  PIN tl_d_uart_o[37]
    DIRECTION OUTPUT ;
    USE SIGNAL ;
    ANTENNADIFFAREA 0.897600 ;
    PORT
      LAYER Metal3 ;
        RECT 499.440 280.000 500.000 280.560 ;
    END
  END tl_d_uart_o[37]
  PIN tl_d_uart_o[38]
    DIRECTION OUTPUT ;
    USE SIGNAL ;
    ANTENNADIFFAREA 0.897600 ;
    PORT
      LAYER Metal3 ;
        RECT 499.440 282.240 500.000 282.800 ;
    END
  END tl_d_uart_o[38]
  PIN tl_d_uart_o[39]
    DIRECTION OUTPUT ;
    USE SIGNAL ;
    ANTENNADIFFAREA 0.897600 ;
    PORT
      LAYER Metal3 ;
        RECT 499.440 284.480 500.000 285.040 ;
    END
  END tl_d_uart_o[39]
  PIN tl_d_uart_o[3]
    DIRECTION OUTPUT ;
    USE SIGNAL ;
    ANTENNADIFFAREA 0.897600 ;
    PORT
      LAYER Metal3 ;
        RECT 499.440 203.840 500.000 204.400 ;
    END
  END tl_d_uart_o[3]
  PIN tl_d_uart_o[40]
    DIRECTION OUTPUT ;
    USE SIGNAL ;
    ANTENNADIFFAREA 0.897600 ;
    PORT
      LAYER Metal3 ;
        RECT 499.440 286.720 500.000 287.280 ;
    END
  END tl_d_uart_o[40]
  PIN tl_d_uart_o[41]
    DIRECTION OUTPUT ;
    USE SIGNAL ;
    ANTENNADIFFAREA 0.897600 ;
    PORT
      LAYER Metal3 ;
        RECT 499.440 288.960 500.000 289.520 ;
    END
  END tl_d_uart_o[41]
  PIN tl_d_uart_o[42]
    DIRECTION OUTPUT ;
    USE SIGNAL ;
    ANTENNADIFFAREA 0.897600 ;
    PORT
      LAYER Metal3 ;
        RECT 499.440 291.200 500.000 291.760 ;
    END
  END tl_d_uart_o[42]
  PIN tl_d_uart_o[43]
    DIRECTION OUTPUT ;
    USE SIGNAL ;
    ANTENNADIFFAREA 0.897600 ;
    PORT
      LAYER Metal3 ;
        RECT 499.440 293.440 500.000 294.000 ;
    END
  END tl_d_uart_o[43]
  PIN tl_d_uart_o[44]
    DIRECTION OUTPUT ;
    USE SIGNAL ;
    ANTENNADIFFAREA 0.897600 ;
    PORT
      LAYER Metal3 ;
        RECT 499.440 295.680 500.000 296.240 ;
    END
  END tl_d_uart_o[44]
  PIN tl_d_uart_o[45]
    DIRECTION OUTPUT ;
    USE SIGNAL ;
    ANTENNADIFFAREA 0.897600 ;
    PORT
      LAYER Metal3 ;
        RECT 499.440 297.920 500.000 298.480 ;
    END
  END tl_d_uart_o[45]
  PIN tl_d_uart_o[46]
    DIRECTION OUTPUT ;
    USE SIGNAL ;
    ANTENNADIFFAREA 0.897600 ;
    PORT
      LAYER Metal3 ;
        RECT 499.440 300.160 500.000 300.720 ;
    END
  END tl_d_uart_o[46]
  PIN tl_d_uart_o[47]
    DIRECTION OUTPUT ;
    USE SIGNAL ;
    ANTENNADIFFAREA 0.897600 ;
    PORT
      LAYER Metal3 ;
        RECT 499.440 302.400 500.000 302.960 ;
    END
  END tl_d_uart_o[47]
  PIN tl_d_uart_o[48]
    DIRECTION OUTPUT ;
    USE SIGNAL ;
    ANTENNADIFFAREA 0.897600 ;
    PORT
      LAYER Metal3 ;
        RECT 499.440 304.640 500.000 305.200 ;
    END
  END tl_d_uart_o[48]
  PIN tl_d_uart_o[49]
    DIRECTION OUTPUT ;
    USE SIGNAL ;
    ANTENNADIFFAREA 0.897600 ;
    PORT
      LAYER Metal3 ;
        RECT 499.440 306.880 500.000 307.440 ;
    END
  END tl_d_uart_o[49]
  PIN tl_d_uart_o[4]
    DIRECTION OUTPUT ;
    USE SIGNAL ;
    ANTENNADIFFAREA 0.897600 ;
    PORT
      LAYER Metal3 ;
        RECT 499.440 206.080 500.000 206.640 ;
    END
  END tl_d_uart_o[4]
  PIN tl_d_uart_o[50]
    DIRECTION OUTPUT ;
    USE SIGNAL ;
    ANTENNADIFFAREA 0.897600 ;
    PORT
      LAYER Metal3 ;
        RECT 499.440 309.120 500.000 309.680 ;
    END
  END tl_d_uart_o[50]
  PIN tl_d_uart_o[51]
    DIRECTION OUTPUT ;
    USE SIGNAL ;
    ANTENNADIFFAREA 0.897600 ;
    PORT
      LAYER Metal3 ;
        RECT 499.440 311.360 500.000 311.920 ;
    END
  END tl_d_uart_o[51]
  PIN tl_d_uart_o[52]
    DIRECTION OUTPUT ;
    USE SIGNAL ;
    ANTENNADIFFAREA 0.897600 ;
    PORT
      LAYER Metal3 ;
        RECT 499.440 313.600 500.000 314.160 ;
    END
  END tl_d_uart_o[52]
  PIN tl_d_uart_o[53]
    DIRECTION OUTPUT ;
    USE SIGNAL ;
    ANTENNADIFFAREA 0.897600 ;
    PORT
      LAYER Metal3 ;
        RECT 499.440 315.840 500.000 316.400 ;
    END
  END tl_d_uart_o[53]
  PIN tl_d_uart_o[54]
    DIRECTION OUTPUT ;
    USE SIGNAL ;
    ANTENNADIFFAREA 0.897600 ;
    PORT
      LAYER Metal3 ;
        RECT 499.440 318.080 500.000 318.640 ;
    END
  END tl_d_uart_o[54]
  PIN tl_d_uart_o[55]
    DIRECTION OUTPUT ;
    USE SIGNAL ;
    ANTENNADIFFAREA 0.897600 ;
    PORT
      LAYER Metal3 ;
        RECT 499.440 320.320 500.000 320.880 ;
    END
  END tl_d_uart_o[55]
  PIN tl_d_uart_o[56]
    DIRECTION OUTPUT ;
    USE SIGNAL ;
    ANTENNADIFFAREA 0.897600 ;
    PORT
      LAYER Metal3 ;
        RECT 499.440 322.560 500.000 323.120 ;
    END
  END tl_d_uart_o[56]
  PIN tl_d_uart_o[57]
    DIRECTION OUTPUT ;
    USE SIGNAL ;
    ANTENNADIFFAREA 0.897600 ;
    PORT
      LAYER Metal3 ;
        RECT 499.440 324.800 500.000 325.360 ;
    END
  END tl_d_uart_o[57]
  PIN tl_d_uart_o[58]
    DIRECTION OUTPUT ;
    USE SIGNAL ;
    ANTENNADIFFAREA 0.897600 ;
    PORT
      LAYER Metal3 ;
        RECT 499.440 327.040 500.000 327.600 ;
    END
  END tl_d_uart_o[58]
  PIN tl_d_uart_o[59]
    DIRECTION OUTPUT ;
    USE SIGNAL ;
    ANTENNADIFFAREA 0.897600 ;
    PORT
      LAYER Metal3 ;
        RECT 499.440 329.280 500.000 329.840 ;
    END
  END tl_d_uart_o[59]
  PIN tl_d_uart_o[5]
    DIRECTION OUTPUT ;
    USE SIGNAL ;
    ANTENNADIFFAREA 0.897600 ;
    PORT
      LAYER Metal3 ;
        RECT 499.440 208.320 500.000 208.880 ;
    END
  END tl_d_uart_o[5]
  PIN tl_d_uart_o[60]
    DIRECTION OUTPUT ;
    USE SIGNAL ;
    ANTENNADIFFAREA 0.897600 ;
    PORT
      LAYER Metal3 ;
        RECT 499.440 331.520 500.000 332.080 ;
    END
  END tl_d_uart_o[60]
  PIN tl_d_uart_o[61]
    DIRECTION OUTPUT ;
    USE SIGNAL ;
    ANTENNADIFFAREA 0.897600 ;
    PORT
      LAYER Metal3 ;
        RECT 499.440 333.760 500.000 334.320 ;
    END
  END tl_d_uart_o[61]
  PIN tl_d_uart_o[62]
    DIRECTION OUTPUT ;
    USE SIGNAL ;
    ANTENNADIFFAREA 0.897600 ;
    PORT
      LAYER Metal3 ;
        RECT 499.440 336.000 500.000 336.560 ;
    END
  END tl_d_uart_o[62]
  PIN tl_d_uart_o[63]
    DIRECTION OUTPUT ;
    USE SIGNAL ;
    ANTENNADIFFAREA 0.897600 ;
    PORT
      LAYER Metal3 ;
        RECT 499.440 338.240 500.000 338.800 ;
    END
  END tl_d_uart_o[63]
  PIN tl_d_uart_o[64]
    DIRECTION OUTPUT ;
    USE SIGNAL ;
    ANTENNADIFFAREA 0.897600 ;
    PORT
      LAYER Metal3 ;
        RECT 499.440 340.480 500.000 341.040 ;
    END
  END tl_d_uart_o[64]
  PIN tl_d_uart_o[65]
    DIRECTION OUTPUT ;
    USE SIGNAL ;
    ANTENNADIFFAREA 0.897600 ;
    PORT
      LAYER Metal3 ;
        RECT 499.440 342.720 500.000 343.280 ;
    END
  END tl_d_uart_o[65]
  PIN tl_d_uart_o[66]
    DIRECTION OUTPUT ;
    USE SIGNAL ;
    ANTENNADIFFAREA 0.897600 ;
    PORT
      LAYER Metal3 ;
        RECT 499.440 344.960 500.000 345.520 ;
    END
  END tl_d_uart_o[66]
  PIN tl_d_uart_o[67]
    DIRECTION OUTPUT ;
    USE SIGNAL ;
    ANTENNADIFFAREA 0.897600 ;
    PORT
      LAYER Metal3 ;
        RECT 499.440 347.200 500.000 347.760 ;
    END
  END tl_d_uart_o[67]
  PIN tl_d_uart_o[68]
    DIRECTION OUTPUT ;
    USE SIGNAL ;
    ANTENNADIFFAREA 0.897600 ;
    PORT
      LAYER Metal3 ;
        RECT 499.440 349.440 500.000 350.000 ;
    END
  END tl_d_uart_o[68]
  PIN tl_d_uart_o[69]
    DIRECTION OUTPUT ;
    USE SIGNAL ;
    ANTENNADIFFAREA 0.897600 ;
    PORT
      LAYER Metal3 ;
        RECT 499.440 351.680 500.000 352.240 ;
    END
  END tl_d_uart_o[69]
  PIN tl_d_uart_o[6]
    DIRECTION OUTPUT ;
    USE SIGNAL ;
    ANTENNADIFFAREA 0.897600 ;
    PORT
      LAYER Metal3 ;
        RECT 499.440 210.560 500.000 211.120 ;
    END
  END tl_d_uart_o[6]
  PIN tl_d_uart_o[70]
    DIRECTION OUTPUT ;
    USE SIGNAL ;
    ANTENNADIFFAREA 0.897600 ;
    PORT
      LAYER Metal3 ;
        RECT 499.440 353.920 500.000 354.480 ;
    END
  END tl_d_uart_o[70]
  PIN tl_d_uart_o[71]
    DIRECTION OUTPUT ;
    USE SIGNAL ;
    ANTENNADIFFAREA 0.897600 ;
    PORT
      LAYER Metal3 ;
        RECT 499.440 356.160 500.000 356.720 ;
    END
  END tl_d_uart_o[71]
  PIN tl_d_uart_o[72]
    DIRECTION OUTPUT ;
    USE SIGNAL ;
    ANTENNADIFFAREA 0.897600 ;
    PORT
      LAYER Metal3 ;
        RECT 499.440 358.400 500.000 358.960 ;
    END
  END tl_d_uart_o[72]
  PIN tl_d_uart_o[73]
    DIRECTION OUTPUT ;
    USE SIGNAL ;
    ANTENNADIFFAREA 0.897600 ;
    PORT
      LAYER Metal3 ;
        RECT 499.440 360.640 500.000 361.200 ;
    END
  END tl_d_uart_o[73]
  PIN tl_d_uart_o[74]
    DIRECTION OUTPUT ;
    USE SIGNAL ;
    ANTENNADIFFAREA 0.897600 ;
    PORT
      LAYER Metal3 ;
        RECT 499.440 362.880 500.000 363.440 ;
    END
  END tl_d_uart_o[74]
  PIN tl_d_uart_o[75]
    DIRECTION OUTPUT ;
    USE SIGNAL ;
    ANTENNADIFFAREA 0.897600 ;
    PORT
      LAYER Metal3 ;
        RECT 499.440 365.120 500.000 365.680 ;
    END
  END tl_d_uart_o[75]
  PIN tl_d_uart_o[76]
    DIRECTION OUTPUT ;
    USE SIGNAL ;
    ANTENNADIFFAREA 0.897600 ;
    PORT
      LAYER Metal3 ;
        RECT 499.440 367.360 500.000 367.920 ;
    END
  END tl_d_uart_o[76]
  PIN tl_d_uart_o[77]
    DIRECTION OUTPUT ;
    USE SIGNAL ;
    ANTENNADIFFAREA 0.897600 ;
    PORT
      LAYER Metal3 ;
        RECT 499.440 369.600 500.000 370.160 ;
    END
  END tl_d_uart_o[77]
  PIN tl_d_uart_o[78]
    DIRECTION OUTPUT ;
    USE SIGNAL ;
    ANTENNADIFFAREA 0.897600 ;
    PORT
      LAYER Metal3 ;
        RECT 499.440 371.840 500.000 372.400 ;
    END
  END tl_d_uart_o[78]
  PIN tl_d_uart_o[79]
    DIRECTION OUTPUT ;
    USE SIGNAL ;
    ANTENNADIFFAREA 0.897600 ;
    PORT
      LAYER Metal3 ;
        RECT 499.440 374.080 500.000 374.640 ;
    END
  END tl_d_uart_o[79]
  PIN tl_d_uart_o[7]
    DIRECTION OUTPUT ;
    USE SIGNAL ;
    ANTENNADIFFAREA 0.897600 ;
    PORT
      LAYER Metal3 ;
        RECT 499.440 212.800 500.000 213.360 ;
    END
  END tl_d_uart_o[7]
  PIN tl_d_uart_o[80]
    DIRECTION OUTPUT ;
    USE SIGNAL ;
    ANTENNADIFFAREA 0.897600 ;
    PORT
      LAYER Metal3 ;
        RECT 499.440 376.320 500.000 376.880 ;
    END
  END tl_d_uart_o[80]
  PIN tl_d_uart_o[81]
    DIRECTION OUTPUT ;
    USE SIGNAL ;
    ANTENNADIFFAREA 0.897600 ;
    PORT
      LAYER Metal3 ;
        RECT 499.440 378.560 500.000 379.120 ;
    END
  END tl_d_uart_o[81]
  PIN tl_d_uart_o[82]
    DIRECTION OUTPUT ;
    USE SIGNAL ;
    ANTENNADIFFAREA 0.897600 ;
    PORT
      LAYER Metal3 ;
        RECT 499.440 380.800 500.000 381.360 ;
    END
  END tl_d_uart_o[82]
  PIN tl_d_uart_o[83]
    DIRECTION OUTPUT ;
    USE SIGNAL ;
    ANTENNADIFFAREA 0.897600 ;
    PORT
      LAYER Metal3 ;
        RECT 499.440 383.040 500.000 383.600 ;
    END
  END tl_d_uart_o[83]
  PIN tl_d_uart_o[84]
    DIRECTION OUTPUT ;
    USE SIGNAL ;
    ANTENNADIFFAREA 0.897600 ;
    PORT
      LAYER Metal3 ;
        RECT 499.440 385.280 500.000 385.840 ;
    END
  END tl_d_uart_o[84]
  PIN tl_d_uart_o[85]
    DIRECTION OUTPUT ;
    USE SIGNAL ;
    ANTENNADIFFAREA 0.897600 ;
    PORT
      LAYER Metal3 ;
        RECT 499.440 387.520 500.000 388.080 ;
    END
  END tl_d_uart_o[85]
  PIN tl_d_uart_o[86]
    DIRECTION OUTPUT ;
    USE SIGNAL ;
    ANTENNADIFFAREA 0.897600 ;
    PORT
      LAYER Metal3 ;
        RECT 499.440 389.760 500.000 390.320 ;
    END
  END tl_d_uart_o[86]
  PIN tl_d_uart_o[87]
    DIRECTION OUTPUT ;
    USE SIGNAL ;
    ANTENNADIFFAREA 0.897600 ;
    PORT
      LAYER Metal3 ;
        RECT 499.440 392.000 500.000 392.560 ;
    END
  END tl_d_uart_o[87]
  PIN tl_d_uart_o[88]
    DIRECTION OUTPUT ;
    USE SIGNAL ;
    ANTENNADIFFAREA 0.897600 ;
    PORT
      LAYER Metal3 ;
        RECT 499.440 394.240 500.000 394.800 ;
    END
  END tl_d_uart_o[88]
  PIN tl_d_uart_o[89]
    DIRECTION OUTPUT ;
    USE SIGNAL ;
    ANTENNADIFFAREA 0.897600 ;
    PORT
      LAYER Metal3 ;
        RECT 499.440 396.480 500.000 397.040 ;
    END
  END tl_d_uart_o[89]
  PIN tl_d_uart_o[8]
    DIRECTION OUTPUT ;
    USE SIGNAL ;
    ANTENNADIFFAREA 0.897600 ;
    PORT
      LAYER Metal3 ;
        RECT 499.440 215.040 500.000 215.600 ;
    END
  END tl_d_uart_o[8]
  PIN tl_d_uart_o[90]
    DIRECTION OUTPUT ;
    USE SIGNAL ;
    ANTENNADIFFAREA 0.897600 ;
    PORT
      LAYER Metal3 ;
        RECT 499.440 398.720 500.000 399.280 ;
    END
  END tl_d_uart_o[90]
  PIN tl_d_uart_o[91]
    DIRECTION OUTPUT ;
    USE SIGNAL ;
    ANTENNADIFFAREA 0.897600 ;
    PORT
      LAYER Metal3 ;
        RECT 499.440 400.960 500.000 401.520 ;
    END
  END tl_d_uart_o[91]
  PIN tl_d_uart_o[92]
    DIRECTION OUTPUT ;
    USE SIGNAL ;
    ANTENNADIFFAREA 0.897600 ;
    PORT
      LAYER Metal3 ;
        RECT 499.440 403.200 500.000 403.760 ;
    END
  END tl_d_uart_o[92]
  PIN tl_d_uart_o[93]
    DIRECTION OUTPUT ;
    USE SIGNAL ;
    ANTENNADIFFAREA 0.897600 ;
    PORT
      LAYER Metal3 ;
        RECT 499.440 405.440 500.000 406.000 ;
    END
  END tl_d_uart_o[93]
  PIN tl_d_uart_o[94]
    DIRECTION OUTPUT ;
    USE SIGNAL ;
    ANTENNADIFFAREA 0.897600 ;
    PORT
      LAYER Metal3 ;
        RECT 499.440 407.680 500.000 408.240 ;
    END
  END tl_d_uart_o[94]
  PIN tl_d_uart_o[95]
    DIRECTION OUTPUT ;
    USE SIGNAL ;
    ANTENNADIFFAREA 0.897600 ;
    PORT
      LAYER Metal3 ;
        RECT 499.440 409.920 500.000 410.480 ;
    END
  END tl_d_uart_o[95]
  PIN tl_d_uart_o[96]
    DIRECTION OUTPUT ;
    USE SIGNAL ;
    ANTENNADIFFAREA 0.897600 ;
    PORT
      LAYER Metal3 ;
        RECT 499.440 412.160 500.000 412.720 ;
    END
  END tl_d_uart_o[96]
  PIN tl_d_uart_o[97]
    DIRECTION OUTPUT ;
    USE SIGNAL ;
    ANTENNADIFFAREA 0.897600 ;
    PORT
      LAYER Metal3 ;
        RECT 499.440 414.400 500.000 414.960 ;
    END
  END tl_d_uart_o[97]
  PIN tl_d_uart_o[98]
    DIRECTION OUTPUT ;
    USE SIGNAL ;
    ANTENNADIFFAREA 0.897600 ;
    PORT
      LAYER Metal3 ;
        RECT 499.440 416.640 500.000 417.200 ;
    END
  END tl_d_uart_o[98]
  PIN tl_d_uart_o[99]
    DIRECTION OUTPUT ;
    USE SIGNAL ;
    ANTENNADIFFAREA 0.897600 ;
    PORT
      LAYER Metal3 ;
        RECT 499.440 418.880 500.000 419.440 ;
    END
  END tl_d_uart_o[99]
  PIN tl_d_uart_o[9]
    DIRECTION OUTPUT ;
    USE SIGNAL ;
    ANTENNADIFFAREA 0.897600 ;
    PORT
      LAYER Metal3 ;
        RECT 499.440 217.280 500.000 217.840 ;
    END
  END tl_d_uart_o[9]
  PIN tl_h_d_i[0]
    DIRECTION INPUT ;
    USE SIGNAL ;
    ANTENNAGATEAREA 0.726000 ;
    PORT
      LAYER Metal3 ;
        RECT 0.000 248.640 0.560 249.200 ;
    END
  END tl_h_d_i[0]
  PIN tl_h_d_i[100]
    DIRECTION INPUT ;
    USE SIGNAL ;
    ANTENNAGATEAREA 0.396000 ;
    PORT
      LAYER Metal3 ;
        RECT 0.000 360.640 0.560 361.200 ;
    END
  END tl_h_d_i[100]
  PIN tl_h_d_i[101]
    DIRECTION INPUT ;
    USE SIGNAL ;
    ANTENNAGATEAREA 0.396000 ;
    PORT
      LAYER Metal3 ;
        RECT 0.000 361.760 0.560 362.320 ;
    END
  END tl_h_d_i[101]
  PIN tl_h_d_i[102]
    DIRECTION INPUT ;
    USE SIGNAL ;
    ANTENNAGATEAREA 0.396000 ;
    PORT
      LAYER Metal3 ;
        RECT 0.000 362.880 0.560 363.440 ;
    END
  END tl_h_d_i[102]
  PIN tl_h_d_i[103]
    DIRECTION INPUT ;
    USE SIGNAL ;
    ANTENNAGATEAREA 0.396000 ;
    PORT
      LAYER Metal3 ;
        RECT 0.000 364.000 0.560 364.560 ;
    END
  END tl_h_d_i[103]
  PIN tl_h_d_i[104]
    DIRECTION INPUT ;
    USE SIGNAL ;
    ANTENNAGATEAREA 0.726000 ;
    PORT
      LAYER Metal3 ;
        RECT 0.000 365.120 0.560 365.680 ;
    END
  END tl_h_d_i[104]
  PIN tl_h_d_i[105]
    DIRECTION INPUT ;
    USE SIGNAL ;
    ANTENNAGATEAREA 0.726000 ;
    PORT
      LAYER Metal3 ;
        RECT 0.000 366.240 0.560 366.800 ;
    END
  END tl_h_d_i[105]
  PIN tl_h_d_i[106]
    DIRECTION INPUT ;
    USE SIGNAL ;
    ANTENNAGATEAREA 0.726000 ;
    PORT
      LAYER Metal3 ;
        RECT 0.000 367.360 0.560 367.920 ;
    END
  END tl_h_d_i[106]
  PIN tl_h_d_i[107]
    DIRECTION INPUT ;
    USE SIGNAL ;
    ANTENNAGATEAREA 0.396000 ;
    PORT
      LAYER Metal3 ;
        RECT 0.000 368.480 0.560 369.040 ;
    END
  END tl_h_d_i[107]
  PIN tl_h_d_i[108]
    DIRECTION INPUT ;
    USE SIGNAL ;
    ANTENNAGATEAREA 0.396000 ;
    PORT
      LAYER Metal3 ;
        RECT 0.000 369.600 0.560 370.160 ;
    END
  END tl_h_d_i[108]
  PIN tl_h_d_i[109]
    DIRECTION INPUT ;
    USE SIGNAL ;
    ANTENNAGATEAREA 0.396000 ;
    PORT
      LAYER Metal3 ;
        RECT 0.000 370.720 0.560 371.280 ;
    END
  END tl_h_d_i[109]
  PIN tl_h_d_i[10]
    DIRECTION INPUT ;
    USE SIGNAL ;
    ANTENNAGATEAREA 0.396000 ;
    PORT
      LAYER Metal3 ;
        RECT 0.000 259.840 0.560 260.400 ;
    END
  END tl_h_d_i[10]
  PIN tl_h_d_i[110]
    DIRECTION INPUT ;
    USE SIGNAL ;
    ANTENNAGATEAREA 0.726000 ;
    PORT
      LAYER Metal3 ;
        RECT 0.000 371.840 0.560 372.400 ;
    END
  END tl_h_d_i[110]
  PIN tl_h_d_i[111]
    DIRECTION INPUT ;
    USE SIGNAL ;
    ANTENNAGATEAREA 0.726000 ;
    PORT
      LAYER Metal3 ;
        RECT 0.000 372.960 0.560 373.520 ;
    END
  END tl_h_d_i[111]
  PIN tl_h_d_i[112]
    DIRECTION INPUT ;
    USE SIGNAL ;
    ANTENNAGATEAREA 0.726000 ;
    PORT
      LAYER Metal3 ;
        RECT 0.000 374.080 0.560 374.640 ;
    END
  END tl_h_d_i[112]
  PIN tl_h_d_i[113]
    DIRECTION INPUT ;
    USE SIGNAL ;
    ANTENNAGATEAREA 0.396000 ;
    PORT
      LAYER Metal3 ;
        RECT 0.000 375.200 0.560 375.760 ;
    END
  END tl_h_d_i[113]
  PIN tl_h_d_i[11]
    DIRECTION INPUT ;
    USE SIGNAL ;
    ANTENNAGATEAREA 0.396000 ;
    PORT
      LAYER Metal3 ;
        RECT 0.000 260.960 0.560 261.520 ;
    END
  END tl_h_d_i[11]
  PIN tl_h_d_i[12]
    DIRECTION INPUT ;
    USE SIGNAL ;
    ANTENNAGATEAREA 0.396000 ;
    PORT
      LAYER Metal3 ;
        RECT 0.000 262.080 0.560 262.640 ;
    END
  END tl_h_d_i[12]
  PIN tl_h_d_i[13]
    DIRECTION INPUT ;
    USE SIGNAL ;
    ANTENNAGATEAREA 0.396000 ;
    PORT
      LAYER Metal3 ;
        RECT 0.000 263.200 0.560 263.760 ;
    END
  END tl_h_d_i[13]
  PIN tl_h_d_i[14]
    DIRECTION INPUT ;
    USE SIGNAL ;
    ANTENNAGATEAREA 0.396000 ;
    PORT
      LAYER Metal3 ;
        RECT 0.000 264.320 0.560 264.880 ;
    END
  END tl_h_d_i[14]
  PIN tl_h_d_i[15]
    DIRECTION INPUT ;
    USE SIGNAL ;
    ANTENNAGATEAREA 0.726000 ;
    PORT
      LAYER Metal3 ;
        RECT 0.000 265.440 0.560 266.000 ;
    END
  END tl_h_d_i[15]
  PIN tl_h_d_i[16]
    DIRECTION INPUT ;
    USE SIGNAL ;
    ANTENNAGATEAREA 0.726000 ;
    PORT
      LAYER Metal3 ;
        RECT 0.000 266.560 0.560 267.120 ;
    END
  END tl_h_d_i[16]
  PIN tl_h_d_i[17]
    DIRECTION INPUT ;
    USE SIGNAL ;
    ANTENNAGATEAREA 0.726000 ;
    PORT
      LAYER Metal3 ;
        RECT 0.000 267.680 0.560 268.240 ;
    END
  END tl_h_d_i[17]
  PIN tl_h_d_i[18]
    DIRECTION INPUT ;
    USE SIGNAL ;
    ANTENNAGATEAREA 0.726000 ;
    PORT
      LAYER Metal3 ;
        RECT 0.000 268.800 0.560 269.360 ;
    END
  END tl_h_d_i[18]
  PIN tl_h_d_i[19]
    DIRECTION INPUT ;
    USE SIGNAL ;
    ANTENNAGATEAREA 0.726000 ;
    PORT
      LAYER Metal3 ;
        RECT 0.000 269.920 0.560 270.480 ;
    END
  END tl_h_d_i[19]
  PIN tl_h_d_i[1]
    DIRECTION INPUT ;
    USE SIGNAL ;
    ANTENNAGATEAREA 0.396000 ;
    PORT
      LAYER Metal3 ;
        RECT 0.000 249.760 0.560 250.320 ;
    END
  END tl_h_d_i[1]
  PIN tl_h_d_i[20]
    DIRECTION INPUT ;
    USE SIGNAL ;
    ANTENNAGATEAREA 0.726000 ;
    PORT
      LAYER Metal3 ;
        RECT 0.000 271.040 0.560 271.600 ;
    END
  END tl_h_d_i[20]
  PIN tl_h_d_i[21]
    DIRECTION INPUT ;
    USE SIGNAL ;
    ANTENNAGATEAREA 0.726000 ;
    PORT
      LAYER Metal3 ;
        RECT 0.000 272.160 0.560 272.720 ;
    END
  END tl_h_d_i[21]
  PIN tl_h_d_i[22]
    DIRECTION INPUT ;
    USE SIGNAL ;
    ANTENNAGATEAREA 0.726000 ;
    PORT
      LAYER Metal3 ;
        RECT 0.000 273.280 0.560 273.840 ;
    END
  END tl_h_d_i[22]
  PIN tl_h_d_i[23]
    DIRECTION INPUT ;
    USE SIGNAL ;
    ANTENNAGATEAREA 0.726000 ;
    PORT
      LAYER Metal3 ;
        RECT 0.000 274.400 0.560 274.960 ;
    END
  END tl_h_d_i[23]
  PIN tl_h_d_i[24]
    DIRECTION INPUT ;
    USE SIGNAL ;
    ANTENNAGATEAREA 0.396000 ;
    PORT
      LAYER Metal3 ;
        RECT 0.000 275.520 0.560 276.080 ;
    END
  END tl_h_d_i[24]
  PIN tl_h_d_i[25]
    DIRECTION INPUT ;
    USE SIGNAL ;
    ANTENNAGATEAREA 0.396000 ;
    PORT
      LAYER Metal3 ;
        RECT 0.000 276.640 0.560 277.200 ;
    END
  END tl_h_d_i[25]
  PIN tl_h_d_i[26]
    DIRECTION INPUT ;
    USE SIGNAL ;
    ANTENNAGATEAREA 0.396000 ;
    PORT
      LAYER Metal3 ;
        RECT 0.000 277.760 0.560 278.320 ;
    END
  END tl_h_d_i[26]
  PIN tl_h_d_i[27]
    DIRECTION INPUT ;
    USE SIGNAL ;
    ANTENNAGATEAREA 0.396000 ;
    PORT
      LAYER Metal3 ;
        RECT 0.000 278.880 0.560 279.440 ;
    END
  END tl_h_d_i[27]
  PIN tl_h_d_i[28]
    DIRECTION INPUT ;
    USE SIGNAL ;
    ANTENNAGATEAREA 0.396000 ;
    PORT
      LAYER Metal3 ;
        RECT 0.000 280.000 0.560 280.560 ;
    END
  END tl_h_d_i[28]
  PIN tl_h_d_i[29]
    DIRECTION INPUT ;
    USE SIGNAL ;
    ANTENNAGATEAREA 0.396000 ;
    PORT
      LAYER Metal3 ;
        RECT 0.000 281.120 0.560 281.680 ;
    END
  END tl_h_d_i[29]
  PIN tl_h_d_i[2]
    DIRECTION INPUT ;
    USE SIGNAL ;
    ANTENNAGATEAREA 0.396000 ;
    PORT
      LAYER Metal3 ;
        RECT 0.000 250.880 0.560 251.440 ;
    END
  END tl_h_d_i[2]
  PIN tl_h_d_i[30]
    DIRECTION INPUT ;
    USE SIGNAL ;
    ANTENNAGATEAREA 0.396000 ;
    PORT
      LAYER Metal3 ;
        RECT 0.000 282.240 0.560 282.800 ;
    END
  END tl_h_d_i[30]
  PIN tl_h_d_i[31]
    DIRECTION INPUT ;
    USE SIGNAL ;
    ANTENNAGATEAREA 0.396000 ;
    PORT
      LAYER Metal3 ;
        RECT 0.000 283.360 0.560 283.920 ;
    END
  END tl_h_d_i[31]
  PIN tl_h_d_i[32]
    DIRECTION INPUT ;
    USE SIGNAL ;
    ANTENNAGATEAREA 0.396000 ;
    PORT
      LAYER Metal3 ;
        RECT 0.000 284.480 0.560 285.040 ;
    END
  END tl_h_d_i[32]
  PIN tl_h_d_i[33]
    DIRECTION INPUT ;
    USE SIGNAL ;
    ANTENNAGATEAREA 0.396000 ;
    PORT
      LAYER Metal3 ;
        RECT 0.000 285.600 0.560 286.160 ;
    END
  END tl_h_d_i[33]
  PIN tl_h_d_i[34]
    DIRECTION INPUT ;
    USE SIGNAL ;
    ANTENNAGATEAREA 0.396000 ;
    PORT
      LAYER Metal3 ;
        RECT 0.000 286.720 0.560 287.280 ;
    END
  END tl_h_d_i[34]
  PIN tl_h_d_i[35]
    DIRECTION INPUT ;
    USE SIGNAL ;
    ANTENNAGATEAREA 0.396000 ;
    PORT
      LAYER Metal3 ;
        RECT 0.000 287.840 0.560 288.400 ;
    END
  END tl_h_d_i[35]
  PIN tl_h_d_i[36]
    DIRECTION INPUT ;
    USE SIGNAL ;
    ANTENNAGATEAREA 0.396000 ;
    PORT
      LAYER Metal3 ;
        RECT 0.000 288.960 0.560 289.520 ;
    END
  END tl_h_d_i[36]
  PIN tl_h_d_i[37]
    DIRECTION INPUT ;
    USE SIGNAL ;
    ANTENNAGATEAREA 0.396000 ;
    PORT
      LAYER Metal3 ;
        RECT 0.000 290.080 0.560 290.640 ;
    END
  END tl_h_d_i[37]
  PIN tl_h_d_i[38]
    DIRECTION INPUT ;
    USE SIGNAL ;
    ANTENNAGATEAREA 0.396000 ;
    PORT
      LAYER Metal3 ;
        RECT 0.000 291.200 0.560 291.760 ;
    END
  END tl_h_d_i[38]
  PIN tl_h_d_i[39]
    DIRECTION INPUT ;
    USE SIGNAL ;
    ANTENNAGATEAREA 0.396000 ;
    PORT
      LAYER Metal3 ;
        RECT 0.000 292.320 0.560 292.880 ;
    END
  END tl_h_d_i[39]
  PIN tl_h_d_i[3]
    DIRECTION INPUT ;
    USE SIGNAL ;
    ANTENNAGATEAREA 0.396000 ;
    PORT
      LAYER Metal3 ;
        RECT 0.000 252.000 0.560 252.560 ;
    END
  END tl_h_d_i[3]
  PIN tl_h_d_i[40]
    DIRECTION INPUT ;
    USE SIGNAL ;
    ANTENNAGATEAREA 0.396000 ;
    PORT
      LAYER Metal3 ;
        RECT 0.000 293.440 0.560 294.000 ;
    END
  END tl_h_d_i[40]
  PIN tl_h_d_i[41]
    DIRECTION INPUT ;
    USE SIGNAL ;
    ANTENNAGATEAREA 0.396000 ;
    PORT
      LAYER Metal3 ;
        RECT 0.000 294.560 0.560 295.120 ;
    END
  END tl_h_d_i[41]
  PIN tl_h_d_i[42]
    DIRECTION INPUT ;
    USE SIGNAL ;
    ANTENNAGATEAREA 0.396000 ;
    PORT
      LAYER Metal3 ;
        RECT 0.000 295.680 0.560 296.240 ;
    END
  END tl_h_d_i[42]
  PIN tl_h_d_i[43]
    DIRECTION INPUT ;
    USE SIGNAL ;
    ANTENNAGATEAREA 0.396000 ;
    PORT
      LAYER Metal3 ;
        RECT 0.000 296.800 0.560 297.360 ;
    END
  END tl_h_d_i[43]
  PIN tl_h_d_i[44]
    DIRECTION INPUT ;
    USE SIGNAL ;
    ANTENNAGATEAREA 0.396000 ;
    PORT
      LAYER Metal3 ;
        RECT 0.000 297.920 0.560 298.480 ;
    END
  END tl_h_d_i[44]
  PIN tl_h_d_i[45]
    DIRECTION INPUT ;
    USE SIGNAL ;
    ANTENNAGATEAREA 0.396000 ;
    PORT
      LAYER Metal3 ;
        RECT 0.000 299.040 0.560 299.600 ;
    END
  END tl_h_d_i[45]
  PIN tl_h_d_i[46]
    DIRECTION INPUT ;
    USE SIGNAL ;
    ANTENNAGATEAREA 0.396000 ;
    PORT
      LAYER Metal3 ;
        RECT 0.000 300.160 0.560 300.720 ;
    END
  END tl_h_d_i[46]
  PIN tl_h_d_i[47]
    DIRECTION INPUT ;
    USE SIGNAL ;
    ANTENNAGATEAREA 0.396000 ;
    PORT
      LAYER Metal3 ;
        RECT 0.000 301.280 0.560 301.840 ;
    END
  END tl_h_d_i[47]
  PIN tl_h_d_i[48]
    DIRECTION INPUT ;
    USE SIGNAL ;
    ANTENNAGATEAREA 0.396000 ;
    PORT
      LAYER Metal3 ;
        RECT 0.000 302.400 0.560 302.960 ;
    END
  END tl_h_d_i[48]
  PIN tl_h_d_i[49]
    DIRECTION INPUT ;
    USE SIGNAL ;
    ANTENNAGATEAREA 0.396000 ;
    PORT
      LAYER Metal3 ;
        RECT 0.000 303.520 0.560 304.080 ;
    END
  END tl_h_d_i[49]
  PIN tl_h_d_i[4]
    DIRECTION INPUT ;
    USE SIGNAL ;
    ANTENNAGATEAREA 0.396000 ;
    PORT
      LAYER Metal3 ;
        RECT 0.000 253.120 0.560 253.680 ;
    END
  END tl_h_d_i[4]
  PIN tl_h_d_i[50]
    DIRECTION INPUT ;
    USE SIGNAL ;
    ANTENNAGATEAREA 0.396000 ;
    PORT
      LAYER Metal3 ;
        RECT 0.000 304.640 0.560 305.200 ;
    END
  END tl_h_d_i[50]
  PIN tl_h_d_i[51]
    DIRECTION INPUT ;
    USE SIGNAL ;
    ANTENNAGATEAREA 0.396000 ;
    PORT
      LAYER Metal3 ;
        RECT 0.000 305.760 0.560 306.320 ;
    END
  END tl_h_d_i[51]
  PIN tl_h_d_i[52]
    DIRECTION INPUT ;
    USE SIGNAL ;
    ANTENNAGATEAREA 0.396000 ;
    PORT
      LAYER Metal3 ;
        RECT 0.000 306.880 0.560 307.440 ;
    END
  END tl_h_d_i[52]
  PIN tl_h_d_i[53]
    DIRECTION INPUT ;
    USE SIGNAL ;
    ANTENNAGATEAREA 0.396000 ;
    PORT
      LAYER Metal3 ;
        RECT 0.000 308.000 0.560 308.560 ;
    END
  END tl_h_d_i[53]
  PIN tl_h_d_i[54]
    DIRECTION INPUT ;
    USE SIGNAL ;
    ANTENNAGATEAREA 0.396000 ;
    PORT
      LAYER Metal3 ;
        RECT 0.000 309.120 0.560 309.680 ;
    END
  END tl_h_d_i[54]
  PIN tl_h_d_i[55]
    DIRECTION INPUT ;
    USE SIGNAL ;
    ANTENNAGATEAREA 0.396000 ;
    PORT
      LAYER Metal3 ;
        RECT 0.000 310.240 0.560 310.800 ;
    END
  END tl_h_d_i[55]
  PIN tl_h_d_i[56]
    DIRECTION INPUT ;
    USE SIGNAL ;
    ANTENNAGATEAREA 0.396000 ;
    PORT
      LAYER Metal3 ;
        RECT 0.000 311.360 0.560 311.920 ;
    END
  END tl_h_d_i[56]
  PIN tl_h_d_i[57]
    DIRECTION INPUT ;
    USE SIGNAL ;
    ANTENNAGATEAREA 0.396000 ;
    PORT
      LAYER Metal3 ;
        RECT 0.000 312.480 0.560 313.040 ;
    END
  END tl_h_d_i[57]
  PIN tl_h_d_i[58]
    DIRECTION INPUT ;
    USE SIGNAL ;
    ANTENNAGATEAREA 0.396000 ;
    PORT
      LAYER Metal3 ;
        RECT 0.000 313.600 0.560 314.160 ;
    END
  END tl_h_d_i[58]
  PIN tl_h_d_i[59]
    DIRECTION INPUT ;
    USE SIGNAL ;
    ANTENNAGATEAREA 0.396000 ;
    PORT
      LAYER Metal3 ;
        RECT 0.000 314.720 0.560 315.280 ;
    END
  END tl_h_d_i[59]
  PIN tl_h_d_i[5]
    DIRECTION INPUT ;
    USE SIGNAL ;
    ANTENNAGATEAREA 0.396000 ;
    PORT
      LAYER Metal3 ;
        RECT 0.000 254.240 0.560 254.800 ;
    END
  END tl_h_d_i[5]
  PIN tl_h_d_i[60]
    DIRECTION INPUT ;
    USE SIGNAL ;
    ANTENNAGATEAREA 0.396000 ;
    PORT
      LAYER Metal3 ;
        RECT 0.000 315.840 0.560 316.400 ;
    END
  END tl_h_d_i[60]
  PIN tl_h_d_i[61]
    DIRECTION INPUT ;
    USE SIGNAL ;
    ANTENNAGATEAREA 0.726000 ;
    PORT
      LAYER Metal3 ;
        RECT 0.000 316.960 0.560 317.520 ;
    END
  END tl_h_d_i[61]
  PIN tl_h_d_i[62]
    DIRECTION INPUT ;
    USE SIGNAL ;
    ANTENNAGATEAREA 0.726000 ;
    PORT
      LAYER Metal3 ;
        RECT 0.000 318.080 0.560 318.640 ;
    END
  END tl_h_d_i[62]
  PIN tl_h_d_i[63]
    DIRECTION INPUT ;
    USE SIGNAL ;
    ANTENNAGATEAREA 0.726000 ;
    PORT
      LAYER Metal3 ;
        RECT 0.000 319.200 0.560 319.760 ;
    END
  END tl_h_d_i[63]
  PIN tl_h_d_i[64]
    DIRECTION INPUT ;
    USE SIGNAL ;
    ANTENNAGATEAREA 0.726000 ;
    PORT
      LAYER Metal3 ;
        RECT 0.000 320.320 0.560 320.880 ;
    END
  END tl_h_d_i[64]
  PIN tl_h_d_i[65]
    DIRECTION INPUT ;
    USE SIGNAL ;
    ANTENNAGATEAREA 0.726000 ;
    PORT
      LAYER Metal3 ;
        RECT 0.000 321.440 0.560 322.000 ;
    END
  END tl_h_d_i[65]
  PIN tl_h_d_i[66]
    DIRECTION INPUT ;
    USE SIGNAL ;
    ANTENNAGATEAREA 0.726000 ;
    PORT
      LAYER Metal3 ;
        RECT 0.000 322.560 0.560 323.120 ;
    END
  END tl_h_d_i[66]
  PIN tl_h_d_i[67]
    DIRECTION INPUT ;
    USE SIGNAL ;
    ANTENNAGATEAREA 0.726000 ;
    PORT
      LAYER Metal3 ;
        RECT 0.000 323.680 0.560 324.240 ;
    END
  END tl_h_d_i[67]
  PIN tl_h_d_i[68]
    DIRECTION INPUT ;
    USE SIGNAL ;
    ANTENNAGATEAREA 0.726000 ;
    PORT
      LAYER Metal3 ;
        RECT 0.000 324.800 0.560 325.360 ;
    END
  END tl_h_d_i[68]
  PIN tl_h_d_i[69]
    DIRECTION INPUT ;
    USE SIGNAL ;
    ANTENNAGATEAREA 0.726000 ;
    PORT
      LAYER Metal3 ;
        RECT 0.000 325.920 0.560 326.480 ;
    END
  END tl_h_d_i[69]
  PIN tl_h_d_i[6]
    DIRECTION INPUT ;
    USE SIGNAL ;
    ANTENNAGATEAREA 0.396000 ;
    PORT
      LAYER Metal3 ;
        RECT 0.000 255.360 0.560 255.920 ;
    END
  END tl_h_d_i[6]
  PIN tl_h_d_i[70]
    DIRECTION INPUT ;
    USE SIGNAL ;
    ANTENNAGATEAREA 0.726000 ;
    PORT
      LAYER Metal3 ;
        RECT 0.000 327.040 0.560 327.600 ;
    END
  END tl_h_d_i[70]
  PIN tl_h_d_i[71]
    DIRECTION INPUT ;
    USE SIGNAL ;
    ANTENNAGATEAREA 0.726000 ;
    PORT
      LAYER Metal3 ;
        RECT 0.000 328.160 0.560 328.720 ;
    END
  END tl_h_d_i[71]
  PIN tl_h_d_i[72]
    DIRECTION INPUT ;
    USE SIGNAL ;
    ANTENNAGATEAREA 0.726000 ;
    PORT
      LAYER Metal3 ;
        RECT 0.000 329.280 0.560 329.840 ;
    END
  END tl_h_d_i[72]
  PIN tl_h_d_i[73]
    DIRECTION INPUT ;
    USE SIGNAL ;
    ANTENNAGATEAREA 0.726000 ;
    PORT
      LAYER Metal3 ;
        RECT 0.000 330.400 0.560 330.960 ;
    END
  END tl_h_d_i[73]
  PIN tl_h_d_i[74]
    DIRECTION INPUT ;
    USE SIGNAL ;
    ANTENNAGATEAREA 0.726000 ;
    PORT
      LAYER Metal3 ;
        RECT 0.000 331.520 0.560 332.080 ;
    END
  END tl_h_d_i[74]
  PIN tl_h_d_i[75]
    DIRECTION INPUT ;
    USE SIGNAL ;
    ANTENNAGATEAREA 0.726000 ;
    PORT
      LAYER Metal3 ;
        RECT 0.000 332.640 0.560 333.200 ;
    END
  END tl_h_d_i[75]
  PIN tl_h_d_i[76]
    DIRECTION INPUT ;
    USE SIGNAL ;
    ANTENNAGATEAREA 0.726000 ;
    PORT
      LAYER Metal3 ;
        RECT 0.000 333.760 0.560 334.320 ;
    END
  END tl_h_d_i[76]
  PIN tl_h_d_i[77]
    DIRECTION INPUT ;
    USE SIGNAL ;
    ANTENNAGATEAREA 0.726000 ;
    PORT
      LAYER Metal3 ;
        RECT 0.000 334.880 0.560 335.440 ;
    END
  END tl_h_d_i[77]
  PIN tl_h_d_i[78]
    DIRECTION INPUT ;
    USE SIGNAL ;
    ANTENNAGATEAREA 0.726000 ;
    PORT
      LAYER Metal3 ;
        RECT 0.000 336.000 0.560 336.560 ;
    END
  END tl_h_d_i[78]
  PIN tl_h_d_i[79]
    DIRECTION INPUT ;
    USE SIGNAL ;
    ANTENNAGATEAREA 0.726000 ;
    PORT
      LAYER Metal3 ;
        RECT 0.000 337.120 0.560 337.680 ;
    END
  END tl_h_d_i[79]
  PIN tl_h_d_i[7]
    DIRECTION INPUT ;
    USE SIGNAL ;
    ANTENNAGATEAREA 0.396000 ;
    PORT
      LAYER Metal3 ;
        RECT 0.000 256.480 0.560 257.040 ;
    END
  END tl_h_d_i[7]
  PIN tl_h_d_i[80]
    DIRECTION INPUT ;
    USE SIGNAL ;
    ANTENNAGATEAREA 0.726000 ;
    PORT
      LAYER Metal3 ;
        RECT 0.000 338.240 0.560 338.800 ;
    END
  END tl_h_d_i[80]
  PIN tl_h_d_i[81]
    DIRECTION INPUT ;
    USE SIGNAL ;
    ANTENNAGATEAREA 0.726000 ;
    PORT
      LAYER Metal3 ;
        RECT 0.000 339.360 0.560 339.920 ;
    END
  END tl_h_d_i[81]
  PIN tl_h_d_i[82]
    DIRECTION INPUT ;
    USE SIGNAL ;
    ANTENNAGATEAREA 0.726000 ;
    PORT
      LAYER Metal3 ;
        RECT 0.000 340.480 0.560 341.040 ;
    END
  END tl_h_d_i[82]
  PIN tl_h_d_i[83]
    DIRECTION INPUT ;
    USE SIGNAL ;
    ANTENNAGATEAREA 0.726000 ;
    PORT
      LAYER Metal3 ;
        RECT 0.000 341.600 0.560 342.160 ;
    END
  END tl_h_d_i[83]
  PIN tl_h_d_i[84]
    DIRECTION INPUT ;
    USE SIGNAL ;
    ANTENNAGATEAREA 0.726000 ;
    PORT
      LAYER Metal3 ;
        RECT 0.000 342.720 0.560 343.280 ;
    END
  END tl_h_d_i[84]
  PIN tl_h_d_i[85]
    DIRECTION INPUT ;
    USE SIGNAL ;
    ANTENNAGATEAREA 0.726000 ;
    PORT
      LAYER Metal3 ;
        RECT 0.000 343.840 0.560 344.400 ;
    END
  END tl_h_d_i[85]
  PIN tl_h_d_i[86]
    DIRECTION INPUT ;
    USE SIGNAL ;
    ANTENNAGATEAREA 0.726000 ;
    PORT
      LAYER Metal3 ;
        RECT 0.000 344.960 0.560 345.520 ;
    END
  END tl_h_d_i[86]
  PIN tl_h_d_i[87]
    DIRECTION INPUT ;
    USE SIGNAL ;
    ANTENNAGATEAREA 0.726000 ;
    PORT
      LAYER Metal3 ;
        RECT 0.000 346.080 0.560 346.640 ;
    END
  END tl_h_d_i[87]
  PIN tl_h_d_i[88]
    DIRECTION INPUT ;
    USE SIGNAL ;
    ANTENNAGATEAREA 0.726000 ;
    PORT
      LAYER Metal3 ;
        RECT 0.000 347.200 0.560 347.760 ;
    END
  END tl_h_d_i[88]
  PIN tl_h_d_i[89]
    DIRECTION INPUT ;
    USE SIGNAL ;
    ANTENNAGATEAREA 0.726000 ;
    PORT
      LAYER Metal3 ;
        RECT 0.000 348.320 0.560 348.880 ;
    END
  END tl_h_d_i[89]
  PIN tl_h_d_i[8]
    DIRECTION INPUT ;
    USE SIGNAL ;
    ANTENNAGATEAREA 0.396000 ;
    PORT
      LAYER Metal3 ;
        RECT 0.000 257.600 0.560 258.160 ;
    END
  END tl_h_d_i[8]
  PIN tl_h_d_i[90]
    DIRECTION INPUT ;
    USE SIGNAL ;
    ANTENNAGATEAREA 0.726000 ;
    PORT
      LAYER Metal3 ;
        RECT 0.000 349.440 0.560 350.000 ;
    END
  END tl_h_d_i[90]
  PIN tl_h_d_i[91]
    DIRECTION INPUT ;
    USE SIGNAL ;
    ANTENNAGATEAREA 0.726000 ;
    PORT
      LAYER Metal3 ;
        RECT 0.000 350.560 0.560 351.120 ;
    END
  END tl_h_d_i[91]
  PIN tl_h_d_i[92]
    DIRECTION INPUT ;
    USE SIGNAL ;
    ANTENNAGATEAREA 0.726000 ;
    PORT
      LAYER Metal3 ;
        RECT 0.000 351.680 0.560 352.240 ;
    END
  END tl_h_d_i[92]
  PIN tl_h_d_i[93]
    DIRECTION INPUT ;
    USE SIGNAL ;
    ANTENNAGATEAREA 0.726000 ;
    PORT
      LAYER Metal3 ;
        RECT 0.000 352.800 0.560 353.360 ;
    END
  END tl_h_d_i[93]
  PIN tl_h_d_i[94]
    DIRECTION INPUT ;
    USE SIGNAL ;
    ANTENNAGATEAREA 0.726000 ;
    PORT
      LAYER Metal3 ;
        RECT 0.000 353.920 0.560 354.480 ;
    END
  END tl_h_d_i[94]
  PIN tl_h_d_i[95]
    DIRECTION INPUT ;
    USE SIGNAL ;
    ANTENNAGATEAREA 0.726000 ;
    PORT
      LAYER Metal3 ;
        RECT 0.000 355.040 0.560 355.600 ;
    END
  END tl_h_d_i[95]
  PIN tl_h_d_i[96]
    DIRECTION INPUT ;
    USE SIGNAL ;
    ANTENNAGATEAREA 0.726000 ;
    PORT
      LAYER Metal3 ;
        RECT 0.000 356.160 0.560 356.720 ;
    END
  END tl_h_d_i[96]
  PIN tl_h_d_i[97]
    DIRECTION INPUT ;
    USE SIGNAL ;
    ANTENNAGATEAREA 0.396000 ;
    PORT
      LAYER Metal3 ;
        RECT 0.000 357.280 0.560 357.840 ;
    END
  END tl_h_d_i[97]
  PIN tl_h_d_i[98]
    DIRECTION INPUT ;
    USE SIGNAL ;
    ANTENNAGATEAREA 0.396000 ;
    PORT
      LAYER Metal3 ;
        RECT 0.000 358.400 0.560 358.960 ;
    END
  END tl_h_d_i[98]
  PIN tl_h_d_i[99]
    DIRECTION INPUT ;
    USE SIGNAL ;
    ANTENNAGATEAREA 0.396000 ;
    PORT
      LAYER Metal3 ;
        RECT 0.000 359.520 0.560 360.080 ;
    END
  END tl_h_d_i[99]
  PIN tl_h_d_i[9]
    DIRECTION INPUT ;
    USE SIGNAL ;
    ANTENNAGATEAREA 0.396000 ;
    PORT
      LAYER Metal3 ;
        RECT 0.000 258.720 0.560 259.280 ;
    END
  END tl_h_d_i[9]
  PIN tl_h_d_o[0]
    DIRECTION OUTPUT ;
    USE SIGNAL ;
    ANTENNADIFFAREA 0.897600 ;
    PORT
      LAYER Metal3 ;
        RECT 0.000 376.320 0.560 376.880 ;
    END
  END tl_h_d_o[0]
  PIN tl_h_d_o[10]
    DIRECTION OUTPUT ;
    USE SIGNAL ;
    ANTENNADIFFAREA 0.897600 ;
    PORT
      LAYER Metal3 ;
        RECT 0.000 387.520 0.560 388.080 ;
    END
  END tl_h_d_o[10]
  PIN tl_h_d_o[11]
    DIRECTION OUTPUT ;
    USE SIGNAL ;
    ANTENNADIFFAREA 0.897600 ;
    PORT
      LAYER Metal3 ;
        RECT 0.000 388.640 0.560 389.200 ;
    END
  END tl_h_d_o[11]
  PIN tl_h_d_o[12]
    DIRECTION OUTPUT ;
    USE SIGNAL ;
    ANTENNADIFFAREA 0.897600 ;
    PORT
      LAYER Metal3 ;
        RECT 0.000 389.760 0.560 390.320 ;
    END
  END tl_h_d_o[12]
  PIN tl_h_d_o[13]
    DIRECTION OUTPUT ;
    USE SIGNAL ;
    ANTENNADIFFAREA 0.897600 ;
    PORT
      LAYER Metal3 ;
        RECT 0.000 390.880 0.560 391.440 ;
    END
  END tl_h_d_o[13]
  PIN tl_h_d_o[14]
    DIRECTION OUTPUT ;
    USE SIGNAL ;
    ANTENNADIFFAREA 0.897600 ;
    PORT
      LAYER Metal3 ;
        RECT 0.000 392.000 0.560 392.560 ;
    END
  END tl_h_d_o[14]
  PIN tl_h_d_o[15]
    DIRECTION OUTPUT ;
    USE SIGNAL ;
    ANTENNADIFFAREA 0.897600 ;
    PORT
      LAYER Metal3 ;
        RECT 0.000 393.120 0.560 393.680 ;
    END
  END tl_h_d_o[15]
  PIN tl_h_d_o[16]
    DIRECTION OUTPUT ;
    USE SIGNAL ;
    ANTENNADIFFAREA 0.897600 ;
    PORT
      LAYER Metal3 ;
        RECT 0.000 394.240 0.560 394.800 ;
    END
  END tl_h_d_o[16]
  PIN tl_h_d_o[17]
    DIRECTION OUTPUT ;
    USE SIGNAL ;
    ANTENNADIFFAREA 0.897600 ;
    PORT
      LAYER Metal3 ;
        RECT 0.000 395.360 0.560 395.920 ;
    END
  END tl_h_d_o[17]
  PIN tl_h_d_o[18]
    DIRECTION OUTPUT ;
    USE SIGNAL ;
    ANTENNADIFFAREA 0.897600 ;
    PORT
      LAYER Metal3 ;
        RECT 0.000 396.480 0.560 397.040 ;
    END
  END tl_h_d_o[18]
  PIN tl_h_d_o[19]
    DIRECTION OUTPUT ;
    USE SIGNAL ;
    ANTENNADIFFAREA 0.897600 ;
    PORT
      LAYER Metal3 ;
        RECT 0.000 397.600 0.560 398.160 ;
    END
  END tl_h_d_o[19]
  PIN tl_h_d_o[1]
    DIRECTION OUTPUT ;
    USE SIGNAL ;
    ANTENNADIFFAREA 0.897600 ;
    PORT
      LAYER Metal3 ;
        RECT 0.000 377.440 0.560 378.000 ;
    END
  END tl_h_d_o[1]
  PIN tl_h_d_o[20]
    DIRECTION OUTPUT ;
    USE SIGNAL ;
    ANTENNADIFFAREA 0.897600 ;
    PORT
      LAYER Metal3 ;
        RECT 0.000 398.720 0.560 399.280 ;
    END
  END tl_h_d_o[20]
  PIN tl_h_d_o[21]
    DIRECTION OUTPUT ;
    USE SIGNAL ;
    ANTENNADIFFAREA 0.897600 ;
    PORT
      LAYER Metal3 ;
        RECT 0.000 399.840 0.560 400.400 ;
    END
  END tl_h_d_o[21]
  PIN tl_h_d_o[22]
    DIRECTION OUTPUT ;
    USE SIGNAL ;
    ANTENNADIFFAREA 0.897600 ;
    PORT
      LAYER Metal3 ;
        RECT 0.000 400.960 0.560 401.520 ;
    END
  END tl_h_d_o[22]
  PIN tl_h_d_o[23]
    DIRECTION OUTPUT ;
    USE SIGNAL ;
    ANTENNADIFFAREA 0.897600 ;
    PORT
      LAYER Metal3 ;
        RECT 0.000 402.080 0.560 402.640 ;
    END
  END tl_h_d_o[23]
  PIN tl_h_d_o[24]
    DIRECTION OUTPUT ;
    USE SIGNAL ;
    ANTENNADIFFAREA 0.897600 ;
    PORT
      LAYER Metal3 ;
        RECT 0.000 403.200 0.560 403.760 ;
    END
  END tl_h_d_o[24]
  PIN tl_h_d_o[25]
    DIRECTION OUTPUT ;
    USE SIGNAL ;
    ANTENNADIFFAREA 0.897600 ;
    PORT
      LAYER Metal3 ;
        RECT 0.000 404.320 0.560 404.880 ;
    END
  END tl_h_d_o[25]
  PIN tl_h_d_o[26]
    DIRECTION OUTPUT ;
    USE SIGNAL ;
    ANTENNADIFFAREA 0.897600 ;
    PORT
      LAYER Metal3 ;
        RECT 0.000 405.440 0.560 406.000 ;
    END
  END tl_h_d_o[26]
  PIN tl_h_d_o[27]
    DIRECTION OUTPUT ;
    USE SIGNAL ;
    ANTENNADIFFAREA 0.897600 ;
    PORT
      LAYER Metal3 ;
        RECT 0.000 406.560 0.560 407.120 ;
    END
  END tl_h_d_o[27]
  PIN tl_h_d_o[28]
    DIRECTION OUTPUT ;
    USE SIGNAL ;
    ANTENNADIFFAREA 0.897600 ;
    PORT
      LAYER Metal3 ;
        RECT 0.000 407.680 0.560 408.240 ;
    END
  END tl_h_d_o[28]
  PIN tl_h_d_o[29]
    DIRECTION OUTPUT ;
    USE SIGNAL ;
    ANTENNADIFFAREA 0.897600 ;
    PORT
      LAYER Metal3 ;
        RECT 0.000 408.800 0.560 409.360 ;
    END
  END tl_h_d_o[29]
  PIN tl_h_d_o[2]
    DIRECTION OUTPUT ;
    USE SIGNAL ;
    ANTENNADIFFAREA 0.897600 ;
    PORT
      LAYER Metal3 ;
        RECT 0.000 378.560 0.560 379.120 ;
    END
  END tl_h_d_o[2]
  PIN tl_h_d_o[30]
    DIRECTION OUTPUT ;
    USE SIGNAL ;
    ANTENNADIFFAREA 0.897600 ;
    PORT
      LAYER Metal3 ;
        RECT 0.000 409.920 0.560 410.480 ;
    END
  END tl_h_d_o[30]
  PIN tl_h_d_o[31]
    DIRECTION OUTPUT ;
    USE SIGNAL ;
    ANTENNADIFFAREA 0.897600 ;
    PORT
      LAYER Metal3 ;
        RECT 0.000 411.040 0.560 411.600 ;
    END
  END tl_h_d_o[31]
  PIN tl_h_d_o[32]
    DIRECTION OUTPUT ;
    USE SIGNAL ;
    ANTENNADIFFAREA 0.897600 ;
    PORT
      LAYER Metal3 ;
        RECT 0.000 412.160 0.560 412.720 ;
    END
  END tl_h_d_o[32]
  PIN tl_h_d_o[33]
    DIRECTION OUTPUT ;
    USE SIGNAL ;
    ANTENNADIFFAREA 0.897600 ;
    PORT
      LAYER Metal3 ;
        RECT 0.000 413.280 0.560 413.840 ;
    END
  END tl_h_d_o[33]
  PIN tl_h_d_o[34]
    DIRECTION OUTPUT ;
    USE SIGNAL ;
    ANTENNADIFFAREA 0.897600 ;
    PORT
      LAYER Metal3 ;
        RECT 0.000 414.400 0.560 414.960 ;
    END
  END tl_h_d_o[34]
  PIN tl_h_d_o[35]
    DIRECTION OUTPUT ;
    USE SIGNAL ;
    ANTENNADIFFAREA 0.897600 ;
    PORT
      LAYER Metal3 ;
        RECT 0.000 415.520 0.560 416.080 ;
    END
  END tl_h_d_o[35]
  PIN tl_h_d_o[36]
    DIRECTION OUTPUT ;
    USE SIGNAL ;
    ANTENNADIFFAREA 0.897600 ;
    PORT
      LAYER Metal3 ;
        RECT 0.000 416.640 0.560 417.200 ;
    END
  END tl_h_d_o[36]
  PIN tl_h_d_o[37]
    DIRECTION OUTPUT ;
    USE SIGNAL ;
    ANTENNADIFFAREA 0.897600 ;
    PORT
      LAYER Metal3 ;
        RECT 0.000 417.760 0.560 418.320 ;
    END
  END tl_h_d_o[37]
  PIN tl_h_d_o[38]
    DIRECTION OUTPUT ;
    USE SIGNAL ;
    ANTENNADIFFAREA 0.897600 ;
    PORT
      LAYER Metal3 ;
        RECT 0.000 418.880 0.560 419.440 ;
    END
  END tl_h_d_o[38]
  PIN tl_h_d_o[39]
    DIRECTION OUTPUT ;
    USE SIGNAL ;
    ANTENNADIFFAREA 0.897600 ;
    PORT
      LAYER Metal3 ;
        RECT 0.000 420.000 0.560 420.560 ;
    END
  END tl_h_d_o[39]
  PIN tl_h_d_o[3]
    DIRECTION OUTPUT ;
    USE SIGNAL ;
    ANTENNADIFFAREA 0.897600 ;
    PORT
      LAYER Metal3 ;
        RECT 0.000 379.680 0.560 380.240 ;
    END
  END tl_h_d_o[3]
  PIN tl_h_d_o[40]
    DIRECTION OUTPUT ;
    USE SIGNAL ;
    ANTENNADIFFAREA 0.897600 ;
    PORT
      LAYER Metal3 ;
        RECT 0.000 421.120 0.560 421.680 ;
    END
  END tl_h_d_o[40]
  PIN tl_h_d_o[41]
    DIRECTION OUTPUT ;
    USE SIGNAL ;
    ANTENNADIFFAREA 0.897600 ;
    PORT
      LAYER Metal3 ;
        RECT 0.000 422.240 0.560 422.800 ;
    END
  END tl_h_d_o[41]
  PIN tl_h_d_o[42]
    DIRECTION OUTPUT ;
    USE SIGNAL ;
    ANTENNADIFFAREA 0.897600 ;
    PORT
      LAYER Metal3 ;
        RECT 0.000 423.360 0.560 423.920 ;
    END
  END tl_h_d_o[42]
  PIN tl_h_d_o[43]
    DIRECTION OUTPUT ;
    USE SIGNAL ;
    ANTENNADIFFAREA 0.897600 ;
    PORT
      LAYER Metal3 ;
        RECT 0.000 424.480 0.560 425.040 ;
    END
  END tl_h_d_o[43]
  PIN tl_h_d_o[44]
    DIRECTION OUTPUT ;
    USE SIGNAL ;
    ANTENNADIFFAREA 0.897600 ;
    PORT
      LAYER Metal3 ;
        RECT 0.000 425.600 0.560 426.160 ;
    END
  END tl_h_d_o[44]
  PIN tl_h_d_o[45]
    DIRECTION OUTPUT ;
    USE SIGNAL ;
    ANTENNADIFFAREA 0.897600 ;
    PORT
      LAYER Metal3 ;
        RECT 0.000 426.720 0.560 427.280 ;
    END
  END tl_h_d_o[45]
  PIN tl_h_d_o[46]
    DIRECTION OUTPUT ;
    USE SIGNAL ;
    ANTENNADIFFAREA 0.897600 ;
    PORT
      LAYER Metal3 ;
        RECT 0.000 427.840 0.560 428.400 ;
    END
  END tl_h_d_o[46]
  PIN tl_h_d_o[47]
    DIRECTION OUTPUT ;
    USE SIGNAL ;
    ANTENNADIFFAREA 0.897600 ;
    PORT
      LAYER Metal3 ;
        RECT 0.000 428.960 0.560 429.520 ;
    END
  END tl_h_d_o[47]
  PIN tl_h_d_o[48]
    DIRECTION OUTPUT ;
    USE SIGNAL ;
    ANTENNADIFFAREA 0.897600 ;
    PORT
      LAYER Metal3 ;
        RECT 0.000 430.080 0.560 430.640 ;
    END
  END tl_h_d_o[48]
  PIN tl_h_d_o[49]
    DIRECTION OUTPUT ;
    USE SIGNAL ;
    ANTENNADIFFAREA 0.897600 ;
    PORT
      LAYER Metal3 ;
        RECT 0.000 431.200 0.560 431.760 ;
    END
  END tl_h_d_o[49]
  PIN tl_h_d_o[4]
    DIRECTION OUTPUT ;
    USE SIGNAL ;
    ANTENNADIFFAREA 0.897600 ;
    PORT
      LAYER Metal3 ;
        RECT 0.000 380.800 0.560 381.360 ;
    END
  END tl_h_d_o[4]
  PIN tl_h_d_o[50]
    DIRECTION OUTPUT ;
    USE SIGNAL ;
    ANTENNADIFFAREA 0.897600 ;
    PORT
      LAYER Metal3 ;
        RECT 0.000 432.320 0.560 432.880 ;
    END
  END tl_h_d_o[50]
  PIN tl_h_d_o[51]
    DIRECTION OUTPUT ;
    USE SIGNAL ;
    ANTENNADIFFAREA 0.897600 ;
    PORT
      LAYER Metal3 ;
        RECT 0.000 433.440 0.560 434.000 ;
    END
  END tl_h_d_o[51]
  PIN tl_h_d_o[52]
    DIRECTION OUTPUT ;
    USE SIGNAL ;
    ANTENNADIFFAREA 0.897600 ;
    PORT
      LAYER Metal3 ;
        RECT 0.000 434.560 0.560 435.120 ;
    END
  END tl_h_d_o[52]
  PIN tl_h_d_o[53]
    DIRECTION OUTPUT ;
    USE SIGNAL ;
    ANTENNADIFFAREA 0.897600 ;
    PORT
      LAYER Metal3 ;
        RECT 0.000 435.680 0.560 436.240 ;
    END
  END tl_h_d_o[53]
  PIN tl_h_d_o[54]
    DIRECTION OUTPUT ;
    USE SIGNAL ;
    ANTENNADIFFAREA 0.897600 ;
    PORT
      LAYER Metal3 ;
        RECT 0.000 436.800 0.560 437.360 ;
    END
  END tl_h_d_o[54]
  PIN tl_h_d_o[55]
    DIRECTION OUTPUT ;
    USE SIGNAL ;
    ANTENNADIFFAREA 0.897600 ;
    PORT
      LAYER Metal3 ;
        RECT 0.000 437.920 0.560 438.480 ;
    END
  END tl_h_d_o[55]
  PIN tl_h_d_o[56]
    DIRECTION OUTPUT ;
    USE SIGNAL ;
    ANTENNADIFFAREA 0.897600 ;
    PORT
      LAYER Metal3 ;
        RECT 0.000 439.040 0.560 439.600 ;
    END
  END tl_h_d_o[56]
  PIN tl_h_d_o[57]
    DIRECTION OUTPUT ;
    USE SIGNAL ;
    ANTENNADIFFAREA 0.897600 ;
    PORT
      LAYER Metal3 ;
        RECT 0.000 440.160 0.560 440.720 ;
    END
  END tl_h_d_o[57]
  PIN tl_h_d_o[58]
    DIRECTION OUTPUT ;
    USE SIGNAL ;
    ANTENNADIFFAREA 0.897600 ;
    PORT
      LAYER Metal3 ;
        RECT 0.000 441.280 0.560 441.840 ;
    END
  END tl_h_d_o[58]
  PIN tl_h_d_o[59]
    DIRECTION OUTPUT ;
    USE SIGNAL ;
    ANTENNADIFFAREA 0.897600 ;
    PORT
      LAYER Metal3 ;
        RECT 0.000 442.400 0.560 442.960 ;
    END
  END tl_h_d_o[59]
  PIN tl_h_d_o[5]
    DIRECTION OUTPUT ;
    USE SIGNAL ;
    ANTENNADIFFAREA 0.897600 ;
    PORT
      LAYER Metal3 ;
        RECT 0.000 381.920 0.560 382.480 ;
    END
  END tl_h_d_o[5]
  PIN tl_h_d_o[60]
    DIRECTION OUTPUT ;
    USE SIGNAL ;
    ANTENNADIFFAREA 0.897600 ;
    PORT
      LAYER Metal3 ;
        RECT 0.000 443.520 0.560 444.080 ;
    END
  END tl_h_d_o[60]
  PIN tl_h_d_o[61]
    DIRECTION OUTPUT ;
    USE SIGNAL ;
    ANTENNADIFFAREA 0.897600 ;
    PORT
      LAYER Metal3 ;
        RECT 0.000 444.640 0.560 445.200 ;
    END
  END tl_h_d_o[61]
  PIN tl_h_d_o[62]
    DIRECTION OUTPUT ;
    USE SIGNAL ;
    ANTENNADIFFAREA 0.897600 ;
    PORT
      LAYER Metal3 ;
        RECT 0.000 445.760 0.560 446.320 ;
    END
  END tl_h_d_o[62]
  PIN tl_h_d_o[63]
    DIRECTION OUTPUT ;
    USE SIGNAL ;
    ANTENNADIFFAREA 0.897600 ;
    PORT
      LAYER Metal3 ;
        RECT 0.000 446.880 0.560 447.440 ;
    END
  END tl_h_d_o[63]
  PIN tl_h_d_o[64]
    DIRECTION OUTPUT ;
    USE SIGNAL ;
    ANTENNADIFFAREA 0.897600 ;
    PORT
      LAYER Metal3 ;
        RECT 0.000 448.000 0.560 448.560 ;
    END
  END tl_h_d_o[64]
  PIN tl_h_d_o[65]
    DIRECTION OUTPUT ;
    USE SIGNAL ;
    ANTENNADIFFAREA 0.897600 ;
    PORT
      LAYER Metal3 ;
        RECT 0.000 449.120 0.560 449.680 ;
    END
  END tl_h_d_o[65]
  PIN tl_h_d_o[6]
    DIRECTION OUTPUT ;
    USE SIGNAL ;
    ANTENNADIFFAREA 0.897600 ;
    PORT
      LAYER Metal3 ;
        RECT 0.000 383.040 0.560 383.600 ;
    END
  END tl_h_d_o[6]
  PIN tl_h_d_o[7]
    DIRECTION OUTPUT ;
    USE SIGNAL ;
    ANTENNADIFFAREA 0.897600 ;
    PORT
      LAYER Metal3 ;
        RECT 0.000 384.160 0.560 384.720 ;
    END
  END tl_h_d_o[7]
  PIN tl_h_d_o[8]
    DIRECTION OUTPUT ;
    USE SIGNAL ;
    ANTENNADIFFAREA 0.897600 ;
    PORT
      LAYER Metal3 ;
        RECT 0.000 385.280 0.560 385.840 ;
    END
  END tl_h_d_o[8]
  PIN tl_h_d_o[9]
    DIRECTION OUTPUT ;
    USE SIGNAL ;
    ANTENNADIFFAREA 0.897600 ;
    PORT
      LAYER Metal3 ;
        RECT 0.000 386.400 0.560 386.960 ;
    END
  END tl_h_d_o[9]
  PIN tl_h_i_i[0]
    DIRECTION INPUT ;
    USE SIGNAL ;
    ANTENNAGATEAREA 0.396000 ;
    PORT
      LAYER Metal3 ;
        RECT 0.000 47.040 0.560 47.600 ;
    END
  END tl_h_i_i[0]
  PIN tl_h_i_i[100]
    DIRECTION INPUT ;
    USE SIGNAL ;
    ANTENNAGATEAREA 0.396000 ;
    PORT
      LAYER Metal3 ;
        RECT 0.000 159.040 0.560 159.600 ;
    END
  END tl_h_i_i[100]
  PIN tl_h_i_i[101]
    DIRECTION INPUT ;
    USE SIGNAL ;
    ANTENNAGATEAREA 0.396000 ;
    PORT
      LAYER Metal3 ;
        RECT 0.000 160.160 0.560 160.720 ;
    END
  END tl_h_i_i[101]
  PIN tl_h_i_i[102]
    DIRECTION INPUT ;
    USE SIGNAL ;
    ANTENNAGATEAREA 0.396000 ;
    PORT
      LAYER Metal3 ;
        RECT 0.000 161.280 0.560 161.840 ;
    END
  END tl_h_i_i[102]
  PIN tl_h_i_i[103]
    DIRECTION INPUT ;
    USE SIGNAL ;
    ANTENNAGATEAREA 0.396000 ;
    PORT
      LAYER Metal3 ;
        RECT 0.000 162.400 0.560 162.960 ;
    END
  END tl_h_i_i[103]
  PIN tl_h_i_i[104]
    DIRECTION INPUT ;
    USE SIGNAL ;
    ANTENNAGATEAREA 0.396000 ;
    PORT
      LAYER Metal3 ;
        RECT 0.000 163.520 0.560 164.080 ;
    END
  END tl_h_i_i[104]
  PIN tl_h_i_i[105]
    DIRECTION INPUT ;
    USE SIGNAL ;
    ANTENNAGATEAREA 0.396000 ;
    PORT
      LAYER Metal3 ;
        RECT 0.000 164.640 0.560 165.200 ;
    END
  END tl_h_i_i[105]
  PIN tl_h_i_i[106]
    DIRECTION INPUT ;
    USE SIGNAL ;
    ANTENNAGATEAREA 0.396000 ;
    PORT
      LAYER Metal3 ;
        RECT 0.000 165.760 0.560 166.320 ;
    END
  END tl_h_i_i[106]
  PIN tl_h_i_i[107]
    DIRECTION INPUT ;
    USE SIGNAL ;
    ANTENNAGATEAREA 0.396000 ;
    PORT
      LAYER Metal3 ;
        RECT 0.000 166.880 0.560 167.440 ;
    END
  END tl_h_i_i[107]
  PIN tl_h_i_i[108]
    DIRECTION INPUT ;
    USE SIGNAL ;
    ANTENNAGATEAREA 0.396000 ;
    PORT
      LAYER Metal3 ;
        RECT 0.000 168.000 0.560 168.560 ;
    END
  END tl_h_i_i[108]
  PIN tl_h_i_i[109]
    DIRECTION INPUT ;
    USE SIGNAL ;
    ANTENNAGATEAREA 0.396000 ;
    PORT
      LAYER Metal3 ;
        RECT 0.000 169.120 0.560 169.680 ;
    END
  END tl_h_i_i[109]
  PIN tl_h_i_i[10]
    DIRECTION INPUT ;
    USE SIGNAL ;
    ANTENNAGATEAREA 0.396000 ;
    PORT
      LAYER Metal3 ;
        RECT 0.000 58.240 0.560 58.800 ;
    END
  END tl_h_i_i[10]
  PIN tl_h_i_i[110]
    DIRECTION INPUT ;
    USE SIGNAL ;
    ANTENNAGATEAREA 0.396000 ;
    PORT
      LAYER Metal3 ;
        RECT 0.000 170.240 0.560 170.800 ;
    END
  END tl_h_i_i[110]
  PIN tl_h_i_i[111]
    DIRECTION INPUT ;
    USE SIGNAL ;
    ANTENNAGATEAREA 0.396000 ;
    PORT
      LAYER Metal3 ;
        RECT 0.000 171.360 0.560 171.920 ;
    END
  END tl_h_i_i[111]
  PIN tl_h_i_i[112]
    DIRECTION INPUT ;
    USE SIGNAL ;
    ANTENNAGATEAREA 0.396000 ;
    PORT
      LAYER Metal3 ;
        RECT 0.000 172.480 0.560 173.040 ;
    END
  END tl_h_i_i[112]
  PIN tl_h_i_i[113]
    DIRECTION INPUT ;
    USE SIGNAL ;
    ANTENNAGATEAREA 0.396000 ;
    PORT
      LAYER Metal3 ;
        RECT 0.000 173.600 0.560 174.160 ;
    END
  END tl_h_i_i[113]
  PIN tl_h_i_i[11]
    DIRECTION INPUT ;
    USE SIGNAL ;
    ANTENNAGATEAREA 0.396000 ;
    PORT
      LAYER Metal3 ;
        RECT 0.000 59.360 0.560 59.920 ;
    END
  END tl_h_i_i[11]
  PIN tl_h_i_i[12]
    DIRECTION INPUT ;
    USE SIGNAL ;
    ANTENNAGATEAREA 0.396000 ;
    ANTENNADIFFAREA 0.410400 ;
    PORT
      LAYER Metal3 ;
        RECT 0.000 60.480 0.560 61.040 ;
    END
  END tl_h_i_i[12]
  PIN tl_h_i_i[13]
    DIRECTION INPUT ;
    USE SIGNAL ;
    ANTENNAGATEAREA 0.396000 ;
    PORT
      LAYER Metal3 ;
        RECT 0.000 61.600 0.560 62.160 ;
    END
  END tl_h_i_i[13]
  PIN tl_h_i_i[14]
    DIRECTION INPUT ;
    USE SIGNAL ;
    ANTENNAGATEAREA 0.396000 ;
    PORT
      LAYER Metal3 ;
        RECT 0.000 62.720 0.560 63.280 ;
    END
  END tl_h_i_i[14]
  PIN tl_h_i_i[15]
    DIRECTION INPUT ;
    USE SIGNAL ;
    ANTENNAGATEAREA 0.396000 ;
    PORT
      LAYER Metal3 ;
        RECT 0.000 63.840 0.560 64.400 ;
    END
  END tl_h_i_i[15]
  PIN tl_h_i_i[16]
    DIRECTION INPUT ;
    USE SIGNAL ;
    ANTENNAGATEAREA 0.396000 ;
    ANTENNADIFFAREA 0.410400 ;
    PORT
      LAYER Metal3 ;
        RECT 0.000 64.960 0.560 65.520 ;
    END
  END tl_h_i_i[16]
  PIN tl_h_i_i[17]
    DIRECTION INPUT ;
    USE SIGNAL ;
    ANTENNAGATEAREA 0.396000 ;
    PORT
      LAYER Metal3 ;
        RECT 0.000 66.080 0.560 66.640 ;
    END
  END tl_h_i_i[17]
  PIN tl_h_i_i[18]
    DIRECTION INPUT ;
    USE SIGNAL ;
    ANTENNAGATEAREA 0.396000 ;
    PORT
      LAYER Metal3 ;
        RECT 0.000 67.200 0.560 67.760 ;
    END
  END tl_h_i_i[18]
  PIN tl_h_i_i[19]
    DIRECTION INPUT ;
    USE SIGNAL ;
    ANTENNAGATEAREA 0.396000 ;
    PORT
      LAYER Metal3 ;
        RECT 0.000 68.320 0.560 68.880 ;
    END
  END tl_h_i_i[19]
  PIN tl_h_i_i[1]
    DIRECTION INPUT ;
    USE SIGNAL ;
    ANTENNAGATEAREA 0.396000 ;
    PORT
      LAYER Metal3 ;
        RECT 0.000 48.160 0.560 48.720 ;
    END
  END tl_h_i_i[1]
  PIN tl_h_i_i[20]
    DIRECTION INPUT ;
    USE SIGNAL ;
    ANTENNAGATEAREA 0.396000 ;
    PORT
      LAYER Metal3 ;
        RECT 0.000 69.440 0.560 70.000 ;
    END
  END tl_h_i_i[20]
  PIN tl_h_i_i[21]
    DIRECTION INPUT ;
    USE SIGNAL ;
    ANTENNAGATEAREA 0.396000 ;
    PORT
      LAYER Metal3 ;
        RECT 0.000 70.560 0.560 71.120 ;
    END
  END tl_h_i_i[21]
  PIN tl_h_i_i[22]
    DIRECTION INPUT ;
    USE SIGNAL ;
    ANTENNAGATEAREA 0.396000 ;
    PORT
      LAYER Metal3 ;
        RECT 0.000 71.680 0.560 72.240 ;
    END
  END tl_h_i_i[22]
  PIN tl_h_i_i[23]
    DIRECTION INPUT ;
    USE SIGNAL ;
    ANTENNAGATEAREA 0.396000 ;
    ANTENNADIFFAREA 0.410400 ;
    PORT
      LAYER Metal3 ;
        RECT 0.000 72.800 0.560 73.360 ;
    END
  END tl_h_i_i[23]
  PIN tl_h_i_i[24]
    DIRECTION INPUT ;
    USE SIGNAL ;
    ANTENNAGATEAREA 0.396000 ;
    PORT
      LAYER Metal3 ;
        RECT 0.000 73.920 0.560 74.480 ;
    END
  END tl_h_i_i[24]
  PIN tl_h_i_i[25]
    DIRECTION INPUT ;
    USE SIGNAL ;
    ANTENNAGATEAREA 0.396000 ;
    PORT
      LAYER Metal3 ;
        RECT 0.000 75.040 0.560 75.600 ;
    END
  END tl_h_i_i[25]
  PIN tl_h_i_i[26]
    DIRECTION INPUT ;
    USE SIGNAL ;
    ANTENNAGATEAREA 0.396000 ;
    PORT
      LAYER Metal3 ;
        RECT 0.000 76.160 0.560 76.720 ;
    END
  END tl_h_i_i[26]
  PIN tl_h_i_i[27]
    DIRECTION INPUT ;
    USE SIGNAL ;
    ANTENNAGATEAREA 0.396000 ;
    PORT
      LAYER Metal3 ;
        RECT 0.000 77.280 0.560 77.840 ;
    END
  END tl_h_i_i[27]
  PIN tl_h_i_i[28]
    DIRECTION INPUT ;
    USE SIGNAL ;
    ANTENNAGATEAREA 0.396000 ;
    PORT
      LAYER Metal3 ;
        RECT 0.000 78.400 0.560 78.960 ;
    END
  END tl_h_i_i[28]
  PIN tl_h_i_i[29]
    DIRECTION INPUT ;
    USE SIGNAL ;
    ANTENNAGATEAREA 0.396000 ;
    PORT
      LAYER Metal3 ;
        RECT 0.000 79.520 0.560 80.080 ;
    END
  END tl_h_i_i[29]
  PIN tl_h_i_i[2]
    DIRECTION INPUT ;
    USE SIGNAL ;
    ANTENNAGATEAREA 0.396000 ;
    PORT
      LAYER Metal3 ;
        RECT 0.000 49.280 0.560 49.840 ;
    END
  END tl_h_i_i[2]
  PIN tl_h_i_i[30]
    DIRECTION INPUT ;
    USE SIGNAL ;
    ANTENNAGATEAREA 0.396000 ;
    PORT
      LAYER Metal3 ;
        RECT 0.000 80.640 0.560 81.200 ;
    END
  END tl_h_i_i[30]
  PIN tl_h_i_i[31]
    DIRECTION INPUT ;
    USE SIGNAL ;
    ANTENNAGATEAREA 0.396000 ;
    PORT
      LAYER Metal3 ;
        RECT 0.000 81.760 0.560 82.320 ;
    END
  END tl_h_i_i[31]
  PIN tl_h_i_i[32]
    DIRECTION INPUT ;
    USE SIGNAL ;
    ANTENNAGATEAREA 0.396000 ;
    PORT
      LAYER Metal3 ;
        RECT 0.000 82.880 0.560 83.440 ;
    END
  END tl_h_i_i[32]
  PIN tl_h_i_i[33]
    DIRECTION INPUT ;
    USE SIGNAL ;
    ANTENNAGATEAREA 0.396000 ;
    PORT
      LAYER Metal3 ;
        RECT 0.000 84.000 0.560 84.560 ;
    END
  END tl_h_i_i[33]
  PIN tl_h_i_i[34]
    DIRECTION INPUT ;
    USE SIGNAL ;
    ANTENNAGATEAREA 0.396000 ;
    PORT
      LAYER Metal3 ;
        RECT 0.000 85.120 0.560 85.680 ;
    END
  END tl_h_i_i[34]
  PIN tl_h_i_i[35]
    DIRECTION INPUT ;
    USE SIGNAL ;
    ANTENNAGATEAREA 0.396000 ;
    PORT
      LAYER Metal3 ;
        RECT 0.000 86.240 0.560 86.800 ;
    END
  END tl_h_i_i[35]
  PIN tl_h_i_i[36]
    DIRECTION INPUT ;
    USE SIGNAL ;
    ANTENNAGATEAREA 0.396000 ;
    PORT
      LAYER Metal3 ;
        RECT 0.000 87.360 0.560 87.920 ;
    END
  END tl_h_i_i[36]
  PIN tl_h_i_i[37]
    DIRECTION INPUT ;
    USE SIGNAL ;
    ANTENNAGATEAREA 0.396000 ;
    PORT
      LAYER Metal3 ;
        RECT 0.000 88.480 0.560 89.040 ;
    END
  END tl_h_i_i[37]
  PIN tl_h_i_i[38]
    DIRECTION INPUT ;
    USE SIGNAL ;
    ANTENNAGATEAREA 0.396000 ;
    PORT
      LAYER Metal3 ;
        RECT 0.000 89.600 0.560 90.160 ;
    END
  END tl_h_i_i[38]
  PIN tl_h_i_i[39]
    DIRECTION INPUT ;
    USE SIGNAL ;
    ANTENNAGATEAREA 0.396000 ;
    PORT
      LAYER Metal3 ;
        RECT 0.000 90.720 0.560 91.280 ;
    END
  END tl_h_i_i[39]
  PIN tl_h_i_i[3]
    DIRECTION INPUT ;
    USE SIGNAL ;
    ANTENNAGATEAREA 0.396000 ;
    PORT
      LAYER Metal3 ;
        RECT 0.000 50.400 0.560 50.960 ;
    END
  END tl_h_i_i[3]
  PIN tl_h_i_i[40]
    DIRECTION INPUT ;
    USE SIGNAL ;
    ANTENNAGATEAREA 0.396000 ;
    PORT
      LAYER Metal3 ;
        RECT 0.000 91.840 0.560 92.400 ;
    END
  END tl_h_i_i[40]
  PIN tl_h_i_i[41]
    DIRECTION INPUT ;
    USE SIGNAL ;
    ANTENNAGATEAREA 0.396000 ;
    PORT
      LAYER Metal3 ;
        RECT 0.000 92.960 0.560 93.520 ;
    END
  END tl_h_i_i[41]
  PIN tl_h_i_i[42]
    DIRECTION INPUT ;
    USE SIGNAL ;
    ANTENNAGATEAREA 0.396000 ;
    PORT
      LAYER Metal3 ;
        RECT 0.000 94.080 0.560 94.640 ;
    END
  END tl_h_i_i[42]
  PIN tl_h_i_i[43]
    DIRECTION INPUT ;
    USE SIGNAL ;
    ANTENNAGATEAREA 0.396000 ;
    PORT
      LAYER Metal3 ;
        RECT 0.000 95.200 0.560 95.760 ;
    END
  END tl_h_i_i[43]
  PIN tl_h_i_i[44]
    DIRECTION INPUT ;
    USE SIGNAL ;
    ANTENNAGATEAREA 0.396000 ;
    PORT
      LAYER Metal3 ;
        RECT 0.000 96.320 0.560 96.880 ;
    END
  END tl_h_i_i[44]
  PIN tl_h_i_i[45]
    DIRECTION INPUT ;
    USE SIGNAL ;
    ANTENNAGATEAREA 0.396000 ;
    PORT
      LAYER Metal3 ;
        RECT 0.000 97.440 0.560 98.000 ;
    END
  END tl_h_i_i[45]
  PIN tl_h_i_i[46]
    DIRECTION INPUT ;
    USE SIGNAL ;
    ANTENNAGATEAREA 0.396000 ;
    PORT
      LAYER Metal3 ;
        RECT 0.000 98.560 0.560 99.120 ;
    END
  END tl_h_i_i[46]
  PIN tl_h_i_i[47]
    DIRECTION INPUT ;
    USE SIGNAL ;
    ANTENNAGATEAREA 0.396000 ;
    PORT
      LAYER Metal3 ;
        RECT 0.000 99.680 0.560 100.240 ;
    END
  END tl_h_i_i[47]
  PIN tl_h_i_i[48]
    DIRECTION INPUT ;
    USE SIGNAL ;
    ANTENNAGATEAREA 0.396000 ;
    PORT
      LAYER Metal3 ;
        RECT 0.000 100.800 0.560 101.360 ;
    END
  END tl_h_i_i[48]
  PIN tl_h_i_i[49]
    DIRECTION INPUT ;
    USE SIGNAL ;
    ANTENNAGATEAREA 0.396000 ;
    PORT
      LAYER Metal3 ;
        RECT 0.000 101.920 0.560 102.480 ;
    END
  END tl_h_i_i[49]
  PIN tl_h_i_i[4]
    DIRECTION INPUT ;
    USE SIGNAL ;
    ANTENNAGATEAREA 0.396000 ;
    ANTENNADIFFAREA 0.410400 ;
    PORT
      LAYER Metal3 ;
        RECT 0.000 51.520 0.560 52.080 ;
    END
  END tl_h_i_i[4]
  PIN tl_h_i_i[50]
    DIRECTION INPUT ;
    USE SIGNAL ;
    ANTENNAGATEAREA 0.396000 ;
    PORT
      LAYER Metal3 ;
        RECT 0.000 103.040 0.560 103.600 ;
    END
  END tl_h_i_i[50]
  PIN tl_h_i_i[51]
    DIRECTION INPUT ;
    USE SIGNAL ;
    ANTENNAGATEAREA 0.396000 ;
    PORT
      LAYER Metal3 ;
        RECT 0.000 104.160 0.560 104.720 ;
    END
  END tl_h_i_i[51]
  PIN tl_h_i_i[52]
    DIRECTION INPUT ;
    USE SIGNAL ;
    ANTENNAGATEAREA 0.396000 ;
    PORT
      LAYER Metal3 ;
        RECT 0.000 105.280 0.560 105.840 ;
    END
  END tl_h_i_i[52]
  PIN tl_h_i_i[53]
    DIRECTION INPUT ;
    USE SIGNAL ;
    ANTENNAGATEAREA 0.396000 ;
    PORT
      LAYER Metal3 ;
        RECT 0.000 106.400 0.560 106.960 ;
    END
  END tl_h_i_i[53]
  PIN tl_h_i_i[54]
    DIRECTION INPUT ;
    USE SIGNAL ;
    ANTENNAGATEAREA 0.396000 ;
    PORT
      LAYER Metal3 ;
        RECT 0.000 107.520 0.560 108.080 ;
    END
  END tl_h_i_i[54]
  PIN tl_h_i_i[55]
    DIRECTION INPUT ;
    USE SIGNAL ;
    ANTENNAGATEAREA 0.396000 ;
    PORT
      LAYER Metal3 ;
        RECT 0.000 108.640 0.560 109.200 ;
    END
  END tl_h_i_i[55]
  PIN tl_h_i_i[56]
    DIRECTION INPUT ;
    USE SIGNAL ;
    ANTENNAGATEAREA 0.396000 ;
    PORT
      LAYER Metal3 ;
        RECT 0.000 109.760 0.560 110.320 ;
    END
  END tl_h_i_i[56]
  PIN tl_h_i_i[57]
    DIRECTION INPUT ;
    USE SIGNAL ;
    ANTENNAGATEAREA 0.396000 ;
    PORT
      LAYER Metal3 ;
        RECT 0.000 110.880 0.560 111.440 ;
    END
  END tl_h_i_i[57]
  PIN tl_h_i_i[58]
    DIRECTION INPUT ;
    USE SIGNAL ;
    ANTENNAGATEAREA 0.396000 ;
    PORT
      LAYER Metal3 ;
        RECT 0.000 112.000 0.560 112.560 ;
    END
  END tl_h_i_i[58]
  PIN tl_h_i_i[59]
    DIRECTION INPUT ;
    USE SIGNAL ;
    ANTENNAGATEAREA 0.396000 ;
    PORT
      LAYER Metal3 ;
        RECT 0.000 113.120 0.560 113.680 ;
    END
  END tl_h_i_i[59]
  PIN tl_h_i_i[5]
    DIRECTION INPUT ;
    USE SIGNAL ;
    ANTENNAGATEAREA 0.396000 ;
    PORT
      LAYER Metal3 ;
        RECT 0.000 52.640 0.560 53.200 ;
    END
  END tl_h_i_i[5]
  PIN tl_h_i_i[60]
    DIRECTION INPUT ;
    USE SIGNAL ;
    ANTENNAGATEAREA 0.396000 ;
    PORT
      LAYER Metal3 ;
        RECT 0.000 114.240 0.560 114.800 ;
    END
  END tl_h_i_i[60]
  PIN tl_h_i_i[61]
    DIRECTION INPUT ;
    USE SIGNAL ;
    ANTENNAGATEAREA 0.396000 ;
    PORT
      LAYER Metal3 ;
        RECT 0.000 115.360 0.560 115.920 ;
    END
  END tl_h_i_i[61]
  PIN tl_h_i_i[62]
    DIRECTION INPUT ;
    USE SIGNAL ;
    ANTENNAGATEAREA 0.396000 ;
    PORT
      LAYER Metal3 ;
        RECT 0.000 116.480 0.560 117.040 ;
    END
  END tl_h_i_i[62]
  PIN tl_h_i_i[63]
    DIRECTION INPUT ;
    USE SIGNAL ;
    ANTENNAGATEAREA 0.396000 ;
    PORT
      LAYER Metal3 ;
        RECT 0.000 117.600 0.560 118.160 ;
    END
  END tl_h_i_i[63]
  PIN tl_h_i_i[64]
    DIRECTION INPUT ;
    USE SIGNAL ;
    ANTENNAGATEAREA 0.396000 ;
    PORT
      LAYER Metal3 ;
        RECT 0.000 118.720 0.560 119.280 ;
    END
  END tl_h_i_i[64]
  PIN tl_h_i_i[65]
    DIRECTION INPUT ;
    USE SIGNAL ;
    ANTENNAGATEAREA 0.396000 ;
    PORT
      LAYER Metal3 ;
        RECT 0.000 119.840 0.560 120.400 ;
    END
  END tl_h_i_i[65]
  PIN tl_h_i_i[66]
    DIRECTION INPUT ;
    USE SIGNAL ;
    ANTENNAGATEAREA 0.396000 ;
    PORT
      LAYER Metal3 ;
        RECT 0.000 120.960 0.560 121.520 ;
    END
  END tl_h_i_i[66]
  PIN tl_h_i_i[67]
    DIRECTION INPUT ;
    USE SIGNAL ;
    ANTENNAGATEAREA 0.396000 ;
    PORT
      LAYER Metal3 ;
        RECT 0.000 122.080 0.560 122.640 ;
    END
  END tl_h_i_i[67]
  PIN tl_h_i_i[68]
    DIRECTION INPUT ;
    USE SIGNAL ;
    ANTENNAGATEAREA 0.396000 ;
    PORT
      LAYER Metal3 ;
        RECT 0.000 123.200 0.560 123.760 ;
    END
  END tl_h_i_i[68]
  PIN tl_h_i_i[69]
    DIRECTION INPUT ;
    USE SIGNAL ;
    ANTENNAGATEAREA 0.396000 ;
    PORT
      LAYER Metal3 ;
        RECT 0.000 124.320 0.560 124.880 ;
    END
  END tl_h_i_i[69]
  PIN tl_h_i_i[6]
    DIRECTION INPUT ;
    USE SIGNAL ;
    ANTENNAGATEAREA 0.396000 ;
    PORT
      LAYER Metal3 ;
        RECT 0.000 53.760 0.560 54.320 ;
    END
  END tl_h_i_i[6]
  PIN tl_h_i_i[70]
    DIRECTION INPUT ;
    USE SIGNAL ;
    ANTENNAGATEAREA 0.396000 ;
    PORT
      LAYER Metal3 ;
        RECT 0.000 125.440 0.560 126.000 ;
    END
  END tl_h_i_i[70]
  PIN tl_h_i_i[71]
    DIRECTION INPUT ;
    USE SIGNAL ;
    ANTENNAGATEAREA 0.396000 ;
    PORT
      LAYER Metal3 ;
        RECT 0.000 126.560 0.560 127.120 ;
    END
  END tl_h_i_i[71]
  PIN tl_h_i_i[72]
    DIRECTION INPUT ;
    USE SIGNAL ;
    ANTENNAGATEAREA 0.396000 ;
    PORT
      LAYER Metal3 ;
        RECT 0.000 127.680 0.560 128.240 ;
    END
  END tl_h_i_i[72]
  PIN tl_h_i_i[73]
    DIRECTION INPUT ;
    USE SIGNAL ;
    ANTENNAGATEAREA 0.396000 ;
    PORT
      LAYER Metal3 ;
        RECT 0.000 128.800 0.560 129.360 ;
    END
  END tl_h_i_i[73]
  PIN tl_h_i_i[74]
    DIRECTION INPUT ;
    USE SIGNAL ;
    ANTENNAGATEAREA 0.396000 ;
    PORT
      LAYER Metal3 ;
        RECT 0.000 129.920 0.560 130.480 ;
    END
  END tl_h_i_i[74]
  PIN tl_h_i_i[75]
    DIRECTION INPUT ;
    USE SIGNAL ;
    ANTENNAGATEAREA 0.396000 ;
    PORT
      LAYER Metal3 ;
        RECT 0.000 131.040 0.560 131.600 ;
    END
  END tl_h_i_i[75]
  PIN tl_h_i_i[76]
    DIRECTION INPUT ;
    USE SIGNAL ;
    ANTENNAGATEAREA 0.396000 ;
    PORT
      LAYER Metal3 ;
        RECT 0.000 132.160 0.560 132.720 ;
    END
  END tl_h_i_i[76]
  PIN tl_h_i_i[77]
    DIRECTION INPUT ;
    USE SIGNAL ;
    ANTENNAGATEAREA 0.396000 ;
    PORT
      LAYER Metal3 ;
        RECT 0.000 133.280 0.560 133.840 ;
    END
  END tl_h_i_i[77]
  PIN tl_h_i_i[78]
    DIRECTION INPUT ;
    USE SIGNAL ;
    ANTENNAGATEAREA 0.396000 ;
    PORT
      LAYER Metal3 ;
        RECT 0.000 134.400 0.560 134.960 ;
    END
  END tl_h_i_i[78]
  PIN tl_h_i_i[79]
    DIRECTION INPUT ;
    USE SIGNAL ;
    ANTENNAGATEAREA 0.396000 ;
    PORT
      LAYER Metal3 ;
        RECT 0.000 135.520 0.560 136.080 ;
    END
  END tl_h_i_i[79]
  PIN tl_h_i_i[7]
    DIRECTION INPUT ;
    USE SIGNAL ;
    ANTENNAGATEAREA 0.396000 ;
    ANTENNADIFFAREA 0.410400 ;
    PORT
      LAYER Metal3 ;
        RECT 0.000 54.880 0.560 55.440 ;
    END
  END tl_h_i_i[7]
  PIN tl_h_i_i[80]
    DIRECTION INPUT ;
    USE SIGNAL ;
    ANTENNAGATEAREA 0.396000 ;
    PORT
      LAYER Metal3 ;
        RECT 0.000 136.640 0.560 137.200 ;
    END
  END tl_h_i_i[80]
  PIN tl_h_i_i[81]
    DIRECTION INPUT ;
    USE SIGNAL ;
    ANTENNAGATEAREA 0.396000 ;
    PORT
      LAYER Metal3 ;
        RECT 0.000 137.760 0.560 138.320 ;
    END
  END tl_h_i_i[81]
  PIN tl_h_i_i[82]
    DIRECTION INPUT ;
    USE SIGNAL ;
    ANTENNAGATEAREA 0.396000 ;
    PORT
      LAYER Metal3 ;
        RECT 0.000 138.880 0.560 139.440 ;
    END
  END tl_h_i_i[82]
  PIN tl_h_i_i[83]
    DIRECTION INPUT ;
    USE SIGNAL ;
    ANTENNAGATEAREA 0.396000 ;
    PORT
      LAYER Metal3 ;
        RECT 0.000 140.000 0.560 140.560 ;
    END
  END tl_h_i_i[83]
  PIN tl_h_i_i[84]
    DIRECTION INPUT ;
    USE SIGNAL ;
    ANTENNAGATEAREA 0.396000 ;
    PORT
      LAYER Metal3 ;
        RECT 0.000 141.120 0.560 141.680 ;
    END
  END tl_h_i_i[84]
  PIN tl_h_i_i[85]
    DIRECTION INPUT ;
    USE SIGNAL ;
    ANTENNAGATEAREA 0.396000 ;
    PORT
      LAYER Metal3 ;
        RECT 0.000 142.240 0.560 142.800 ;
    END
  END tl_h_i_i[85]
  PIN tl_h_i_i[86]
    DIRECTION INPUT ;
    USE SIGNAL ;
    ANTENNAGATEAREA 0.396000 ;
    ANTENNADIFFAREA 0.410400 ;
    PORT
      LAYER Metal3 ;
        RECT 0.000 143.360 0.560 143.920 ;
    END
  END tl_h_i_i[86]
  PIN tl_h_i_i[87]
    DIRECTION INPUT ;
    USE SIGNAL ;
    ANTENNAGATEAREA 0.396000 ;
    PORT
      LAYER Metal3 ;
        RECT 0.000 144.480 0.560 145.040 ;
    END
  END tl_h_i_i[87]
  PIN tl_h_i_i[88]
    DIRECTION INPUT ;
    USE SIGNAL ;
    ANTENNAGATEAREA 0.396000 ;
    PORT
      LAYER Metal3 ;
        RECT 0.000 145.600 0.560 146.160 ;
    END
  END tl_h_i_i[88]
  PIN tl_h_i_i[89]
    DIRECTION INPUT ;
    USE SIGNAL ;
    ANTENNAGATEAREA 0.396000 ;
    PORT
      LAYER Metal3 ;
        RECT 0.000 146.720 0.560 147.280 ;
    END
  END tl_h_i_i[89]
  PIN tl_h_i_i[8]
    DIRECTION INPUT ;
    USE SIGNAL ;
    ANTENNAGATEAREA 0.396000 ;
    PORT
      LAYER Metal3 ;
        RECT 0.000 56.000 0.560 56.560 ;
    END
  END tl_h_i_i[8]
  PIN tl_h_i_i[90]
    DIRECTION INPUT ;
    USE SIGNAL ;
    ANTENNAGATEAREA 0.396000 ;
    ANTENNADIFFAREA 0.410400 ;
    PORT
      LAYER Metal3 ;
        RECT 0.000 147.840 0.560 148.400 ;
    END
  END tl_h_i_i[90]
  PIN tl_h_i_i[91]
    DIRECTION INPUT ;
    USE SIGNAL ;
    ANTENNAGATEAREA 0.396000 ;
    PORT
      LAYER Metal3 ;
        RECT 0.000 148.960 0.560 149.520 ;
    END
  END tl_h_i_i[91]
  PIN tl_h_i_i[92]
    DIRECTION INPUT ;
    USE SIGNAL ;
    ANTENNAGATEAREA 0.396000 ;
    PORT
      LAYER Metal3 ;
        RECT 0.000 150.080 0.560 150.640 ;
    END
  END tl_h_i_i[92]
  PIN tl_h_i_i[93]
    DIRECTION INPUT ;
    USE SIGNAL ;
    ANTENNAGATEAREA 0.396000 ;
    ANTENNADIFFAREA 0.410400 ;
    PORT
      LAYER Metal3 ;
        RECT 0.000 151.200 0.560 151.760 ;
    END
  END tl_h_i_i[93]
  PIN tl_h_i_i[94]
    DIRECTION INPUT ;
    USE SIGNAL ;
    ANTENNAGATEAREA 0.396000 ;
    PORT
      LAYER Metal3 ;
        RECT 0.000 152.320 0.560 152.880 ;
    END
  END tl_h_i_i[94]
  PIN tl_h_i_i[95]
    DIRECTION INPUT ;
    USE SIGNAL ;
    ANTENNAGATEAREA 0.396000 ;
    PORT
      LAYER Metal3 ;
        RECT 0.000 153.440 0.560 154.000 ;
    END
  END tl_h_i_i[95]
  PIN tl_h_i_i[96]
    DIRECTION INPUT ;
    USE SIGNAL ;
    ANTENNAGATEAREA 0.396000 ;
    PORT
      LAYER Metal3 ;
        RECT 0.000 154.560 0.560 155.120 ;
    END
  END tl_h_i_i[96]
  PIN tl_h_i_i[97]
    DIRECTION INPUT ;
    USE SIGNAL ;
    ANTENNAGATEAREA 0.396000 ;
    PORT
      LAYER Metal3 ;
        RECT 0.000 155.680 0.560 156.240 ;
    END
  END tl_h_i_i[97]
  PIN tl_h_i_i[98]
    DIRECTION INPUT ;
    USE SIGNAL ;
    ANTENNAGATEAREA 0.396000 ;
    PORT
      LAYER Metal3 ;
        RECT 0.000 156.800 0.560 157.360 ;
    END
  END tl_h_i_i[98]
  PIN tl_h_i_i[99]
    DIRECTION INPUT ;
    USE SIGNAL ;
    ANTENNAGATEAREA 0.396000 ;
    PORT
      LAYER Metal3 ;
        RECT 0.000 157.920 0.560 158.480 ;
    END
  END tl_h_i_i[99]
  PIN tl_h_i_i[9]
    DIRECTION INPUT ;
    USE SIGNAL ;
    ANTENNAGATEAREA 0.396000 ;
    PORT
      LAYER Metal3 ;
        RECT 0.000 57.120 0.560 57.680 ;
    END
  END tl_h_i_i[9]
  PIN tl_h_i_o[0]
    DIRECTION OUTPUT ;
    USE SIGNAL ;
    ANTENNADIFFAREA 0.897600 ;
    PORT
      LAYER Metal3 ;
        RECT 0.000 174.720 0.560 175.280 ;
    END
  END tl_h_i_o[0]
  PIN tl_h_i_o[10]
    DIRECTION OUTPUT ;
    USE SIGNAL ;
    ANTENNADIFFAREA 0.897600 ;
    PORT
      LAYER Metal3 ;
        RECT 0.000 185.920 0.560 186.480 ;
    END
  END tl_h_i_o[10]
  PIN tl_h_i_o[11]
    DIRECTION OUTPUT ;
    USE SIGNAL ;
    ANTENNADIFFAREA 0.897600 ;
    PORT
      LAYER Metal3 ;
        RECT 0.000 187.040 0.560 187.600 ;
    END
  END tl_h_i_o[11]
  PIN tl_h_i_o[12]
    DIRECTION OUTPUT ;
    USE SIGNAL ;
    ANTENNADIFFAREA 0.897600 ;
    PORT
      LAYER Metal3 ;
        RECT 0.000 188.160 0.560 188.720 ;
    END
  END tl_h_i_o[12]
  PIN tl_h_i_o[13]
    DIRECTION OUTPUT ;
    USE SIGNAL ;
    ANTENNADIFFAREA 0.897600 ;
    PORT
      LAYER Metal3 ;
        RECT 0.000 189.280 0.560 189.840 ;
    END
  END tl_h_i_o[13]
  PIN tl_h_i_o[14]
    DIRECTION OUTPUT ;
    USE SIGNAL ;
    ANTENNADIFFAREA 0.897600 ;
    PORT
      LAYER Metal3 ;
        RECT 0.000 190.400 0.560 190.960 ;
    END
  END tl_h_i_o[14]
  PIN tl_h_i_o[15]
    DIRECTION OUTPUT ;
    USE SIGNAL ;
    ANTENNADIFFAREA 0.897600 ;
    PORT
      LAYER Metal3 ;
        RECT 0.000 191.520 0.560 192.080 ;
    END
  END tl_h_i_o[15]
  PIN tl_h_i_o[16]
    DIRECTION OUTPUT ;
    USE SIGNAL ;
    ANTENNADIFFAREA 0.897600 ;
    PORT
      LAYER Metal3 ;
        RECT 0.000 192.640 0.560 193.200 ;
    END
  END tl_h_i_o[16]
  PIN tl_h_i_o[17]
    DIRECTION OUTPUT ;
    USE SIGNAL ;
    ANTENNADIFFAREA 0.897600 ;
    PORT
      LAYER Metal3 ;
        RECT 0.000 193.760 0.560 194.320 ;
    END
  END tl_h_i_o[17]
  PIN tl_h_i_o[18]
    DIRECTION OUTPUT ;
    USE SIGNAL ;
    ANTENNADIFFAREA 0.897600 ;
    PORT
      LAYER Metal3 ;
        RECT 0.000 194.880 0.560 195.440 ;
    END
  END tl_h_i_o[18]
  PIN tl_h_i_o[19]
    DIRECTION OUTPUT ;
    USE SIGNAL ;
    ANTENNADIFFAREA 0.897600 ;
    PORT
      LAYER Metal3 ;
        RECT 0.000 196.000 0.560 196.560 ;
    END
  END tl_h_i_o[19]
  PIN tl_h_i_o[1]
    DIRECTION OUTPUT ;
    USE SIGNAL ;
    ANTENNADIFFAREA 0.897600 ;
    PORT
      LAYER Metal3 ;
        RECT 0.000 175.840 0.560 176.400 ;
    END
  END tl_h_i_o[1]
  PIN tl_h_i_o[20]
    DIRECTION OUTPUT ;
    USE SIGNAL ;
    ANTENNADIFFAREA 0.897600 ;
    PORT
      LAYER Metal3 ;
        RECT 0.000 197.120 0.560 197.680 ;
    END
  END tl_h_i_o[20]
  PIN tl_h_i_o[21]
    DIRECTION OUTPUT ;
    USE SIGNAL ;
    ANTENNADIFFAREA 0.897600 ;
    PORT
      LAYER Metal3 ;
        RECT 0.000 198.240 0.560 198.800 ;
    END
  END tl_h_i_o[21]
  PIN tl_h_i_o[22]
    DIRECTION OUTPUT ;
    USE SIGNAL ;
    ANTENNADIFFAREA 0.897600 ;
    PORT
      LAYER Metal3 ;
        RECT 0.000 199.360 0.560 199.920 ;
    END
  END tl_h_i_o[22]
  PIN tl_h_i_o[23]
    DIRECTION OUTPUT ;
    USE SIGNAL ;
    ANTENNADIFFAREA 0.897600 ;
    PORT
      LAYER Metal3 ;
        RECT 0.000 200.480 0.560 201.040 ;
    END
  END tl_h_i_o[23]
  PIN tl_h_i_o[24]
    DIRECTION OUTPUT ;
    USE SIGNAL ;
    ANTENNADIFFAREA 0.897600 ;
    PORT
      LAYER Metal3 ;
        RECT 0.000 201.600 0.560 202.160 ;
    END
  END tl_h_i_o[24]
  PIN tl_h_i_o[25]
    DIRECTION OUTPUT ;
    USE SIGNAL ;
    ANTENNADIFFAREA 0.897600 ;
    PORT
      LAYER Metal3 ;
        RECT 0.000 202.720 0.560 203.280 ;
    END
  END tl_h_i_o[25]
  PIN tl_h_i_o[26]
    DIRECTION OUTPUT ;
    USE SIGNAL ;
    ANTENNADIFFAREA 0.897600 ;
    PORT
      LAYER Metal3 ;
        RECT 0.000 203.840 0.560 204.400 ;
    END
  END tl_h_i_o[26]
  PIN tl_h_i_o[27]
    DIRECTION OUTPUT ;
    USE SIGNAL ;
    ANTENNADIFFAREA 0.897600 ;
    PORT
      LAYER Metal3 ;
        RECT 0.000 204.960 0.560 205.520 ;
    END
  END tl_h_i_o[27]
  PIN tl_h_i_o[28]
    DIRECTION OUTPUT ;
    USE SIGNAL ;
    ANTENNADIFFAREA 0.897600 ;
    PORT
      LAYER Metal3 ;
        RECT 0.000 206.080 0.560 206.640 ;
    END
  END tl_h_i_o[28]
  PIN tl_h_i_o[29]
    DIRECTION OUTPUT ;
    USE SIGNAL ;
    ANTENNADIFFAREA 0.897600 ;
    PORT
      LAYER Metal3 ;
        RECT 0.000 207.200 0.560 207.760 ;
    END
  END tl_h_i_o[29]
  PIN tl_h_i_o[2]
    DIRECTION OUTPUT ;
    USE SIGNAL ;
    ANTENNADIFFAREA 0.897600 ;
    PORT
      LAYER Metal3 ;
        RECT 0.000 176.960 0.560 177.520 ;
    END
  END tl_h_i_o[2]
  PIN tl_h_i_o[30]
    DIRECTION OUTPUT ;
    USE SIGNAL ;
    ANTENNADIFFAREA 0.897600 ;
    PORT
      LAYER Metal3 ;
        RECT 0.000 208.320 0.560 208.880 ;
    END
  END tl_h_i_o[30]
  PIN tl_h_i_o[31]
    DIRECTION OUTPUT ;
    USE SIGNAL ;
    ANTENNADIFFAREA 0.897600 ;
    PORT
      LAYER Metal3 ;
        RECT 0.000 209.440 0.560 210.000 ;
    END
  END tl_h_i_o[31]
  PIN tl_h_i_o[32]
    DIRECTION OUTPUT ;
    USE SIGNAL ;
    ANTENNADIFFAREA 0.897600 ;
    PORT
      LAYER Metal3 ;
        RECT 0.000 210.560 0.560 211.120 ;
    END
  END tl_h_i_o[32]
  PIN tl_h_i_o[33]
    DIRECTION OUTPUT ;
    USE SIGNAL ;
    ANTENNADIFFAREA 0.897600 ;
    PORT
      LAYER Metal3 ;
        RECT 0.000 211.680 0.560 212.240 ;
    END
  END tl_h_i_o[33]
  PIN tl_h_i_o[34]
    DIRECTION OUTPUT ;
    USE SIGNAL ;
    ANTENNADIFFAREA 0.897600 ;
    PORT
      LAYER Metal3 ;
        RECT 0.000 212.800 0.560 213.360 ;
    END
  END tl_h_i_o[34]
  PIN tl_h_i_o[35]
    DIRECTION OUTPUT ;
    USE SIGNAL ;
    ANTENNADIFFAREA 0.897600 ;
    PORT
      LAYER Metal3 ;
        RECT 0.000 213.920 0.560 214.480 ;
    END
  END tl_h_i_o[35]
  PIN tl_h_i_o[36]
    DIRECTION OUTPUT ;
    USE SIGNAL ;
    ANTENNADIFFAREA 0.897600 ;
    PORT
      LAYER Metal3 ;
        RECT 0.000 215.040 0.560 215.600 ;
    END
  END tl_h_i_o[36]
  PIN tl_h_i_o[37]
    DIRECTION OUTPUT ;
    USE SIGNAL ;
    ANTENNADIFFAREA 0.897600 ;
    PORT
      LAYER Metal3 ;
        RECT 0.000 216.160 0.560 216.720 ;
    END
  END tl_h_i_o[37]
  PIN tl_h_i_o[38]
    DIRECTION OUTPUT ;
    USE SIGNAL ;
    ANTENNADIFFAREA 0.897600 ;
    PORT
      LAYER Metal3 ;
        RECT 0.000 217.280 0.560 217.840 ;
    END
  END tl_h_i_o[38]
  PIN tl_h_i_o[39]
    DIRECTION OUTPUT ;
    USE SIGNAL ;
    ANTENNADIFFAREA 0.897600 ;
    PORT
      LAYER Metal3 ;
        RECT 0.000 218.400 0.560 218.960 ;
    END
  END tl_h_i_o[39]
  PIN tl_h_i_o[3]
    DIRECTION OUTPUT ;
    USE SIGNAL ;
    ANTENNADIFFAREA 0.897600 ;
    PORT
      LAYER Metal3 ;
        RECT 0.000 178.080 0.560 178.640 ;
    END
  END tl_h_i_o[3]
  PIN tl_h_i_o[40]
    DIRECTION OUTPUT ;
    USE SIGNAL ;
    ANTENNADIFFAREA 0.897600 ;
    PORT
      LAYER Metal3 ;
        RECT 0.000 219.520 0.560 220.080 ;
    END
  END tl_h_i_o[40]
  PIN tl_h_i_o[41]
    DIRECTION OUTPUT ;
    USE SIGNAL ;
    ANTENNADIFFAREA 0.897600 ;
    PORT
      LAYER Metal3 ;
        RECT 0.000 220.640 0.560 221.200 ;
    END
  END tl_h_i_o[41]
  PIN tl_h_i_o[42]
    DIRECTION OUTPUT ;
    USE SIGNAL ;
    ANTENNADIFFAREA 0.897600 ;
    PORT
      LAYER Metal3 ;
        RECT 0.000 221.760 0.560 222.320 ;
    END
  END tl_h_i_o[42]
  PIN tl_h_i_o[43]
    DIRECTION OUTPUT ;
    USE SIGNAL ;
    ANTENNADIFFAREA 0.897600 ;
    PORT
      LAYER Metal3 ;
        RECT 0.000 222.880 0.560 223.440 ;
    END
  END tl_h_i_o[43]
  PIN tl_h_i_o[44]
    DIRECTION OUTPUT ;
    USE SIGNAL ;
    ANTENNADIFFAREA 0.897600 ;
    PORT
      LAYER Metal3 ;
        RECT 0.000 224.000 0.560 224.560 ;
    END
  END tl_h_i_o[44]
  PIN tl_h_i_o[45]
    DIRECTION OUTPUT ;
    USE SIGNAL ;
    ANTENNADIFFAREA 0.897600 ;
    PORT
      LAYER Metal3 ;
        RECT 0.000 225.120 0.560 225.680 ;
    END
  END tl_h_i_o[45]
  PIN tl_h_i_o[46]
    DIRECTION OUTPUT ;
    USE SIGNAL ;
    ANTENNADIFFAREA 0.897600 ;
    PORT
      LAYER Metal3 ;
        RECT 0.000 226.240 0.560 226.800 ;
    END
  END tl_h_i_o[46]
  PIN tl_h_i_o[47]
    DIRECTION OUTPUT ;
    USE SIGNAL ;
    ANTENNADIFFAREA 0.897600 ;
    PORT
      LAYER Metal3 ;
        RECT 0.000 227.360 0.560 227.920 ;
    END
  END tl_h_i_o[47]
  PIN tl_h_i_o[48]
    DIRECTION OUTPUT ;
    USE SIGNAL ;
    ANTENNADIFFAREA 0.897600 ;
    PORT
      LAYER Metal3 ;
        RECT 0.000 228.480 0.560 229.040 ;
    END
  END tl_h_i_o[48]
  PIN tl_h_i_o[49]
    DIRECTION OUTPUT ;
    USE SIGNAL ;
    ANTENNADIFFAREA 0.897600 ;
    PORT
      LAYER Metal3 ;
        RECT 0.000 229.600 0.560 230.160 ;
    END
  END tl_h_i_o[49]
  PIN tl_h_i_o[4]
    DIRECTION OUTPUT ;
    USE SIGNAL ;
    ANTENNADIFFAREA 0.897600 ;
    PORT
      LAYER Metal3 ;
        RECT 0.000 179.200 0.560 179.760 ;
    END
  END tl_h_i_o[4]
  PIN tl_h_i_o[50]
    DIRECTION OUTPUT ;
    USE SIGNAL ;
    ANTENNADIFFAREA 0.897600 ;
    PORT
      LAYER Metal3 ;
        RECT 0.000 230.720 0.560 231.280 ;
    END
  END tl_h_i_o[50]
  PIN tl_h_i_o[51]
    DIRECTION OUTPUT ;
    USE SIGNAL ;
    ANTENNADIFFAREA 0.897600 ;
    PORT
      LAYER Metal3 ;
        RECT 0.000 231.840 0.560 232.400 ;
    END
  END tl_h_i_o[51]
  PIN tl_h_i_o[52]
    DIRECTION OUTPUT ;
    USE SIGNAL ;
    ANTENNADIFFAREA 0.897600 ;
    PORT
      LAYER Metal3 ;
        RECT 0.000 232.960 0.560 233.520 ;
    END
  END tl_h_i_o[52]
  PIN tl_h_i_o[53]
    DIRECTION OUTPUT ;
    USE SIGNAL ;
    ANTENNADIFFAREA 0.897600 ;
    PORT
      LAYER Metal3 ;
        RECT 0.000 234.080 0.560 234.640 ;
    END
  END tl_h_i_o[53]
  PIN tl_h_i_o[54]
    DIRECTION OUTPUT ;
    USE SIGNAL ;
    ANTENNADIFFAREA 0.897600 ;
    PORT
      LAYER Metal3 ;
        RECT 0.000 235.200 0.560 235.760 ;
    END
  END tl_h_i_o[54]
  PIN tl_h_i_o[55]
    DIRECTION OUTPUT ;
    USE SIGNAL ;
    ANTENNADIFFAREA 0.897600 ;
    PORT
      LAYER Metal3 ;
        RECT 0.000 236.320 0.560 236.880 ;
    END
  END tl_h_i_o[55]
  PIN tl_h_i_o[56]
    DIRECTION OUTPUT ;
    USE SIGNAL ;
    ANTENNADIFFAREA 0.897600 ;
    PORT
      LAYER Metal3 ;
        RECT 0.000 237.440 0.560 238.000 ;
    END
  END tl_h_i_o[56]
  PIN tl_h_i_o[57]
    DIRECTION OUTPUT ;
    USE SIGNAL ;
    ANTENNADIFFAREA 0.897600 ;
    PORT
      LAYER Metal3 ;
        RECT 0.000 238.560 0.560 239.120 ;
    END
  END tl_h_i_o[57]
  PIN tl_h_i_o[58]
    DIRECTION OUTPUT ;
    USE SIGNAL ;
    ANTENNADIFFAREA 0.897600 ;
    PORT
      LAYER Metal3 ;
        RECT 0.000 239.680 0.560 240.240 ;
    END
  END tl_h_i_o[58]
  PIN tl_h_i_o[59]
    DIRECTION OUTPUT ;
    USE SIGNAL ;
    ANTENNADIFFAREA 0.897600 ;
    PORT
      LAYER Metal3 ;
        RECT 0.000 240.800 0.560 241.360 ;
    END
  END tl_h_i_o[59]
  PIN tl_h_i_o[5]
    DIRECTION OUTPUT ;
    USE SIGNAL ;
    ANTENNADIFFAREA 0.897600 ;
    PORT
      LAYER Metal3 ;
        RECT 0.000 180.320 0.560 180.880 ;
    END
  END tl_h_i_o[5]
  PIN tl_h_i_o[60]
    DIRECTION OUTPUT ;
    USE SIGNAL ;
    ANTENNADIFFAREA 0.897600 ;
    PORT
      LAYER Metal3 ;
        RECT 0.000 241.920 0.560 242.480 ;
    END
  END tl_h_i_o[60]
  PIN tl_h_i_o[61]
    DIRECTION OUTPUT ;
    USE SIGNAL ;
    ANTENNADIFFAREA 0.897600 ;
    PORT
      LAYER Metal3 ;
        RECT 0.000 243.040 0.560 243.600 ;
    END
  END tl_h_i_o[61]
  PIN tl_h_i_o[62]
    DIRECTION OUTPUT ;
    USE SIGNAL ;
    ANTENNADIFFAREA 0.897600 ;
    PORT
      LAYER Metal3 ;
        RECT 0.000 244.160 0.560 244.720 ;
    END
  END tl_h_i_o[62]
  PIN tl_h_i_o[63]
    DIRECTION OUTPUT ;
    USE SIGNAL ;
    ANTENNADIFFAREA 0.897600 ;
    PORT
      LAYER Metal3 ;
        RECT 0.000 245.280 0.560 245.840 ;
    END
  END tl_h_i_o[63]
  PIN tl_h_i_o[64]
    DIRECTION OUTPUT ;
    USE SIGNAL ;
    ANTENNADIFFAREA 0.897600 ;
    PORT
      LAYER Metal3 ;
        RECT 0.000 246.400 0.560 246.960 ;
    END
  END tl_h_i_o[64]
  PIN tl_h_i_o[65]
    DIRECTION OUTPUT ;
    USE SIGNAL ;
    ANTENNADIFFAREA 0.897600 ;
    PORT
      LAYER Metal3 ;
        RECT 0.000 247.520 0.560 248.080 ;
    END
  END tl_h_i_o[65]
  PIN tl_h_i_o[6]
    DIRECTION OUTPUT ;
    USE SIGNAL ;
    ANTENNADIFFAREA 0.897600 ;
    PORT
      LAYER Metal3 ;
        RECT 0.000 181.440 0.560 182.000 ;
    END
  END tl_h_i_o[6]
  PIN tl_h_i_o[7]
    DIRECTION OUTPUT ;
    USE SIGNAL ;
    ANTENNADIFFAREA 0.897600 ;
    PORT
      LAYER Metal3 ;
        RECT 0.000 182.560 0.560 183.120 ;
    END
  END tl_h_i_o[7]
  PIN tl_h_i_o[8]
    DIRECTION OUTPUT ;
    USE SIGNAL ;
    ANTENNADIFFAREA 0.897600 ;
    PORT
      LAYER Metal3 ;
        RECT 0.000 183.680 0.560 184.240 ;
    END
  END tl_h_i_o[8]
  PIN tl_h_i_o[9]
    DIRECTION OUTPUT ;
    USE SIGNAL ;
    ANTENNADIFFAREA 0.897600 ;
    PORT
      LAYER Metal3 ;
        RECT 0.000 184.800 0.560 185.360 ;
    END
  END tl_h_i_o[9]
  OBS
      LAYER Nwell ;
        RECT 6.290 15.250 493.230 482.590 ;
      LAYER Metal1 ;
        RECT 6.720 15.380 492.800 482.460 ;
      LAYER Metal2 ;
        RECT 1.260 499.140 47.860 499.440 ;
        RECT 451.100 499.140 499.940 499.440 ;
        RECT 1.260 0.860 499.940 499.140 ;
        RECT 1.260 0.090 44.500 0.860 ;
        RECT 45.660 0.090 46.740 0.860 ;
        RECT 47.900 0.090 48.980 0.860 ;
        RECT 50.140 0.090 51.220 0.860 ;
        RECT 52.380 0.090 53.460 0.860 ;
        RECT 54.620 0.090 55.700 0.860 ;
        RECT 56.860 0.090 57.940 0.860 ;
        RECT 59.100 0.090 60.180 0.860 ;
        RECT 61.340 0.090 62.420 0.860 ;
        RECT 63.580 0.090 64.660 0.860 ;
        RECT 65.820 0.090 66.900 0.860 ;
        RECT 68.060 0.090 69.140 0.860 ;
        RECT 70.300 0.090 71.380 0.860 ;
        RECT 72.540 0.090 73.620 0.860 ;
        RECT 74.780 0.090 75.860 0.860 ;
        RECT 77.020 0.090 78.100 0.860 ;
        RECT 79.260 0.090 80.340 0.860 ;
        RECT 81.500 0.090 82.580 0.860 ;
        RECT 83.740 0.090 84.820 0.860 ;
        RECT 85.980 0.090 87.060 0.860 ;
        RECT 88.220 0.090 89.300 0.860 ;
        RECT 90.460 0.090 91.540 0.860 ;
        RECT 92.700 0.090 93.780 0.860 ;
        RECT 94.940 0.090 96.020 0.860 ;
        RECT 97.180 0.090 98.260 0.860 ;
        RECT 99.420 0.090 100.500 0.860 ;
        RECT 101.660 0.090 102.740 0.860 ;
        RECT 103.900 0.090 104.980 0.860 ;
        RECT 106.140 0.090 107.220 0.860 ;
        RECT 108.380 0.090 109.460 0.860 ;
        RECT 110.620 0.090 111.700 0.860 ;
        RECT 112.860 0.090 113.940 0.860 ;
        RECT 115.100 0.090 116.180 0.860 ;
        RECT 117.340 0.090 118.420 0.860 ;
        RECT 119.580 0.090 120.660 0.860 ;
        RECT 121.820 0.090 122.900 0.860 ;
        RECT 124.060 0.090 125.140 0.860 ;
        RECT 126.300 0.090 127.380 0.860 ;
        RECT 128.540 0.090 129.620 0.860 ;
        RECT 130.780 0.090 131.860 0.860 ;
        RECT 133.020 0.090 134.100 0.860 ;
        RECT 135.260 0.090 136.340 0.860 ;
        RECT 137.500 0.090 138.580 0.860 ;
        RECT 139.740 0.090 140.820 0.860 ;
        RECT 141.980 0.090 143.060 0.860 ;
        RECT 144.220 0.090 145.300 0.860 ;
        RECT 146.460 0.090 147.540 0.860 ;
        RECT 148.700 0.090 149.780 0.860 ;
        RECT 150.940 0.090 152.020 0.860 ;
        RECT 153.180 0.090 154.260 0.860 ;
        RECT 155.420 0.090 156.500 0.860 ;
        RECT 157.660 0.090 158.740 0.860 ;
        RECT 159.900 0.090 160.980 0.860 ;
        RECT 162.140 0.090 163.220 0.860 ;
        RECT 164.380 0.090 165.460 0.860 ;
        RECT 166.620 0.090 167.700 0.860 ;
        RECT 168.860 0.090 169.940 0.860 ;
        RECT 171.100 0.090 172.180 0.860 ;
        RECT 173.340 0.090 174.420 0.860 ;
        RECT 175.580 0.090 176.660 0.860 ;
        RECT 177.820 0.090 178.900 0.860 ;
        RECT 180.060 0.090 181.140 0.860 ;
        RECT 182.300 0.090 183.380 0.860 ;
        RECT 184.540 0.090 185.620 0.860 ;
        RECT 186.780 0.090 187.860 0.860 ;
        RECT 189.020 0.090 190.100 0.860 ;
        RECT 191.260 0.090 192.340 0.860 ;
        RECT 193.500 0.090 194.580 0.860 ;
        RECT 195.740 0.090 196.820 0.860 ;
        RECT 197.980 0.090 199.060 0.860 ;
        RECT 200.220 0.090 201.300 0.860 ;
        RECT 202.460 0.090 203.540 0.860 ;
        RECT 204.700 0.090 205.780 0.860 ;
        RECT 206.940 0.090 208.020 0.860 ;
        RECT 209.180 0.090 210.260 0.860 ;
        RECT 211.420 0.090 212.500 0.860 ;
        RECT 213.660 0.090 214.740 0.860 ;
        RECT 215.900 0.090 216.980 0.860 ;
        RECT 218.140 0.090 219.220 0.860 ;
        RECT 220.380 0.090 221.460 0.860 ;
        RECT 222.620 0.090 223.700 0.860 ;
        RECT 224.860 0.090 225.940 0.860 ;
        RECT 227.100 0.090 228.180 0.860 ;
        RECT 229.340 0.090 230.420 0.860 ;
        RECT 231.580 0.090 232.660 0.860 ;
        RECT 233.820 0.090 234.900 0.860 ;
        RECT 236.060 0.090 237.140 0.860 ;
        RECT 238.300 0.090 239.380 0.860 ;
        RECT 240.540 0.090 241.620 0.860 ;
        RECT 242.780 0.090 243.860 0.860 ;
        RECT 245.020 0.090 246.100 0.860 ;
        RECT 247.260 0.090 248.340 0.860 ;
        RECT 249.500 0.090 250.580 0.860 ;
        RECT 251.740 0.090 252.820 0.860 ;
        RECT 253.980 0.090 255.060 0.860 ;
        RECT 256.220 0.090 257.300 0.860 ;
        RECT 258.460 0.090 259.540 0.860 ;
        RECT 260.700 0.090 261.780 0.860 ;
        RECT 262.940 0.090 264.020 0.860 ;
        RECT 265.180 0.090 266.260 0.860 ;
        RECT 267.420 0.090 268.500 0.860 ;
        RECT 269.660 0.090 270.740 0.860 ;
        RECT 271.900 0.090 272.980 0.860 ;
        RECT 274.140 0.090 275.220 0.860 ;
        RECT 276.380 0.090 277.460 0.860 ;
        RECT 278.620 0.090 279.700 0.860 ;
        RECT 280.860 0.090 281.940 0.860 ;
        RECT 283.100 0.090 284.180 0.860 ;
        RECT 285.340 0.090 286.420 0.860 ;
        RECT 287.580 0.090 288.660 0.860 ;
        RECT 289.820 0.090 290.900 0.860 ;
        RECT 292.060 0.090 293.140 0.860 ;
        RECT 294.300 0.090 295.380 0.860 ;
        RECT 296.540 0.090 297.620 0.860 ;
        RECT 298.780 0.090 299.860 0.860 ;
        RECT 301.020 0.090 302.100 0.860 ;
        RECT 303.260 0.090 304.340 0.860 ;
        RECT 305.500 0.090 306.580 0.860 ;
        RECT 307.740 0.090 308.820 0.860 ;
        RECT 309.980 0.090 311.060 0.860 ;
        RECT 312.220 0.090 313.300 0.860 ;
        RECT 314.460 0.090 315.540 0.860 ;
        RECT 316.700 0.090 317.780 0.860 ;
        RECT 318.940 0.090 320.020 0.860 ;
        RECT 321.180 0.090 322.260 0.860 ;
        RECT 323.420 0.090 324.500 0.860 ;
        RECT 325.660 0.090 326.740 0.860 ;
        RECT 327.900 0.090 328.980 0.860 ;
        RECT 330.140 0.090 331.220 0.860 ;
        RECT 332.380 0.090 333.460 0.860 ;
        RECT 334.620 0.090 335.700 0.860 ;
        RECT 336.860 0.090 337.940 0.860 ;
        RECT 339.100 0.090 340.180 0.860 ;
        RECT 341.340 0.090 342.420 0.860 ;
        RECT 343.580 0.090 344.660 0.860 ;
        RECT 345.820 0.090 346.900 0.860 ;
        RECT 348.060 0.090 349.140 0.860 ;
        RECT 350.300 0.090 351.380 0.860 ;
        RECT 352.540 0.090 353.620 0.860 ;
        RECT 354.780 0.090 355.860 0.860 ;
        RECT 357.020 0.090 358.100 0.860 ;
        RECT 359.260 0.090 360.340 0.860 ;
        RECT 361.500 0.090 362.580 0.860 ;
        RECT 363.740 0.090 364.820 0.860 ;
        RECT 365.980 0.090 367.060 0.860 ;
        RECT 368.220 0.090 369.300 0.860 ;
        RECT 370.460 0.090 371.540 0.860 ;
        RECT 372.700 0.090 373.780 0.860 ;
        RECT 374.940 0.090 376.020 0.860 ;
        RECT 377.180 0.090 378.260 0.860 ;
        RECT 379.420 0.090 380.500 0.860 ;
        RECT 381.660 0.090 382.740 0.860 ;
        RECT 383.900 0.090 384.980 0.860 ;
        RECT 386.140 0.090 387.220 0.860 ;
        RECT 388.380 0.090 389.460 0.860 ;
        RECT 390.620 0.090 391.700 0.860 ;
        RECT 392.860 0.090 393.940 0.860 ;
        RECT 395.100 0.090 396.180 0.860 ;
        RECT 397.340 0.090 398.420 0.860 ;
        RECT 399.580 0.090 400.660 0.860 ;
        RECT 401.820 0.090 402.900 0.860 ;
        RECT 404.060 0.090 405.140 0.860 ;
        RECT 406.300 0.090 407.380 0.860 ;
        RECT 408.540 0.090 409.620 0.860 ;
        RECT 410.780 0.090 411.860 0.860 ;
        RECT 413.020 0.090 414.100 0.860 ;
        RECT 415.260 0.090 416.340 0.860 ;
        RECT 417.500 0.090 418.580 0.860 ;
        RECT 419.740 0.090 420.820 0.860 ;
        RECT 421.980 0.090 423.060 0.860 ;
        RECT 424.220 0.090 425.300 0.860 ;
        RECT 426.460 0.090 427.540 0.860 ;
        RECT 428.700 0.090 429.780 0.860 ;
        RECT 430.940 0.090 432.020 0.860 ;
        RECT 433.180 0.090 434.260 0.860 ;
        RECT 435.420 0.090 436.500 0.860 ;
        RECT 437.660 0.090 438.740 0.860 ;
        RECT 439.900 0.090 440.980 0.860 ;
        RECT 442.140 0.090 443.220 0.860 ;
        RECT 444.380 0.090 445.460 0.860 ;
        RECT 446.620 0.090 447.700 0.860 ;
        RECT 448.860 0.090 449.940 0.860 ;
        RECT 451.100 0.090 452.180 0.860 ;
        RECT 453.340 0.090 454.420 0.860 ;
        RECT 455.580 0.090 499.940 0.860 ;
      LAYER Metal3 ;
        RECT 0.560 452.220 499.990 499.940 ;
        RECT 0.860 451.100 499.990 452.220 ;
        RECT 0.860 449.940 499.140 451.100 ;
        RECT 0.860 448.860 499.990 449.940 ;
        RECT 0.860 447.700 499.140 448.860 ;
        RECT 0.860 446.620 499.990 447.700 ;
        RECT 0.860 445.460 499.140 446.620 ;
        RECT 0.860 444.380 499.990 445.460 ;
        RECT 0.860 443.220 499.140 444.380 ;
        RECT 0.860 442.140 499.990 443.220 ;
        RECT 0.860 440.980 499.140 442.140 ;
        RECT 0.860 439.900 499.990 440.980 ;
        RECT 0.860 438.740 499.140 439.900 ;
        RECT 0.860 437.660 499.990 438.740 ;
        RECT 0.860 436.500 499.140 437.660 ;
        RECT 0.860 435.420 499.990 436.500 ;
        RECT 0.860 434.260 499.140 435.420 ;
        RECT 0.860 433.180 499.990 434.260 ;
        RECT 0.860 432.020 499.140 433.180 ;
        RECT 0.860 430.940 499.990 432.020 ;
        RECT 0.860 429.780 499.140 430.940 ;
        RECT 0.860 428.700 499.990 429.780 ;
        RECT 0.860 427.540 499.140 428.700 ;
        RECT 0.860 426.460 499.990 427.540 ;
        RECT 0.860 425.300 499.140 426.460 ;
        RECT 0.860 424.220 499.990 425.300 ;
        RECT 0.860 423.060 499.140 424.220 ;
        RECT 0.860 421.980 499.990 423.060 ;
        RECT 0.860 420.820 499.140 421.980 ;
        RECT 0.860 419.740 499.990 420.820 ;
        RECT 0.860 418.580 499.140 419.740 ;
        RECT 0.860 417.500 499.990 418.580 ;
        RECT 0.860 416.340 499.140 417.500 ;
        RECT 0.860 415.260 499.990 416.340 ;
        RECT 0.860 414.100 499.140 415.260 ;
        RECT 0.860 413.020 499.990 414.100 ;
        RECT 0.860 411.860 499.140 413.020 ;
        RECT 0.860 410.780 499.990 411.860 ;
        RECT 0.860 409.620 499.140 410.780 ;
        RECT 0.860 408.540 499.990 409.620 ;
        RECT 0.860 407.380 499.140 408.540 ;
        RECT 0.860 406.300 499.990 407.380 ;
        RECT 0.860 405.140 499.140 406.300 ;
        RECT 0.860 404.060 499.990 405.140 ;
        RECT 0.860 402.900 499.140 404.060 ;
        RECT 0.860 401.820 499.990 402.900 ;
        RECT 0.860 400.660 499.140 401.820 ;
        RECT 0.860 399.580 499.990 400.660 ;
        RECT 0.860 398.420 499.140 399.580 ;
        RECT 0.860 397.340 499.990 398.420 ;
        RECT 0.860 396.180 499.140 397.340 ;
        RECT 0.860 395.100 499.990 396.180 ;
        RECT 0.860 393.940 499.140 395.100 ;
        RECT 0.860 392.860 499.990 393.940 ;
        RECT 0.860 391.700 499.140 392.860 ;
        RECT 0.860 390.620 499.990 391.700 ;
        RECT 0.860 389.460 499.140 390.620 ;
        RECT 0.860 388.380 499.990 389.460 ;
        RECT 0.860 387.220 499.140 388.380 ;
        RECT 0.860 386.140 499.990 387.220 ;
        RECT 0.860 384.980 499.140 386.140 ;
        RECT 0.860 383.900 499.990 384.980 ;
        RECT 0.860 382.740 499.140 383.900 ;
        RECT 0.860 381.660 499.990 382.740 ;
        RECT 0.860 380.500 499.140 381.660 ;
        RECT 0.860 379.420 499.990 380.500 ;
        RECT 0.860 378.260 499.140 379.420 ;
        RECT 0.860 377.180 499.990 378.260 ;
        RECT 0.860 376.020 499.140 377.180 ;
        RECT 0.860 374.940 499.990 376.020 ;
        RECT 0.860 373.780 499.140 374.940 ;
        RECT 0.860 372.700 499.990 373.780 ;
        RECT 0.860 371.540 499.140 372.700 ;
        RECT 0.860 370.460 499.990 371.540 ;
        RECT 0.860 369.300 499.140 370.460 ;
        RECT 0.860 368.220 499.990 369.300 ;
        RECT 0.860 367.060 499.140 368.220 ;
        RECT 0.860 365.980 499.990 367.060 ;
        RECT 0.860 364.820 499.140 365.980 ;
        RECT 0.860 363.740 499.990 364.820 ;
        RECT 0.860 362.580 499.140 363.740 ;
        RECT 0.860 361.500 499.990 362.580 ;
        RECT 0.860 360.340 499.140 361.500 ;
        RECT 0.860 359.260 499.990 360.340 ;
        RECT 0.860 358.100 499.140 359.260 ;
        RECT 0.860 357.020 499.990 358.100 ;
        RECT 0.860 355.860 499.140 357.020 ;
        RECT 0.860 354.780 499.990 355.860 ;
        RECT 0.860 353.620 499.140 354.780 ;
        RECT 0.860 352.540 499.990 353.620 ;
        RECT 0.860 351.380 499.140 352.540 ;
        RECT 0.860 350.300 499.990 351.380 ;
        RECT 0.860 349.140 499.140 350.300 ;
        RECT 0.860 348.060 499.990 349.140 ;
        RECT 0.860 346.900 499.140 348.060 ;
        RECT 0.860 345.820 499.990 346.900 ;
        RECT 0.860 344.660 499.140 345.820 ;
        RECT 0.860 343.580 499.990 344.660 ;
        RECT 0.860 342.420 499.140 343.580 ;
        RECT 0.860 341.340 499.990 342.420 ;
        RECT 0.860 340.180 499.140 341.340 ;
        RECT 0.860 339.100 499.990 340.180 ;
        RECT 0.860 337.940 499.140 339.100 ;
        RECT 0.860 336.860 499.990 337.940 ;
        RECT 0.860 335.700 499.140 336.860 ;
        RECT 0.860 334.620 499.990 335.700 ;
        RECT 0.860 333.460 499.140 334.620 ;
        RECT 0.860 332.380 499.990 333.460 ;
        RECT 0.860 331.220 499.140 332.380 ;
        RECT 0.860 330.140 499.990 331.220 ;
        RECT 0.860 328.980 499.140 330.140 ;
        RECT 0.860 327.900 499.990 328.980 ;
        RECT 0.860 326.740 499.140 327.900 ;
        RECT 0.860 325.660 499.990 326.740 ;
        RECT 0.860 324.500 499.140 325.660 ;
        RECT 0.860 323.420 499.990 324.500 ;
        RECT 0.860 322.260 499.140 323.420 ;
        RECT 0.860 321.180 499.990 322.260 ;
        RECT 0.860 320.020 499.140 321.180 ;
        RECT 0.860 318.940 499.990 320.020 ;
        RECT 0.860 317.780 499.140 318.940 ;
        RECT 0.860 316.700 499.990 317.780 ;
        RECT 0.860 315.540 499.140 316.700 ;
        RECT 0.860 314.460 499.990 315.540 ;
        RECT 0.860 313.300 499.140 314.460 ;
        RECT 0.860 312.220 499.990 313.300 ;
        RECT 0.860 311.060 499.140 312.220 ;
        RECT 0.860 309.980 499.990 311.060 ;
        RECT 0.860 308.820 499.140 309.980 ;
        RECT 0.860 307.740 499.990 308.820 ;
        RECT 0.860 306.580 499.140 307.740 ;
        RECT 0.860 305.500 499.990 306.580 ;
        RECT 0.860 304.340 499.140 305.500 ;
        RECT 0.860 303.260 499.990 304.340 ;
        RECT 0.860 302.100 499.140 303.260 ;
        RECT 0.860 301.020 499.990 302.100 ;
        RECT 0.860 299.860 499.140 301.020 ;
        RECT 0.860 298.780 499.990 299.860 ;
        RECT 0.860 297.620 499.140 298.780 ;
        RECT 0.860 296.540 499.990 297.620 ;
        RECT 0.860 295.380 499.140 296.540 ;
        RECT 0.860 294.300 499.990 295.380 ;
        RECT 0.860 293.140 499.140 294.300 ;
        RECT 0.860 292.060 499.990 293.140 ;
        RECT 0.860 290.900 499.140 292.060 ;
        RECT 0.860 289.820 499.990 290.900 ;
        RECT 0.860 288.660 499.140 289.820 ;
        RECT 0.860 287.580 499.990 288.660 ;
        RECT 0.860 286.420 499.140 287.580 ;
        RECT 0.860 285.340 499.990 286.420 ;
        RECT 0.860 284.180 499.140 285.340 ;
        RECT 0.860 283.100 499.990 284.180 ;
        RECT 0.860 281.940 499.140 283.100 ;
        RECT 0.860 280.860 499.990 281.940 ;
        RECT 0.860 279.700 499.140 280.860 ;
        RECT 0.860 278.620 499.990 279.700 ;
        RECT 0.860 277.460 499.140 278.620 ;
        RECT 0.860 276.380 499.990 277.460 ;
        RECT 0.860 275.220 499.140 276.380 ;
        RECT 0.860 274.140 499.990 275.220 ;
        RECT 0.860 272.980 499.140 274.140 ;
        RECT 0.860 271.900 499.990 272.980 ;
        RECT 0.860 270.740 499.140 271.900 ;
        RECT 0.860 269.660 499.990 270.740 ;
        RECT 0.860 268.500 499.140 269.660 ;
        RECT 0.860 267.420 499.990 268.500 ;
        RECT 0.860 266.260 499.140 267.420 ;
        RECT 0.860 265.180 499.990 266.260 ;
        RECT 0.860 264.020 499.140 265.180 ;
        RECT 0.860 262.940 499.990 264.020 ;
        RECT 0.860 261.780 499.140 262.940 ;
        RECT 0.860 260.700 499.990 261.780 ;
        RECT 0.860 259.540 499.140 260.700 ;
        RECT 0.860 258.460 499.990 259.540 ;
        RECT 0.860 257.300 499.140 258.460 ;
        RECT 0.860 256.220 499.990 257.300 ;
        RECT 0.860 255.060 499.140 256.220 ;
        RECT 0.860 253.980 499.990 255.060 ;
        RECT 0.860 252.820 499.140 253.980 ;
        RECT 0.860 251.740 499.990 252.820 ;
        RECT 0.860 250.580 499.140 251.740 ;
        RECT 0.860 249.500 499.990 250.580 ;
        RECT 0.860 248.340 499.140 249.500 ;
        RECT 0.860 247.260 499.990 248.340 ;
        RECT 0.860 246.100 499.140 247.260 ;
        RECT 0.860 245.020 499.990 246.100 ;
        RECT 0.860 243.860 499.140 245.020 ;
        RECT 0.860 242.780 499.990 243.860 ;
        RECT 0.860 241.620 499.140 242.780 ;
        RECT 0.860 240.540 499.990 241.620 ;
        RECT 0.860 239.380 499.140 240.540 ;
        RECT 0.860 238.300 499.990 239.380 ;
        RECT 0.860 237.140 499.140 238.300 ;
        RECT 0.860 236.060 499.990 237.140 ;
        RECT 0.860 234.900 499.140 236.060 ;
        RECT 0.860 233.820 499.990 234.900 ;
        RECT 0.860 232.660 499.140 233.820 ;
        RECT 0.860 231.580 499.990 232.660 ;
        RECT 0.860 230.420 499.140 231.580 ;
        RECT 0.860 229.340 499.990 230.420 ;
        RECT 0.860 228.180 499.140 229.340 ;
        RECT 0.860 227.100 499.990 228.180 ;
        RECT 0.860 225.940 499.140 227.100 ;
        RECT 0.860 224.860 499.990 225.940 ;
        RECT 0.860 223.700 499.140 224.860 ;
        RECT 0.860 222.620 499.990 223.700 ;
        RECT 0.860 221.460 499.140 222.620 ;
        RECT 0.860 220.380 499.990 221.460 ;
        RECT 0.860 219.220 499.140 220.380 ;
        RECT 0.860 218.140 499.990 219.220 ;
        RECT 0.860 216.980 499.140 218.140 ;
        RECT 0.860 215.900 499.990 216.980 ;
        RECT 0.860 214.740 499.140 215.900 ;
        RECT 0.860 213.660 499.990 214.740 ;
        RECT 0.860 212.500 499.140 213.660 ;
        RECT 0.860 211.420 499.990 212.500 ;
        RECT 0.860 210.260 499.140 211.420 ;
        RECT 0.860 209.180 499.990 210.260 ;
        RECT 0.860 208.020 499.140 209.180 ;
        RECT 0.860 206.940 499.990 208.020 ;
        RECT 0.860 205.780 499.140 206.940 ;
        RECT 0.860 204.700 499.990 205.780 ;
        RECT 0.860 203.540 499.140 204.700 ;
        RECT 0.860 202.460 499.990 203.540 ;
        RECT 0.860 201.300 499.140 202.460 ;
        RECT 0.860 200.220 499.990 201.300 ;
        RECT 0.860 199.060 499.140 200.220 ;
        RECT 0.860 197.980 499.990 199.060 ;
        RECT 0.860 196.820 499.140 197.980 ;
        RECT 0.860 195.740 499.990 196.820 ;
        RECT 0.860 194.580 499.140 195.740 ;
        RECT 0.860 193.500 499.990 194.580 ;
        RECT 0.860 192.340 499.140 193.500 ;
        RECT 0.860 191.260 499.990 192.340 ;
        RECT 0.860 190.100 499.140 191.260 ;
        RECT 0.860 189.020 499.990 190.100 ;
        RECT 0.860 187.860 499.140 189.020 ;
        RECT 0.860 186.780 499.990 187.860 ;
        RECT 0.860 185.620 499.140 186.780 ;
        RECT 0.860 184.540 499.990 185.620 ;
        RECT 0.860 183.380 499.140 184.540 ;
        RECT 0.860 182.300 499.990 183.380 ;
        RECT 0.860 181.140 499.140 182.300 ;
        RECT 0.860 180.060 499.990 181.140 ;
        RECT 0.860 178.900 499.140 180.060 ;
        RECT 0.860 177.820 499.990 178.900 ;
        RECT 0.860 176.660 499.140 177.820 ;
        RECT 0.860 175.580 499.990 176.660 ;
        RECT 0.860 174.420 499.140 175.580 ;
        RECT 0.860 173.340 499.990 174.420 ;
        RECT 0.860 172.180 499.140 173.340 ;
        RECT 0.860 171.100 499.990 172.180 ;
        RECT 0.860 169.940 499.140 171.100 ;
        RECT 0.860 168.860 499.990 169.940 ;
        RECT 0.860 167.700 499.140 168.860 ;
        RECT 0.860 166.620 499.990 167.700 ;
        RECT 0.860 165.460 499.140 166.620 ;
        RECT 0.860 164.380 499.990 165.460 ;
        RECT 0.860 163.220 499.140 164.380 ;
        RECT 0.860 162.140 499.990 163.220 ;
        RECT 0.860 160.980 499.140 162.140 ;
        RECT 0.860 159.900 499.990 160.980 ;
        RECT 0.860 158.740 499.140 159.900 ;
        RECT 0.860 157.660 499.990 158.740 ;
        RECT 0.860 156.500 499.140 157.660 ;
        RECT 0.860 155.420 499.990 156.500 ;
        RECT 0.860 154.260 499.140 155.420 ;
        RECT 0.860 153.180 499.990 154.260 ;
        RECT 0.860 152.020 499.140 153.180 ;
        RECT 0.860 150.940 499.990 152.020 ;
        RECT 0.860 149.780 499.140 150.940 ;
        RECT 0.860 148.700 499.990 149.780 ;
        RECT 0.860 147.540 499.140 148.700 ;
        RECT 0.860 146.460 499.990 147.540 ;
        RECT 0.860 145.300 499.140 146.460 ;
        RECT 0.860 144.220 499.990 145.300 ;
        RECT 0.860 143.060 499.140 144.220 ;
        RECT 0.860 141.980 499.990 143.060 ;
        RECT 0.860 140.820 499.140 141.980 ;
        RECT 0.860 139.740 499.990 140.820 ;
        RECT 0.860 138.580 499.140 139.740 ;
        RECT 0.860 137.500 499.990 138.580 ;
        RECT 0.860 136.340 499.140 137.500 ;
        RECT 0.860 135.260 499.990 136.340 ;
        RECT 0.860 134.100 499.140 135.260 ;
        RECT 0.860 133.020 499.990 134.100 ;
        RECT 0.860 131.860 499.140 133.020 ;
        RECT 0.860 130.780 499.990 131.860 ;
        RECT 0.860 129.620 499.140 130.780 ;
        RECT 0.860 128.540 499.990 129.620 ;
        RECT 0.860 127.380 499.140 128.540 ;
        RECT 0.860 126.300 499.990 127.380 ;
        RECT 0.860 125.140 499.140 126.300 ;
        RECT 0.860 124.060 499.990 125.140 ;
        RECT 0.860 122.900 499.140 124.060 ;
        RECT 0.860 121.820 499.990 122.900 ;
        RECT 0.860 120.660 499.140 121.820 ;
        RECT 0.860 119.580 499.990 120.660 ;
        RECT 0.860 118.420 499.140 119.580 ;
        RECT 0.860 117.340 499.990 118.420 ;
        RECT 0.860 116.180 499.140 117.340 ;
        RECT 0.860 115.100 499.990 116.180 ;
        RECT 0.860 113.940 499.140 115.100 ;
        RECT 0.860 112.860 499.990 113.940 ;
        RECT 0.860 111.700 499.140 112.860 ;
        RECT 0.860 110.620 499.990 111.700 ;
        RECT 0.860 109.460 499.140 110.620 ;
        RECT 0.860 108.380 499.990 109.460 ;
        RECT 0.860 107.220 499.140 108.380 ;
        RECT 0.860 106.140 499.990 107.220 ;
        RECT 0.860 104.980 499.140 106.140 ;
        RECT 0.860 103.900 499.990 104.980 ;
        RECT 0.860 102.740 499.140 103.900 ;
        RECT 0.860 101.660 499.990 102.740 ;
        RECT 0.860 100.500 499.140 101.660 ;
        RECT 0.860 99.420 499.990 100.500 ;
        RECT 0.860 98.260 499.140 99.420 ;
        RECT 0.860 97.180 499.990 98.260 ;
        RECT 0.860 96.020 499.140 97.180 ;
        RECT 0.860 94.940 499.990 96.020 ;
        RECT 0.860 93.780 499.140 94.940 ;
        RECT 0.860 92.700 499.990 93.780 ;
        RECT 0.860 91.540 499.140 92.700 ;
        RECT 0.860 90.460 499.990 91.540 ;
        RECT 0.860 89.300 499.140 90.460 ;
        RECT 0.860 88.220 499.990 89.300 ;
        RECT 0.860 87.060 499.140 88.220 ;
        RECT 0.860 85.980 499.990 87.060 ;
        RECT 0.860 84.820 499.140 85.980 ;
        RECT 0.860 83.740 499.990 84.820 ;
        RECT 0.860 82.580 499.140 83.740 ;
        RECT 0.860 81.500 499.990 82.580 ;
        RECT 0.860 80.340 499.140 81.500 ;
        RECT 0.860 79.260 499.990 80.340 ;
        RECT 0.860 78.100 499.140 79.260 ;
        RECT 0.860 77.020 499.990 78.100 ;
        RECT 0.860 75.860 499.140 77.020 ;
        RECT 0.860 74.780 499.990 75.860 ;
        RECT 0.860 73.620 499.140 74.780 ;
        RECT 0.860 72.540 499.990 73.620 ;
        RECT 0.860 71.380 499.140 72.540 ;
        RECT 0.860 70.300 499.990 71.380 ;
        RECT 0.860 69.140 499.140 70.300 ;
        RECT 0.860 68.060 499.990 69.140 ;
        RECT 0.860 66.900 499.140 68.060 ;
        RECT 0.860 65.820 499.990 66.900 ;
        RECT 0.860 64.660 499.140 65.820 ;
        RECT 0.860 63.580 499.990 64.660 ;
        RECT 0.860 62.420 499.140 63.580 ;
        RECT 0.860 61.340 499.990 62.420 ;
        RECT 0.860 60.180 499.140 61.340 ;
        RECT 0.860 59.100 499.990 60.180 ;
        RECT 0.860 57.940 499.140 59.100 ;
        RECT 0.860 56.860 499.990 57.940 ;
        RECT 0.860 55.700 499.140 56.860 ;
        RECT 0.860 54.620 499.990 55.700 ;
        RECT 0.860 53.460 499.140 54.620 ;
        RECT 0.860 52.380 499.990 53.460 ;
        RECT 0.860 51.220 499.140 52.380 ;
        RECT 0.860 50.140 499.990 51.220 ;
        RECT 0.860 48.980 499.140 50.140 ;
        RECT 0.860 46.740 499.990 48.980 ;
        RECT 0.560 0.140 499.990 46.740 ;
      LAYER Metal4 ;
        RECT 0.700 482.760 498.820 497.750 ;
        RECT 0.700 15.080 21.940 482.760 ;
        RECT 24.140 15.080 25.240 482.760 ;
        RECT 27.440 15.080 175.540 482.760 ;
        RECT 177.740 15.080 178.840 482.760 ;
        RECT 181.040 15.080 329.140 482.760 ;
        RECT 331.340 15.080 332.440 482.760 ;
        RECT 334.640 15.080 482.740 482.760 ;
        RECT 484.940 15.080 486.040 482.760 ;
        RECT 488.240 15.080 498.820 482.760 ;
        RECT 0.700 14.650 498.820 15.080 ;
      LAYER Metal5 ;
        RECT 4.540 343.390 491.620 486.670 ;
        RECT 4.540 340.590 6.120 343.390 ;
        RECT 4.540 340.090 491.620 340.590 ;
        RECT 4.540 337.290 6.120 340.090 ;
        RECT 4.540 190.210 491.620 337.290 ;
        RECT 4.540 187.410 6.120 190.210 ;
        RECT 4.540 186.910 491.620 187.410 ;
        RECT 4.540 184.110 6.120 186.910 ;
        RECT 4.540 46.130 491.620 184.110 ;
  END
END xbar_tlul_2to4
END LIBRARY

